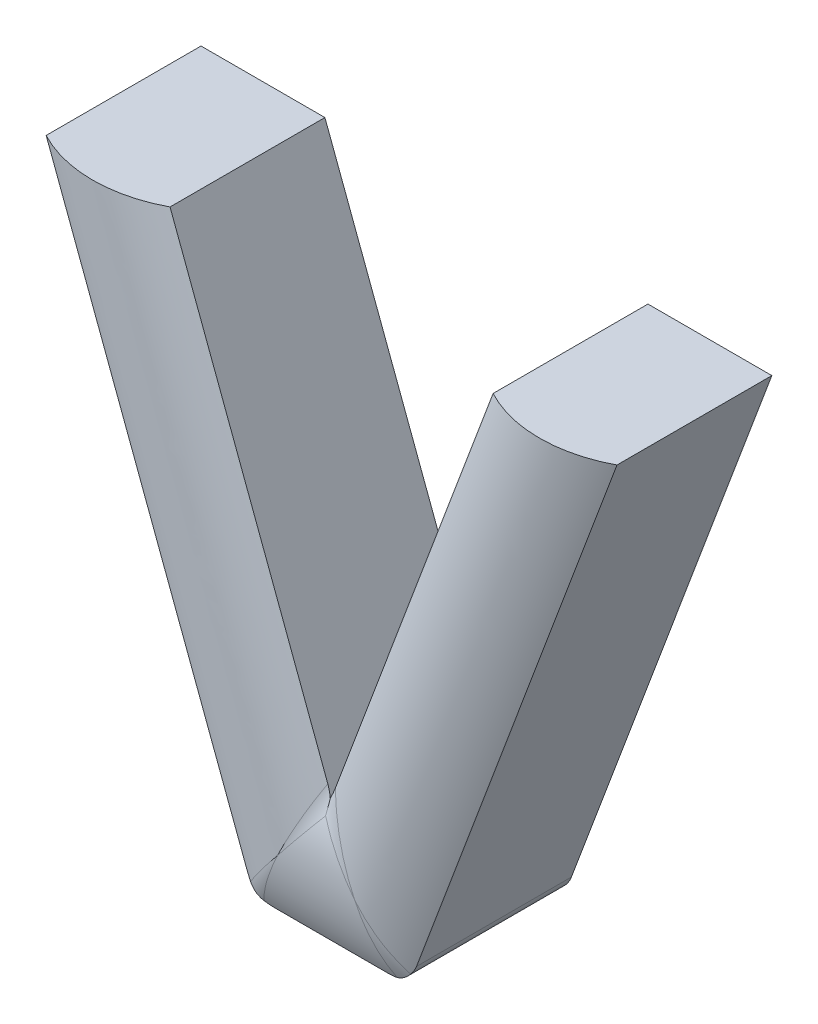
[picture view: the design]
ISO-10303-21;
HEADER;
FILE_DESCRIPTION(('STEP AP214'),'2;1');
FILE_NAME('part.step','',(''),(''),'','','');
FILE_SCHEMA(('AUTOMOTIVE_DESIGN { 1 0 10303 214 1 1 1 1 }'));
ENDSEC;
DATA;
#1=APPLICATION_CONTEXT('core data for automotive mechanical design processes');
#2=APPLICATION_PROTOCOL_DEFINITION('international standard','automotive_design',2000,#1);
#3=PRODUCT_CONTEXT('',#1,'mechanical');
#4=PRODUCT('Part','Part','',(#3));
#5=PRODUCT_RELATED_PRODUCT_CATEGORY('part','',(#4));
#6=PRODUCT_DEFINITION_FORMATION('','',#4);
#7=PRODUCT_DEFINITION_CONTEXT('part definition',#1,'design');
#8=PRODUCT_DEFINITION('design','',#6,#7);
#9=PRODUCT_DEFINITION_SHAPE('','',#8);
#10=(LENGTH_UNIT() NAMED_UNIT(*) SI_UNIT(.MILLI.,.METRE.));
#11=(NAMED_UNIT(*) PLANE_ANGLE_UNIT() SI_UNIT($,.RADIAN.));
#12=(NAMED_UNIT(*) SI_UNIT($,.STERADIAN.) SOLID_ANGLE_UNIT());
#13=UNCERTAINTY_MEASURE_WITH_UNIT(LENGTH_MEASURE(1.E-05),#10,'distance_accuracy_value','');
#14=(GEOMETRIC_REPRESENTATION_CONTEXT(3) GLOBAL_UNCERTAINTY_ASSIGNED_CONTEXT((#13)) GLOBAL_UNIT_ASSIGNED_CONTEXT((#10,
#11,#12)) REPRESENTATION_CONTEXT('',''));
#15=CARTESIAN_POINT('',(0.,0.,0.));
#16=DIRECTION('',(0.,0.,1.));
#17=DIRECTION('',(1.,0.,0.));
#18=AXIS2_PLACEMENT_3D('',#15,#16,#17);
#19=CARTESIAN_POINT('',(9.99999999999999,7.99999999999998,10.));
#20=CARTESIAN_POINT('',(9.80293541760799,7.68469666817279,10.1681617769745));
#21=CARTESIAN_POINT('',(9.6018816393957,7.36301062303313,10.3142985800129));
#22=CARTESIAN_POINT('',(9.19222223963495,6.70755558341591,10.5648772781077));
#23=CARTESIAN_POINT('',(8.9826653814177,6.37226461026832,10.6696355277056));
#24=CARTESIAN_POINT('',(8.35050491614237,5.36080786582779,10.9190580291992));
#25=CARTESIAN_POINT('',(7.92579834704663,4.6812773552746,11.0002616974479));
#26=CARTESIAN_POINT('',(7.28404710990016,3.65447537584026,10.9998682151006));
#27=CARTESIAN_POINT('',(7.06855851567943,3.30969362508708,10.9789798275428));
#28=CARTESIAN_POINT('',(6.63943695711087,2.62309913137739,10.8948654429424));
#29=CARTESIAN_POINT('',(6.42772278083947,2.28435644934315,10.8321777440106));
#30=CARTESIAN_POINT('',(5.80101287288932,1.28162059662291,10.5829999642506));
#31=CARTESIAN_POINT('',(5.39430138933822,0.630882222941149,10.3364705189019));
#32=CARTESIAN_POINT('',(5.,0.,10.));
#33=B_SPLINE_CURVE_WITH_KNOTS('',3,(#19,#20,#21,#22,#23,#24,#25,#26,#27,#28,#29,#30,#31,#32),
.UNSPECIFIED.,.F.,.F.,(4,2,2,2,2,2,4),(0.,0.125,0.25,0.5,0.625,0.75,1.),.UNSPECIFIED.);
#34=DIRECTION('',(-1.,0.,0.));
#35=VECTOR('',#34,1.);
#36=SURFACE_OF_LINEAR_EXTRUSION('',#33,#35);
#37=CARTESIAN_POINT('',(2.49997175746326,4.0000488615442,11.0000000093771));
#38=CARTESIAN_POINT('',(2.49997175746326,4.0000488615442,11.0000000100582));
#39=CARTESIAN_POINT('',(2.49997176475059,4.00004885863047,11.0000000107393));
#40=CARTESIAN_POINT('',(2.4961436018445,4.00491754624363,11.0000000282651));
#41=CARTESIAN_POINT('',(2.49670318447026,4.00527206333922,11.0000000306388));
#42=CARTESIAN_POINT('',(2.49726277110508,4.00562657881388,11.0000000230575));
#43=CARTESIAN_POINT('',(2.49232302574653,4.00978984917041,10.9999959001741));
#44=CARTESIAN_POINT('',(2.49344307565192,4.0104991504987,10.9999953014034));
#45=CARTESIAN_POINT('',(2.49456312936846,4.01120844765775,10.9999960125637));
#46=CARTESIAN_POINT('',(2.47284935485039,4.0346745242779,10.9999536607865));
#47=CARTESIAN_POINT('',(2.4768336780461,4.03719608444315,10.9999469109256));
#48=CARTESIAN_POINT('',(2.48081801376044,4.03971761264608,10.9999549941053));
#49=CARTESIAN_POINT('',(2.45728604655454,4.0547285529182,10.9998498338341));
#50=CARTESIAN_POINT('',(2.46358440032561,4.05871141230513,10.9998279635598));
#51=CARTESIAN_POINT('',(2.46988285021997,4.0626940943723,10.9998541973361));
#52=CARTESIAN_POINT('',(2.42608551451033,4.09478841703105,10.9995025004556));
#53=CARTESIAN_POINT('',(2.43700119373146,4.10169741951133,10.9994298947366));
#54=CARTESIAN_POINT('',(2.44791625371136,4.10860723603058,10.9995166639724));
#55=CARTESIAN_POINT('',(2.41044829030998,4.11479425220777,10.9992589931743));
#56=CARTESIAN_POINT('',(2.42366711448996,4.12316833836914,10.9991507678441));
#57=CARTESIAN_POINT('',(2.43688482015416,4.13154389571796,10.9992799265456));
#58=CARTESIAN_POINT('',(2.36351629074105,4.1747859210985,10.9983191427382));
#59=CARTESIAN_POINT('',(2.38364268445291,4.18756037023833,10.9980731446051));
#60=CARTESIAN_POINT('',(2.40376546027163,4.20033952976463,10.9983656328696));
#61=CARTESIAN_POINT('',(2.33220143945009,4.21474559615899,10.9974134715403));
#62=CARTESIAN_POINT('',(2.35693046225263,4.23046023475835,10.9970343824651));
#63=CARTESIAN_POINT('',(2.3816526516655,4.24618379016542,10.9974839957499));
#64=CARTESIAN_POINT('',(2.26949416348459,4.2945814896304,10.9950443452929));
#65=CARTESIAN_POINT('',(2.30342616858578,4.3161804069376,10.9943161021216));
#66=CARTESIAN_POINT('',(2.33733464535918,4.33781141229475,10.9951756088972));
#67=CARTESIAN_POINT('',(2.23810173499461,4.33445770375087,10.9935808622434));
#68=CARTESIAN_POINT('',(2.27663288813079,4.35900262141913,10.9926364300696));
#69=CARTESIAN_POINT('',(2.31512944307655,4.38359477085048,10.9937488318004));
#70=CARTESIAN_POINT('',(2.17527711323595,4.41413969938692,10.9900961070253));
#71=CARTESIAN_POINT('',(2.22301353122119,4.44457386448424,10.9886361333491));
#72=CARTESIAN_POINT('',(2.27067920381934,4.47510551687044,10.9903498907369));
#73=CARTESIAN_POINT('',(2.14384492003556,4.45394548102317,10.988074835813));
#74=CARTESIAN_POINT('',(2.19618624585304,4.48732480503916,10.9863153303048));
#75=CARTESIAN_POINT('',(2.24843416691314,4.52083290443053,10.9883777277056));
#76=CARTESIAN_POINT('',(2.04950963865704,4.57328439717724,10.9811727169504));
#77=CARTESIAN_POINT('',(2.11568049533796,4.61549859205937,10.9783889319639));
#78=CARTESIAN_POINT('',(2.18167817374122,4.65794957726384,10.9816420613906));
#79=CARTESIAN_POINT('',(1.98657874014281,4.65272526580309,10.9754539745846));
#80=CARTESIAN_POINT('',(2.06199504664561,4.70081533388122,10.9718198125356));
#81=CARTESIAN_POINT('',(2.13715404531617,4.74925748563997,10.9760597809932));
#82=CARTESIAN_POINT('',(1.86083112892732,4.81142557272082,10.9617732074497));
#83=CARTESIAN_POINT('',(1.95486421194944,4.87116810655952,10.9561113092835));
#84=CARTESIAN_POINT('',(2.04835948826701,4.9316528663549,10.9627189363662));
#85=CARTESIAN_POINT('',(1.7980144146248,4.89068501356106,10.953811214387));
#86=CARTESIAN_POINT('',(1.90140910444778,4.95621965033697,10.9469690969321));
#87=CARTESIAN_POINT('',(2.00408905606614,5.02274034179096,10.9549604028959));
#88=CARTESIAN_POINT('',(1.70402028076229,5.00954560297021,10.9401652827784));
#89=CARTESIAN_POINT('',(1.82160405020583,5.08363891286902,10.9313177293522));
#90=CARTESIAN_POINT('',(1.9380680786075,5.15928643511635,10.9416919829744));
#91=CARTESIAN_POINT('',(1.67271164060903,5.0491810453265,10.9353299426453));
#92=CARTESIAN_POINT('',(1.7950428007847,5.12612181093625,10.9257721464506));
#93=CARTESIAN_POINT('',(1.91611420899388,5.20481058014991,10.936994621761));
#94=CARTESIAN_POINT('',(1.61014120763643,5.12840568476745,10.9250931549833));
#95=CARTESIAN_POINT('',(1.74190806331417,5.21103778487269,10.9140319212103));
#96=CARTESIAN_POINT('',(1.8720996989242,5.29585592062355,10.9270291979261));
#97=CARTESIAN_POINT('',(1.57887941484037,5.16799488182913,10.919691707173));
#98=CARTESIAN_POINT('',(1.71533345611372,5.25347262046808,10.907836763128));
#99=CARTESIAN_POINT('',(1.85003905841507,5.34137711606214,10.921761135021));
#100=CARTESIAN_POINT('',(1.48515985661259,5.28668470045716,10.902638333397));
#101=CARTESIAN_POINT('',(1.6356888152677,5.3806697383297,10.8882809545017));
#102=CARTESIAN_POINT('',(1.78392483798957,5.4778313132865,10.9051333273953));
#103=CARTESIAN_POINT('',(1.42276692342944,5.36570880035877,10.8901372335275));
#104=CARTESIAN_POINT('',(1.5827266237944,5.46527889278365,10.8739551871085));
#105=CARTESIAN_POINT('',(1.73993826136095,5.56865636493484,10.8929498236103));
#106=CARTESIAN_POINT('',(1.29821054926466,5.5235551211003,10.8628638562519));
#107=CARTESIAN_POINT('',(1.47704476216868,5.63411929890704,10.8427369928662));
#108=CARTESIAN_POINT('',(1.65202222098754,5.75003272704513,10.8663620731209));
#109=CARTESIAN_POINT('',(1.23604710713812,5.60237734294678,10.8480915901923));
#110=CARTESIAN_POINT('',(1.42431623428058,5.71836471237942,10.8258390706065));
#111=CARTESIAN_POINT('',(1.60809275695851,5.84058403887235,10.8519578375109));
#112=CARTESIAN_POINT('',(1.11197891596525,5.7597827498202,10.8162780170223));
#113=CARTESIAN_POINT('',(1.31913578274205,5.88641573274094,10.7894924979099));
#114=CARTESIAN_POINT('',(1.52030402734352,6.02136272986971,10.8209242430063));
#115=CARTESIAN_POINT('',(1.0500741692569,5.83836593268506,10.7992366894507));
#116=CARTESIAN_POINT('',(1.26667538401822,5.97023488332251,10.7700375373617));
#117=CARTESIAN_POINT('',(1.47644476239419,6.11159010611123,10.8042948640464));
#118=CARTESIAN_POINT('',(0.953052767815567,5.96174695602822,10.770654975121));
#119=CARTESIAN_POINT('',(1.18452145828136,6.10158759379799,10.7374864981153));
#120=CARTESIAN_POINT('',(1.407592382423,6.2531043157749,10.7764144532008));
#121=CARTESIAN_POINT('',(0.917825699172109,6.00659066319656,10.7598870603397));
#122=CARTESIAN_POINT('',(1.15468986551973,6.14930305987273,10.7252310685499));
#123=CARTESIAN_POINT('',(1.3825695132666,6.30450766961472,10.765912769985));
#124=CARTESIAN_POINT('',(0.847441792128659,6.09591418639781,10.7376717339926));
#125=CARTESIAN_POINT('',(1.0950923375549,6.24441609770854,10.6999055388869));
#126=CARTESIAN_POINT('',(1.33249829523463,6.40716992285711,10.7441714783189));
#127=CARTESIAN_POINT('',(0.812284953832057,6.14039400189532,10.7262243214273));
#128=CARTESIAN_POINT('',(1.06532466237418,6.29181625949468,10.6868339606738));
#129=CARTESIAN_POINT('',(1.30744994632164,6.45842882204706,10.732931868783));
#130=CARTESIAN_POINT('',(0.706938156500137,6.27372708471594,10.6907492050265));
#131=CARTESIAN_POINT('',(0.97618847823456,6.43378781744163,10.6463662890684));
#132=CARTESIAN_POINT('',(1.23246056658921,6.61191083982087,10.69815528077));
#133=CARTESIAN_POINT('',(0.636870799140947,6.36247539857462,10.6655882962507));
#134=CARTESIAN_POINT('',(0.91706013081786,6.52801364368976,10.6177455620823));
#135=CARTESIAN_POINT('',(1.18267440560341,6.7138409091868,10.6735602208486));
#136=CARTESIAN_POINT('',(0.497278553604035,6.53936145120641,10.6123151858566));
#137=CARTESIAN_POINT('',(0.799515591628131,6.71550547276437,10.557247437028));
#138=CARTESIAN_POINT('',(1.08356213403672,6.91698403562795,10.6215145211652));
#139=CARTESIAN_POINT('',(0.427753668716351,6.62749918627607,10.5842029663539));
#140=CARTESIAN_POINT('',(0.741087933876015,6.80879013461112,10.5253565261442));
#141=CARTESIAN_POINT('',(1.03423602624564,7.01819708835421,10.5940638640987));
#142=CARTESIAN_POINT('',(0.289320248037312,6.80298309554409,10.5250599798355));
#143=CARTESIAN_POINT('',(0.625007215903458,6.99423972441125,10.4583425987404));
#144=CARTESIAN_POINT('',(0.93605083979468,7.21983522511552,10.5362814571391));
#145=CARTESIAN_POINT('',(0.220411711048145,6.89032927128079,10.4940292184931));
#146=CARTESIAN_POINT('',(0.567343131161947,7.08642253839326,10.4232046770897));
#147=CARTESIAN_POINT('',(0.887191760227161,7.32026031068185,10.5059497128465));
#148=CARTESIAN_POINT('',(0.0147061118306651,7.15125972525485,10.3964683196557));
#149=CARTESIAN_POINT('',(0.395347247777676,7.361589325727,10.31280943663));
#150=CARTESIAN_POINT('',(0.741278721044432,7.62023422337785,10.4105808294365));
#151=CARTESIAN_POINT('',(-0.121102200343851,7.32377547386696,10.3254576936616));
#152=CARTESIAN_POINT('',(0.282363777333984,7.54263065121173,10.2327413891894));
#153=CARTESIAN_POINT('',(0.644866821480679,7.81852718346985,10.3411584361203));
#154=CARTESIAN_POINT('',(-0.322519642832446,7.57957362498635,10.2101047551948));
#155=CARTESIAN_POINT('',(0.115699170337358,7.80953956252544,10.1033993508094));
#156=CARTESIAN_POINT('',(0.501385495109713,8.11287375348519,10.2280609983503));
#157=CARTESIAN_POINT('',(-0.389284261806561,7.66435388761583,10.1701755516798));
#158=CARTESIAN_POINT('',(0.0604717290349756,7.89795926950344,10.0586183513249));
#159=CARTESIAN_POINT('',(0.453742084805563,8.21048547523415,10.1888625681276));
#160=CARTESIAN_POINT('',(-0.522027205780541,7.83292123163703,10.0873342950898));
#161=CARTESIAN_POINT('',(-0.0491472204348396,8.07334547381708,9.96592239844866));
#162=CARTESIAN_POINT('',(0.358791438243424,8.40458703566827,10.1074355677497));
#163=CARTESIAN_POINT('',(-0.588005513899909,7.9167082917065,10.0444221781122));
#164=CARTESIAN_POINT('',(-0.103544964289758,8.16032158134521,9.91799000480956));
#165=CARTESIAN_POINT('',(0.311484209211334,8.50107685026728,10.0652069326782));
#166=CARTESIAN_POINT('',(-0.653581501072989,7.99999995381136,10.0000000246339));
#167=CARTESIAN_POINT('',(-0.157438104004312,8.24640021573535,9.86858654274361));
#168=CARTESIAN_POINT('',(0.264322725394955,8.59696238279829,10.021442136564));
#169=CARTESIAN_POINT('',(-0.658921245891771,8.00837109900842,9.99553541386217));
#170=CARTESIAN_POINT('',(-0.161896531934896,8.25436844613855,9.86433682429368));
#171=CARTESIAN_POINT('',(0.260482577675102,8.60477115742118,10.0178781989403));
#172=CARTESIAN_POINT('',(-0.664240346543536,8.01675238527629,9.99106539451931));
#173=CARTESIAN_POINT('',(-0.1663355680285,8.2623466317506,9.86008179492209));
#174=CARTESIAN_POINT('',(0.25665918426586,8.61259153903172,10.014309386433));
#175=CARTESIAN_POINT('',(-0.674837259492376,8.03353523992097,9.98211453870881));
#176=CARTESIAN_POINT('',(-0.175175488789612,8.27832407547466,9.85156049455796));
#177=CARTESIAN_POINT('',(0.249045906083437,8.62825551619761,10.0071620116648));
#178=CARTESIAN_POINT('',(-0.680115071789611,8.0419368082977,9.97763370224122));
#179=CARTESIAN_POINT('',(-0.17957637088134,8.28632334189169,9.84729421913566));
#180=CARTESIAN_POINT('',(0.245256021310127,8.63609911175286,10.0035834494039));
#181=CARTESIAN_POINT('',(-0.68537223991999,8.05034851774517,9.97314745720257));
#182=CARTESIAN_POINT('',(-0.183957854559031,8.29433258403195,9.84302262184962));
#183=CARTESIAN_POINT('',(0.241482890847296,8.64395431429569,10.0000000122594));
#184=CARTESIAN_POINT('',(-0.702228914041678,8.07731919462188,9.95876309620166));
#185=CARTESIAN_POINT('',(-0.200814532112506,8.32130326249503,9.82863826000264));
#186=CARTESIAN_POINT('',(0.224626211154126,8.67092499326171,9.98561564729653));
#187=CARTESIAN_POINT('',(-0.719085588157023,8.10428987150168,9.9443787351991));
#188=CARTESIAN_POINT('',(-0.217671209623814,8.34827394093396,9.81425389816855));
#189=CARTESIAN_POINT('',(0.20776953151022,8.69789567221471,9.97123128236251));
#190=CARTESIAN_POINT('',(-2.89035595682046,11.5783222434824,8.09156147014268));
#191=CARTESIAN_POINT('',(-2.38894193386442,11.8223063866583,7.96143659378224));
#192=CARTESIAN_POINT('',(-1.96350154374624,12.1719283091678,8.11841351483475));
#193=CARTESIAN_POINT('',(-5.04476954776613,15.0253839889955,6.25312853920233));
#194=CARTESIAN_POINT('',(-4.54335544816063,15.2693680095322,6.12300372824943));
#195=CARTESIAN_POINT('',(-4.11791513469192,15.6189900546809,6.2799805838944));
#196=CARTESIAN_POINT('',(-7.19918303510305,18.4724457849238,4.41469558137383));
#197=CARTESIAN_POINT('',(-6.6977686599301,18.7164298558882,4.28457074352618));
#198=CARTESIAN_POINT('',(-6.27232792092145,19.066051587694,4.4415481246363));
#199=(BOUNDED_SURFACE() B_SPLINE_SURFACE(3,2,((#37,#38,#39),(#40,#41,#42),(#43,#44,#45),(#46,
#47,#48),(#49,#50,#51),(#52,#53,#54),(#55,#56,#57),(#58,#59,#60),(#61,#62,#63),(#64,#65,#66),
(#67,#68,#69),(#70,#71,#72),(#73,#74,#75),(#76,#77,#78),(#79,#80,#81),(#82,#83,#84),(#85,#86,
#87),(#88,#89,#90),(#91,#92,#93),(#94,#95,#96),(#97,#98,#99),(#100,#101,#102),(#103,#104,#105),
(#106,#107,#108),(#109,#110,#111),(#112,#113,#114),(#115,#116,#117),(#118,#119,#120),(#121,#122,
#123),(#124,#125,#126),(#127,#128,#129),(#130,#131,#132),(#133,#134,#135),(#136,#137,#138),
(#139,#140,#141),(#142,#143,#144),(#145,#146,#147),(#148,#149,#150),(#151,#152,#153),(#154,#155,
#156),(#157,#158,#159),(#160,#161,#162),(#163,#164,#165),(#166,#167,#168),(#169,#170,#171),
(#172,#173,#174),(#175,#176,#177),(#178,#179,#180),(#181,#182,#183),(#184,#185,#186),(#187,#188,
#189),(#190,#191,#192),(#193,#194,#195),(#196,#197,#198)),.UNSPECIFIED.,.F.,.F.,
.F.) B_SPLINE_SURFACE_WITH_KNOTS((4,2,2,2,2,2,2,2,2,2,2,2,2,2,2,2,2,2,2,2,2,3,2,3,2,4),(3,3),
(0.,0.0213450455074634,0.1089583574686,0.196572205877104,0.371801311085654,0.547039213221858,
0.722276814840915,1.0728127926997,1.42334381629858,1.59878660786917,1.77422948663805,
2.12510971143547,2.47598818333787,2.8268698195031,3.02737444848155,3.22787937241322,
3.62888287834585,4.02988881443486,4.4308939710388,5.23272493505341,5.63373791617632,
6.03475949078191,6.06741949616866,6.10007950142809,6.20479947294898,19.5888240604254),(0.,1.),
.UNSPECIFIED.) GEOMETRIC_REPRESENTATION_ITEM() RATIONAL_B_SPLINE_SURFACE(((1.,1.,1.),(1.,
1.00000000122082,1.),(1.,0.999999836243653,1.),(1.,0.999998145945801,1.),(1.,0.999993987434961,
1.),(1.,0.99998007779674,1.),(1.,0.999970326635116,1.),(1.,0.999932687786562,1.),(1.,
0.999896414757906,1.),(1.,0.999801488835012,1.),(1.,0.999742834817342,1.),(1.,0.999603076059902,
1.),(1.,0.999521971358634,1.),(1.,0.999244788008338,1.),(1.,0.999014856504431,1.),(1.,
0.998463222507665,1.),(1.,0.998141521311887,1.),(1.,0.997588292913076,1.),(1.,0.997391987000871,
1.),(1.,0.996978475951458,1.),(1.,0.996761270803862,1.),(1.,0.99607593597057,1.),(1.,
0.995574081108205,1.),(1.,0.994484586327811,1.),(1.,0.993896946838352,1.),(1.,0.992638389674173,
1.),(1.,0.991967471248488,1.),(1.,0.990852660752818,1.),(1.,0.99043470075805,1.),(1.,
0.989568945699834,1.),(1.,0.989121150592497,1.),(1.,0.987737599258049,1.),(1.,0.986761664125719,
1.),(1.,0.984701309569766,1.),(1.,0.983616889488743,1.),(1.,0.981339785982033,1.),(1.,
0.980147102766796,1.),(1.,0.976419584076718,1.),(1.,0.973734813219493,1.),(1.,0.969439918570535,
1.),(1.,0.967963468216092,1.),(1.,0.964932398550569,1.),(1.,0.96337777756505,1.),(1.,
0.961789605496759,1.),(1.,0.961720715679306,1.),(1.,0.961651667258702,1.),(1.,0.961513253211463,
1.),(1.,0.961443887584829,1.),(1.,0.961374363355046,1.),(1.,0.961374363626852,1.),(1.,
0.961374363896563,1.),(1.,0.961374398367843,1.),(1.,0.961374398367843,1.),(1.,0.961374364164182,1.))) REPRESENTATION_ITEM('') SURFACE());
#200=CARTESIAN_POINT('',(2.49997175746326,4.0000488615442,11.0000000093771));
#201=CARTESIAN_POINT('',(2.4961436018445,4.00491754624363,11.0000000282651));
#202=CARTESIAN_POINT('',(2.49232302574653,4.00978984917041,10.9999959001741));
#203=CARTESIAN_POINT('',(2.47284935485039,4.0346745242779,10.9999536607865));
#204=CARTESIAN_POINT('',(2.45728604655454,4.0547285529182,10.9998498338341));
#205=CARTESIAN_POINT('',(2.42608551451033,4.09478841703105,10.9995025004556));
#206=CARTESIAN_POINT('',(2.41044829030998,4.11479425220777,10.9992589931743));
#207=CARTESIAN_POINT('',(2.36351629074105,4.1747859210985,10.9983191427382));
#208=CARTESIAN_POINT('',(2.33220143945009,4.21474559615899,10.9974134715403));
#209=CARTESIAN_POINT('',(2.26949416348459,4.2945814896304,10.9950443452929));
#210=CARTESIAN_POINT('',(2.23810173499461,4.33445770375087,10.9935808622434));
#211=CARTESIAN_POINT('',(2.17527711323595,4.41413969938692,10.9900961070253));
#212=CARTESIAN_POINT('',(2.14384492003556,4.45394548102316,10.988074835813));
#213=CARTESIAN_POINT('',(2.04950963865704,4.57328439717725,10.9811727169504));
#214=CARTESIAN_POINT('',(1.98657874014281,4.65272526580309,10.9754539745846));
#215=CARTESIAN_POINT('',(1.86083112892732,4.81142557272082,10.9617732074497));
#216=CARTESIAN_POINT('',(1.7980144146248,4.89068501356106,10.953811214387));
#217=CARTESIAN_POINT('',(1.70402028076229,5.00954560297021,10.9401652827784));
#218=CARTESIAN_POINT('',(1.67271164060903,5.0491810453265,10.9353299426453));
#219=CARTESIAN_POINT('',(1.61014120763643,5.12840568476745,10.9250931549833));
#220=CARTESIAN_POINT('',(1.57887941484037,5.16799488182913,10.919691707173));
#221=CARTESIAN_POINT('',(1.48515985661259,5.28668470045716,10.902638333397));
#222=CARTESIAN_POINT('',(1.42276692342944,5.36570880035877,10.8901372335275));
#223=CARTESIAN_POINT('',(1.29821054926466,5.5235551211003,10.8628638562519));
#224=CARTESIAN_POINT('',(1.23604710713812,5.60237734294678,10.8480915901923));
#225=CARTESIAN_POINT('',(1.11197891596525,5.7597827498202,10.8162780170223));
#226=CARTESIAN_POINT('',(1.0500741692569,5.83836593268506,10.7992366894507));
#227=CARTESIAN_POINT('',(0.953052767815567,5.96174695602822,10.770654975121));
#228=CARTESIAN_POINT('',(0.917825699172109,6.00659066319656,10.7598870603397));
#229=CARTESIAN_POINT('',(0.847441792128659,6.09591418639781,10.7376717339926));
#230=CARTESIAN_POINT('',(0.812284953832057,6.14039400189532,10.7262243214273));
#231=CARTESIAN_POINT('',(0.706938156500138,6.27372708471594,10.6907492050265));
#232=CARTESIAN_POINT('',(0.636870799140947,6.36247539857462,10.6655882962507));
#233=CARTESIAN_POINT('',(0.497278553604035,6.53936145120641,10.6123151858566));
#234=CARTESIAN_POINT('',(0.427753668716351,6.62749918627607,10.5842029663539));
#235=CARTESIAN_POINT('',(0.289320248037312,6.80298309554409,10.5250599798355));
#236=CARTESIAN_POINT('',(0.220411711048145,6.89032927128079,10.4940292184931));
#237=CARTESIAN_POINT('',(0.0147061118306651,7.15125972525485,10.3964683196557));
#238=CARTESIAN_POINT('',(-0.121102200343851,7.32377547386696,10.3254576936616));
#239=CARTESIAN_POINT('',(-0.322519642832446,7.57957362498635,10.2101047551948));
#240=CARTESIAN_POINT('',(-0.389284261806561,7.66435388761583,10.1701755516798));
#241=CARTESIAN_POINT('',(-0.522027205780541,7.83292123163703,10.0873342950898));
#242=CARTESIAN_POINT('',(-0.588005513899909,7.9167082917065,10.0444221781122));
#243=CARTESIAN_POINT('',(-0.653581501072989,7.99999995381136,10.0000000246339));
#244=CARTESIAN_POINT('',(-0.658921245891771,8.00837109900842,9.99553541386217));
#245=CARTESIAN_POINT('',(-0.664240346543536,8.01675238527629,9.99106539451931));
#246=CARTESIAN_POINT('',(-0.674837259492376,8.03353523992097,9.98211453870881));
#247=CARTESIAN_POINT('',(-0.680115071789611,8.0419368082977,9.97763370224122));
#248=CARTESIAN_POINT('',(-0.68537223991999,8.05034851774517,9.97314745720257));
#249=CARTESIAN_POINT('',(-0.702228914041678,8.07731919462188,9.95876309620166));
#250=CARTESIAN_POINT('',(-0.719085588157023,8.10428987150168,9.9443787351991));
#251=CARTESIAN_POINT('',(-2.89035595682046,11.5783222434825,8.09156147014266));
#252=CARTESIAN_POINT('',(-5.04476954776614,15.0253839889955,6.25312853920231));
#253=CARTESIAN_POINT('',(-7.19918303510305,18.4724457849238,4.41469558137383));
#254=B_SPLINE_CURVE_WITH_KNOTS('',3,(#200,#201,#202,#203,#204,#205,#206,#207,#208,#209,#210,
#211,#212,#213,#214,#215,#216,#217,#218,#219,#220,#221,#222,#223,#224,#225,#226,#227,#228,#229,
#230,#231,#232,#233,#234,#235,#236,#237,#238,#239,#240,#241,#242,#243,#244,#245,#246,#247,#248,
#249,#250,#251,#252,#253),.UNSPECIFIED.,.F.,.F.,(4,2,2,2,2,2,2,2,2,2,2,2,2,2,2,2,2,2,2,2,2,3,2,
3,2,4),(0.,0.0213450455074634,0.1089583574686,0.196572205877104,0.371801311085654,
0.547039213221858,0.722276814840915,1.0728127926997,1.42334381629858,1.59878660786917,
1.77422948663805,2.12510971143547,2.47598818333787,2.8268698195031,3.02737444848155,
3.22787937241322,3.62888287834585,4.02988881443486,4.4308939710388,5.23272493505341,
5.63373791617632,6.03475949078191,6.06741949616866,6.10007950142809,6.20479947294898,
19.5888240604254),.UNSPECIFIED.);
#255=CARTESIAN_POINT('',(2.50005570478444,3.99993964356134,11.0000000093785));
#256=VERTEX_POINT('',#255);
#257=CARTESIAN_POINT('',(-0.000370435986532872,7.17046811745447,10.3865835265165));
#258=VERTEX_POINT('',#257);
#259=EDGE_CURVE('E1416',#256,#258,#254,.T.);
#260=ORIENTED_EDGE('',*,*,#259,.T.);
#261=CARTESIAN_POINT('',(-2.50001834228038,4.00004885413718,11.));
#262=CARTESIAN_POINT('',(-2.50001834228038,4.00004885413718,11.0000000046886));
#263=CARTESIAN_POINT('',(-2.50001832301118,4.0000488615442,11.0000000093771));
#264=CARTESIAN_POINT('',(-2.49734051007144,4.00564338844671,11.0000000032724));
#265=CARTESIAN_POINT('',(-2.49677865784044,4.00528797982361,11.0000000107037));
#266=CARTESIAN_POINT('',(-2.49621679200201,4.00493257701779,11.0000000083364));
#267=CARTESIAN_POINT('',(-2.49466228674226,4.01123764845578,10.999995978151));
#268=CARTESIAN_POINT('',(-2.4935385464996,4.0105267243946,10.9999952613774));
#269=CARTESIAN_POINT('',(-2.49241480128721,4.00981580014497,10.9999958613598));
#270=CARTESIAN_POINT('',(-2.40455945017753,4.19940783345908,10.9997250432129));
#271=CARTESIAN_POINT('',(-2.384532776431,4.186736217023,10.9996755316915));
#272=CARTESIAN_POINT('',(-2.36450851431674,4.17406094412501,10.999716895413));
#273=CARTESIAN_POINT('',(-2.31672759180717,4.38168953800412,10.9951699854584));
#274=CARTESIAN_POINT('',(-2.27828995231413,4.3573552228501,10.9942983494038));
#275=CARTESIAN_POINT('',(-2.23992705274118,4.33290046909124,10.9950295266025));
#276=CARTESIAN_POINT('',(-2.14081753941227,4.74555311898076,10.9774092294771));
#277=CARTESIAN_POINT('',(-2.0657820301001,4.69749831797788,10.9733711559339));
#278=CARTESIAN_POINT('',(-1.9905705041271,4.64967111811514,10.9768001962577));
#279=CARTESIAN_POINT('',(-2.05273929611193,4.92713483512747,10.9642016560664));
#280=CARTESIAN_POINT('',(-1.95944061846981,4.86714347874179,10.9578039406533));
#281=CARTESIAN_POINT('',(-1.86579538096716,4.80760203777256,10.9632563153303));
#282=CARTESIAN_POINT('',(-1.87660697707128,5.28951892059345,10.929074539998));
#283=CARTESIAN_POINT('',(-1.74718439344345,5.20522439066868,10.9164868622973));
#284=CARTESIAN_POINT('',(-1.61643858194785,5.1227391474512,10.9272605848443));
#285=CARTESIAN_POINT('',(-1.78855301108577,5.47032034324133,10.9071464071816));
#286=CARTESIAN_POINT('',(-1.64119518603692,5.37377734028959,10.8906974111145));
#287=CARTESIAN_POINT('',(-1.49185721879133,5.27994446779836,10.9047999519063));
#288=CARTESIAN_POINT('',(-1.6568871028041,5.7406253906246,10.8677147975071));
#289=CARTESIAN_POINT('',(-1.48317289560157,5.62526656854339,10.8444579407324));
#290=CARTESIAN_POINT('',(-1.30568098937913,5.51515484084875,10.86438754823));
#291=CARTESIAN_POINT('',(-1.61306633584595,5.83058023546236,10.8534805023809));
#292=CARTESIAN_POINT('',(-1.43060167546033,5.70896436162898,10.8277645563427));
#293=CARTESIAN_POINT('',(-1.24373637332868,5.5934610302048,10.8497959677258));
#294=CARTESIAN_POINT('',(-1.525604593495,6.01016964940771,10.8228311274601));
#295=CARTESIAN_POINT('',(-1.32580584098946,5.87592635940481,10.7918598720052));
#296=CARTESIAN_POINT('',(-1.12013718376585,5.74984108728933,10.8183739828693));
#297=CARTESIAN_POINT('',(-1.48196361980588,6.09980421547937,10.8064160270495));
#298=CARTESIAN_POINT('',(-1.27357275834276,5.9592042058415,10.772642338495));
#299=CARTESIAN_POINT('',(-1.05848261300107,5.82791495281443,10.8015435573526));
#300=CARTESIAN_POINT('',(-1.41331250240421,6.24095155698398,10.7788033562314));
#301=CARTESIAN_POINT('',(-1.19153927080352,6.09027081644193,10.7403548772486));
#302=CARTESIAN_POINT('',(-0.961517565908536,5.95106384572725,10.7731840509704));
#303=CARTESIAN_POINT('',(-1.38821779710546,6.2925771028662,10.7683300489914));
#304=CARTESIAN_POINT('',(-1.16156497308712,6.13822025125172,10.7281088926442));
#305=CARTESIAN_POINT('',(-0.926077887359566,5.99615003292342,10.7624179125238));
#306=CARTESIAN_POINT('',(-1.33809378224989,6.39568685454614,10.7466537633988));
#307=CARTESIAN_POINT('',(-1.10174928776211,6.23379443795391,10.7027950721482));
#308=CARTESIAN_POINT('',(-0.855307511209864,6.08594769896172,10.7402023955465));
#309=CARTESIAN_POINT('',(-1.313064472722,6.44717106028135,10.7354507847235));
#310=CARTESIAN_POINT('',(-1.07190606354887,6.28142202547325,10.6897256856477));
#311=CARTESIAN_POINT('',(-0.819976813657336,6.13065917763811,10.7287530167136));
#312=CARTESIAN_POINT('',(-1.23806666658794,6.60138402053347,10.7007428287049));
#313=CARTESIAN_POINT('',(-0.982525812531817,6.42411738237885,10.6492404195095));
#314=CARTESIAN_POINT('',(-0.714142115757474,6.26471212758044,10.6932528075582));
#315=CARTESIAN_POINT('',(-1.18818755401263,6.70387463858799,10.6761385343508));
#316=CARTESIAN_POINT('',(-0.923212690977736,6.51887902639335,10.6205760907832));
#317=CARTESIAN_POINT('',(-0.643794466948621,6.35397342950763,10.6680496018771));
#318=CARTESIAN_POINT('',(-1.08875639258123,6.90817662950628,10.6240000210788));
#319=CARTESIAN_POINT('',(-0.805226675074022,6.70745771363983,10.5599467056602));
#320=CARTESIAN_POINT('',(-0.50363584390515,6.53187458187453,10.61466078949));
#321=CARTESIAN_POINT('',(-1.0392043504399,7.00998798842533,10.5964657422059));
#322=CARTESIAN_POINT('',(-0.746542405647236,6.80129310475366,10.5279681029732));
#323=CARTESIAN_POINT('',(-0.433824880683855,6.62051441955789,10.586475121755));
#324=CARTESIAN_POINT('',(-0.940445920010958,7.21281926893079,10.5384568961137));
#325=CARTESIAN_POINT('',(-0.629864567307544,6.98783299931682,10.4607438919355));
#326=CARTESIAN_POINT('',(-0.294778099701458,6.79697976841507,10.5271593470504));
#327=CARTESIAN_POINT('',(-0.891239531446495,7.31383919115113,10.5079823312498));
#328=CARTESIAN_POINT('',(-0.571859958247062,7.08055509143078,10.4254834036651));
#329=CARTESIAN_POINT('',(-0.225542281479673,6.88480528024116,10.4960292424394));
#330=CARTESIAN_POINT('',(-0.744178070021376,7.61555226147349,10.4121282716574));
#331=CARTESIAN_POINT('',(-0.398742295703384,7.35729594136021,10.3146774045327));
#332=CARTESIAN_POINT('',(-0.0187678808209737,7.14712462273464,10.3981399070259));
#333=CARTESIAN_POINT('',(-0.646862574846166,7.81493600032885,10.3423089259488));
#334=CARTESIAN_POINT('',(-0.284883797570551,7.53931643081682,10.234281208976));
#335=CARTESIAN_POINT('',(0.117863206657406,7.32049367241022,10.3268719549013));
#336=CARTESIAN_POINT('',(-0.502271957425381,8.11075894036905,10.2286683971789));
#337=CARTESIAN_POINT('',(-0.117040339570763,7.8075671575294,10.1043950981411));
#338=CARTESIAN_POINT('',(0.32054225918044,7.57753057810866,10.2110582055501));
#339=CARTESIAN_POINT('',(-0.454300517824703,8.20883468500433,10.1892983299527));
#340=CARTESIAN_POINT('',(-0.061441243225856,7.89641421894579,10.0594235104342));
#341=CARTESIAN_POINT('',(0.38773100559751,7.6627156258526,10.170963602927));
#342=CARTESIAN_POINT('',(-0.358864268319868,8.40381750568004,10.1075753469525));
#343=CARTESIAN_POINT('',(0.048802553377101,8.0726165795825,9.96632952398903));
#344=CARTESIAN_POINT('',(0.52128663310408,7.83209582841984,10.0877567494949));
#345=CARTESIAN_POINT('',(-0.311399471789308,8.50072455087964,10.0652223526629));
#346=CARTESIAN_POINT('',(0.103453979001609,8.15998273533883,9.91818881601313));
#347=CARTESIAN_POINT('',(0.587653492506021,7.91629095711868,10.0446444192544));
#348=CARTESIAN_POINT('',(-0.26421033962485,8.5970061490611,10.021372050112));
#349=CARTESIAN_POINT('',(0.15750239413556,8.24643161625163,9.86856979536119));
#350=CARTESIAN_POINT('',(0.653577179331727,7.99999995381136,10.0000000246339));
#351=CARTESIAN_POINT('',(-0.21978222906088,8.6876821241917,9.98007759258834));
#352=CARTESIAN_POINT('',(0.209244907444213,8.33905623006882,9.81917000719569));
#353=CARTESIAN_POINT('',(0.715646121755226,8.09729126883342,9.94811132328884));
#354=CARTESIAN_POINT('',(-0.177743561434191,8.77990432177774,9.93817653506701));
#355=CARTESIAN_POINT('',(0.258264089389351,8.43301512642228,9.76905859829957));
#356=CARTESIAN_POINT('',(0.774872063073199,8.1959587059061,9.89548869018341));
#357=CARTESIAN_POINT('',(-0.0981517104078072,8.96698106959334,9.85334905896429));
#358=CARTESIAN_POINT('',(0.351267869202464,8.62328860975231,9.66757940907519));
#359=CARTESIAN_POINT('',(0.887966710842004,8.39559901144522,9.78901386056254));
#360=CARTESIAN_POINT('',(-0.0605963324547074,9.0618343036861,9.81042315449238));
#361=CARTESIAN_POINT('',(0.395250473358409,8.71961558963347,9.61620501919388));
#362=CARTESIAN_POINT('',(0.941838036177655,8.4965707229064,9.73516228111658));
#363=CARTESIAN_POINT('',(0.0453903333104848,9.34855391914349,9.68088501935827));
#364=CARTESIAN_POINT('',(0.519773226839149,9.0106162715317,9.461004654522));
#365=CARTESIAN_POINT('',(1.09533945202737,8.80110836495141,9.57274220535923));
#366=CARTESIAN_POINT('',(0.107704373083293,9.54375566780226,9.59297762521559));
#367=CARTESIAN_POINT('',(0.593279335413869,9.20803849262,9.35571280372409));
#368=CARTESIAN_POINT('',(1.18764458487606,9.00755677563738,9.46263638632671));
#369=CARTESIAN_POINT('',(0.247855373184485,10.0472335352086,9.3667834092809));
#370=CARTESIAN_POINT('',(0.759683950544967,9.71647749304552,9.08454533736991));
#371=CARTESIAN_POINT('',(1.40023644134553,9.53819996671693,9.17962668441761));
#372=CARTESIAN_POINT('',(0.316013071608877,10.3598546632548,9.2268317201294));
#373=CARTESIAN_POINT('',(0.841319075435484,10.0308442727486,8.91688305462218));
#374=CARTESIAN_POINT('',(1.50886816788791,9.86599885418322,9.00480061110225));
#375=CARTESIAN_POINT('',(0.425306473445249,10.9944544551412,8.94340031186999));
#376=CARTESIAN_POINT('',(0.973957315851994,10.6669509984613,8.57762613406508));
#377=CARTESIAN_POINT('',(1.69343525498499,10.5288262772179,8.65129265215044));
#378=CARTESIAN_POINT('',(0.466410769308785,11.3164435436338,8.79991669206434));
#379=CARTESIAN_POINT('',(1.02474074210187,10.988881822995,8.40592969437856));
#380=CARTESIAN_POINT('',(1.76933257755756,10.8638627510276,8.47260653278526));
#381=CARTESIAN_POINT('',(0.526729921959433,11.9706422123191,8.50884738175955));
#382=CARTESIAN_POINT('',(1.10144244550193,11.6413004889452,8.05797307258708));
#383=CARTESIAN_POINT('',(1.89491264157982,11.5425342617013,8.11064839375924));
#384=CARTESIAN_POINT('',(0.545625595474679,12.3029320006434,8.36123237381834));
#385=CARTESIAN_POINT('',(1.12681246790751,11.9719484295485,7.88162750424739));
#386=CARTESIAN_POINT('',(1.94420775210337,11.8862238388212,7.92734728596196));
#387=CARTESIAN_POINT('',(0.564191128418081,12.9708271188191,8.06485348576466));
#388=CARTESIAN_POINT('',(1.15556868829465,12.6350522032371,7.52797215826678));
#389=CARTESIAN_POINT('',(2.019400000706,12.5753539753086,7.55981121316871));
#390=CARTESIAN_POINT('',(0.563869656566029,13.3064308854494,7.91609015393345));
#391=CARTESIAN_POINT('',(1.15879646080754,12.967608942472,7.35060856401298));
#392=CARTESIAN_POINT('',(2.04530768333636,12.9207936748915,7.37557670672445));
#393=CARTESIAN_POINT('',(0.545991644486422,14.0123570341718,7.60342317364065));
#394=CARTESIAN_POINT('',(1.14581384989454,13.6660120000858,6.9781269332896));
#395=CARTESIAN_POINT('',(2.07870539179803,13.6459482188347,6.9888276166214));
#396=CARTESIAN_POINT('',(0.52676370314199,14.3828847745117,7.4394527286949));
#397=CARTESIAN_POINT('',(1.12749404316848,14.0317481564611,6.78306764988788));
#398=CARTESIAN_POINT('',(2.08416155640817,14.0257324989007,6.78627600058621));
#399=CARTESIAN_POINT('',(0.471333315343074,15.1251574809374,7.11119087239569));
#400=CARTESIAN_POINT('',(1.07130582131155,14.7629622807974,6.39308678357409));
#401=CARTESIAN_POINT('',(2.0744298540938,14.7851422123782,6.38125748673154));
#402=CARTESIAN_POINT('',(0.435126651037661,15.4969027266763,6.94689939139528));
#403=CARTESIAN_POINT('',(1.03324398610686,15.1285157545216,6.19812493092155));
#404=CARTESIAN_POINT('',(2.05923685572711,15.1647675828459,6.1787906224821));
#405=CARTESIAN_POINT('',(0.347764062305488,16.2412878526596,6.61810079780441));
#406=CARTESIAN_POINT('',(0.939834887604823,15.8591377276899,5.80845987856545));
#407=CARTESIAN_POINT('',(2.01072664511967,15.9237223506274,5.77401474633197));
#408=CARTESIAN_POINT('',(0.296583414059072,16.6139281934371,6.45359378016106));
#409=CARTESIAN_POINT('',(0.884283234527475,16.224260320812,5.6137278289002));
#410=CARTESIAN_POINT('',(1.97737937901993,16.3030502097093,5.57170655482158));
#411=CARTESIAN_POINT('',(0.180923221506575,17.358905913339,6.1248750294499));
#412=CARTESIAN_POINT('',(0.757728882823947,16.9528862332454,5.22512734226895));
#413=CARTESIAN_POINT('',(1.8945379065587,17.0603349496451,5.16782136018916));
#414=CARTESIAN_POINT('',(0.116442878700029,17.7312432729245,5.96066331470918));
#415=CARTESIAN_POINT('',(0.68655829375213,17.3164413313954,5.03123128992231));
#416=CARTESIAN_POINT('',(1.84504273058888,17.4382917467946,4.96624440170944));
#417=CARTESIAN_POINT('',(-0.0209508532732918,18.4562320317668,5.64107443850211));
#418=CARTESIAN_POINT('',(0.534202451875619,18.0228760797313,4.65446609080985));
#419=CARTESIAN_POINT('',(1.73436298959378,18.1732982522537,4.57424093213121));
#420=CARTESIAN_POINT('',(-0.0932684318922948,18.8089213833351,5.48567278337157));
#421=CARTESIAN_POINT('',(0.453532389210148,18.3660824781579,4.47142267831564));
#422=CARTESIAN_POINT('',(1.67390110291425,18.5304334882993,4.38376880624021));
#423=CARTESIAN_POINT('',(-0.247863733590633,19.5133464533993,5.17543418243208));
#424=CARTESIAN_POINT('',(0.280498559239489,19.0503937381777,4.10645667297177));
#425=CARTESIAN_POINT('',(1.54090967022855,19.2429600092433,4.00375466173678));
#426=CARTESIAN_POINT('',(-0.3301419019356,19.8650821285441,5.02059726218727));
#427=CARTESIAN_POINT('',(0.188000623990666,19.391535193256,3.92451456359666));
#428=CARTESIAN_POINT('',(1.46837958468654,19.5983512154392,3.81421268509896));
#429=CARTESIAN_POINT('',(-0.503576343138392,20.5658861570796,4.7122506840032));
#430=CARTESIAN_POINT('',(-0.0074903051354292,20.0700249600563,3.5626533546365));
#431=CARTESIAN_POINT('',(1.3124569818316,20.305722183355,3.43694816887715));
#432=CARTESIAN_POINT('',(-0.594694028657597,20.9149595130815,4.55873818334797));
#433=CARTESIAN_POINT('',(-0.110572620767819,20.4074330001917,3.38270239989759));
#434=CARTESIAN_POINT('',(1.22911118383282,20.6577099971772,3.24922133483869));
#435=CARTESIAN_POINT('',(-0.785527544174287,21.6116843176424,4.25250430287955));
#436=CARTESIAN_POINT('',(-0.32695097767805,21.0796508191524,3.02418622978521));
#437=CARTESIAN_POINT('',(1.05200959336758,21.3595842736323,2.87488838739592));
#438=CARTESIAN_POINT('',(-0.885241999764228,21.9593359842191,4.09978280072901));
#439=CARTESIAN_POINT('',(-0.440376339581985,21.4144966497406,2.84560178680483));
#440=CARTESIAN_POINT('',(0.958255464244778,21.7094710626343,2.68828209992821));
#441=CARTESIAN_POINT('',(-0.988986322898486,22.3062156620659,3.94749026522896));
#442=CARTESIAN_POINT('',(-0.557959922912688,21.7461207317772,2.66873560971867));
#443=CARTESIAN_POINT('',(0.859626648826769,22.0582690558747,2.50225650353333));
#444=(BOUNDED_SURFACE() B_SPLINE_SURFACE(3,2,((#261,#262,#263),(#264,#265,#266),(#267,#268,
#269),(#270,#271,#272),(#273,#274,#275),(#276,#277,#278),(#279,#280,#281),(#282,#283,#284),
(#285,#286,#287),(#288,#289,#290),(#291,#292,#293),(#294,#295,#296),(#297,#298,#299),(#300,#301,
#302),(#303,#304,#305),(#306,#307,#308),(#309,#310,#311),(#312,#313,#314),(#315,#316,#317),
(#318,#319,#320),(#321,#322,#323),(#324,#325,#326),(#327,#328,#329),(#330,#331,#332),(#333,#334,
#335),(#336,#337,#338),(#339,#340,#341),(#342,#343,#344),(#345,#346,#347),(#348,#349,#350),
(#351,#352,#353),(#354,#355,#356),(#357,#358,#359),(#360,#361,#362),(#363,#364,#365),(#366,#367,
#368),(#369,#370,#371),(#372,#373,#374),(#375,#376,#377),(#378,#379,#380),(#381,#382,#383),
(#384,#385,#386),(#387,#388,#389),(#390,#391,#392),(#393,#394,#395),(#396,#397,#398),(#399,#400,
#401),(#402,#403,#404),(#405,#406,#407),(#408,#409,#410),(#411,#412,#413),(#414,#415,#416),
(#417,#418,#419),(#420,#421,#422),(#423,#424,#425),(#426,#427,#428),(#429,#430,#431),(#432,#433,
#434),(#435,#436,#437),(#438,#439,#440),(#441,#442,#443)),.UNSPECIFIED.,.F.,.F.,
.F.) B_SPLINE_SURFACE_WITH_KNOTS((4,2,2,2,2,2,2,2,2,2,2,2,2,2,3,2,2,2,2,2,2,2,2,2,2,2,2,2,2,4),
(3,3),(0.,0.0213492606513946,0.718145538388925,1.4150928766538,2.11272844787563,
2.46156709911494,2.81040904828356,3.01192691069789,3.21344486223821,3.61647484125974,
4.01951306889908,4.42255097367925,5.2284799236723,5.63152973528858,6.03459015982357,
6.4140914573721,6.79340622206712,7.5471615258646,8.70635186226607,9.86688559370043,
11.0439021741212,12.2203878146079,13.5111723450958,14.8022777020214,16.0955269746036,
17.3888539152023,18.6163925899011,19.8439861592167,21.066443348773,22.288705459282),(0.,1.),
.UNSPECIFIED.) GEOMETRIC_REPRESENTATION_ITEM() RATIONAL_B_SPLINE_SURFACE(((1.,1.,1.),(1.,
1.00000000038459,1.),(1.,0.999999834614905,1.),(1.,0.999988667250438,1.),(1.,0.999800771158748,
1.),(1.,0.999066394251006,1.),(1.,0.998519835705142,1.),(1.,0.997070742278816,1.),(1.,
0.996167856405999,1.),(1.,0.994556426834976,1.),(1.,0.993976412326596,1.),(1.,0.992732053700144,
1.),(1.,0.99206770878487,1.),(1.,0.990958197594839,1.),(1.,0.990538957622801,1.),(1.,
0.989668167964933,1.),(1.,0.989216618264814,1.),(1.,0.987823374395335,1.),(1.,0.986843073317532,
1.),(1.,0.984776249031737,1.),(1.,0.983689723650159,1.),(1.,0.981410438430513,1.),(1.,
0.980217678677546,1.),(1.,0.976490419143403,1.),(1.,0.973806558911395,1.),(1.,0.969500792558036,
1.),(1.,0.968018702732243,1.),(1.,0.964969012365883,1.),(1.,0.963401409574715,1.),(1.,
0.961794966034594,1.),(1.,0.960984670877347,1.),(1.,0.960148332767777,1.),(1.,0.958429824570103,
1.),(1.,0.957547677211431,1.),(1.,0.954852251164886,1.),(1.,0.952979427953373,1.),(1.,
0.948070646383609,1.),(1.,0.9449509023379,1.),(1.,0.938506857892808,1.),(1.,0.935182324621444,
1.),(1.,0.928336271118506,1.),(1.,0.924812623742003,1.),(1.,0.91764927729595,1.),(1.,
0.914009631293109,1.),(1.,0.906276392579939,1.),(1.,0.902173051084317,1.),(1.,0.893868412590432,
1.),(1.,0.889667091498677,1.),(1.,0.881170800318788,1.),(1.,0.876875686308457,1.),(1.,
0.868203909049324,1.),(1.,0.863827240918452,1.),(1.,0.855219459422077,1.),(1.,0.850992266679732,
1.),(1.,0.842466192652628,1.),(1.,0.838167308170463,1.),(1.,0.829514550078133,1.),(1.,
0.825160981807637,1.),(1.,0.816378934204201,1.),(1.,0.811950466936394,1.),(1.,0.807482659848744,1.))) REPRESENTATION_ITEM('') SURFACE());
#445=CARTESIAN_POINT('',(0.859626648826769,22.0582690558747,2.50225650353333));
#446=CARTESIAN_POINT('',(0.958255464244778,21.7094710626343,2.68828209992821));
#447=CARTESIAN_POINT('',(1.05200959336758,21.3595842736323,2.87488838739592));
#448=CARTESIAN_POINT('',(1.22911118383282,20.6577099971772,3.24922133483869));
#449=CARTESIAN_POINT('',(1.3124569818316,20.305722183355,3.43694816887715));
#450=CARTESIAN_POINT('',(1.46837958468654,19.5983512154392,3.81421268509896));
#451=CARTESIAN_POINT('',(1.54090967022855,19.2429600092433,4.00375466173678));
#452=CARTESIAN_POINT('',(1.67390110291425,18.5304334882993,4.38376880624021));
#453=CARTESIAN_POINT('',(1.73436298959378,18.1732982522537,4.57424093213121));
#454=CARTESIAN_POINT('',(1.84504273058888,17.4382917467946,4.96624440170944));
#455=CARTESIAN_POINT('',(1.8945379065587,17.0603349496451,5.16782136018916));
#456=CARTESIAN_POINT('',(1.97737937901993,16.3030502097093,5.57170655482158));
#457=CARTESIAN_POINT('',(2.01072664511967,15.9237223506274,5.77401474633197));
#458=CARTESIAN_POINT('',(2.05923685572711,15.1647675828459,6.1787906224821));
#459=CARTESIAN_POINT('',(2.0744298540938,14.7851422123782,6.38125748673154));
#460=CARTESIAN_POINT('',(2.08416155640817,14.0257324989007,6.78627600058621));
#461=CARTESIAN_POINT('',(2.07870539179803,13.6459482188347,6.9888276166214));
#462=CARTESIAN_POINT('',(2.04530768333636,12.9207936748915,7.37557670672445));
#463=CARTESIAN_POINT('',(2.019400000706,12.5753539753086,7.55981121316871));
#464=CARTESIAN_POINT('',(1.94420775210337,11.8862238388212,7.92734728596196));
#465=CARTESIAN_POINT('',(1.89491264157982,11.5425342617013,8.11064839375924));
#466=CARTESIAN_POINT('',(1.76933257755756,10.8638627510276,8.47260653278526));
#467=CARTESIAN_POINT('',(1.69343525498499,10.5288262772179,8.65129265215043));
#468=CARTESIAN_POINT('',(1.50886816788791,9.86599885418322,9.00480061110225));
#469=CARTESIAN_POINT('',(1.40023644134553,9.53819996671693,9.17962668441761));
#470=CARTESIAN_POINT('',(1.18764458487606,9.00755677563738,9.46263638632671));
#471=CARTESIAN_POINT('',(1.09533945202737,8.80110836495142,9.57274220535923));
#472=CARTESIAN_POINT('',(0.941838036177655,8.4965707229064,9.73516228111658));
#473=CARTESIAN_POINT('',(0.887966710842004,8.39559901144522,9.78901386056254));
#474=CARTESIAN_POINT('',(0.774872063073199,8.1959587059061,9.89548869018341));
#475=CARTESIAN_POINT('',(0.715646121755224,8.09729126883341,9.94811132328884));
#476=CARTESIAN_POINT('',(0.653577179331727,7.99999995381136,10.0000000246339));
#477=CARTESIAN_POINT('',(0.587653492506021,7.91629095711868,10.0446444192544));
#478=CARTESIAN_POINT('',(0.52128663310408,7.83209582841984,10.0877567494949));
#479=CARTESIAN_POINT('',(0.38773100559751,7.6627156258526,10.170963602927));
#480=CARTESIAN_POINT('',(0.32054225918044,7.57753057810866,10.2110582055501));
#481=CARTESIAN_POINT('',(0.117863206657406,7.32049367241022,10.3268719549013));
#482=CARTESIAN_POINT('',(-0.0187678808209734,7.14712462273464,10.3981399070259));
#483=CARTESIAN_POINT('',(-0.225542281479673,6.88480528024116,10.4960292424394));
#484=CARTESIAN_POINT('',(-0.294778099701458,6.79697976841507,10.5271593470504));
#485=CARTESIAN_POINT('',(-0.433824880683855,6.62051441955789,10.586475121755));
#486=CARTESIAN_POINT('',(-0.503635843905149,6.53187458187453,10.61466078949));
#487=CARTESIAN_POINT('',(-0.64379446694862,6.35397342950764,10.6680496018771));
#488=CARTESIAN_POINT('',(-0.714142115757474,6.26471212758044,10.6932528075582));
#489=CARTESIAN_POINT('',(-0.819976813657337,6.13065917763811,10.7287530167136));
#490=CARTESIAN_POINT('',(-0.855307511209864,6.08594769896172,10.7402023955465));
#491=CARTESIAN_POINT('',(-0.926077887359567,5.99615003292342,10.7624179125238));
#492=CARTESIAN_POINT('',(-0.961517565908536,5.95106384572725,10.7731840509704));
#493=CARTESIAN_POINT('',(-1.05848261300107,5.82791495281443,10.8015435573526));
#494=CARTESIAN_POINT('',(-1.12013718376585,5.74984108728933,10.8183739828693));
#495=CARTESIAN_POINT('',(-1.24373637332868,5.5934610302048,10.8497959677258));
#496=CARTESIAN_POINT('',(-1.30568098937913,5.51515484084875,10.86438754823));
#497=CARTESIAN_POINT('',(-1.49185721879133,5.27994446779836,10.9047999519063));
#498=CARTESIAN_POINT('',(-1.61643858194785,5.1227391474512,10.9272605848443));
#499=CARTESIAN_POINT('',(-1.86579538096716,4.80760203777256,10.9632563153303));
#500=CARTESIAN_POINT('',(-1.9905705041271,4.64967111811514,10.9768001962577));
#501=CARTESIAN_POINT('',(-2.23992705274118,4.33290046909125,10.9950295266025));
#502=CARTESIAN_POINT('',(-2.36450851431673,4.17406094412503,10.999716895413));
#503=CARTESIAN_POINT('',(-2.49241480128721,4.00981580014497,10.9999958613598));
#504=CARTESIAN_POINT('',(-2.49621679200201,4.00493257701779,11.0000000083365));
#505=CARTESIAN_POINT('',(-2.50001832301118,4.0000488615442,11.0000000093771));
#506=B_SPLINE_CURVE_WITH_KNOTS('',3,(#445,#446,#447,#448,#449,#450,#451,#452,#453,#454,#455,
#456,#457,#458,#459,#460,#461,#462,#463,#464,#465,#466,#467,#468,#469,#470,#471,#472,#473,#474,
#475,#476,#477,#478,#479,#480,#481,#482,#483,#484,#485,#486,#487,#488,#489,#490,#491,#492,#493,
#494,#495,#496,#497,#498,#499,#500,#501,#502,#503,#504,#505),.UNSPECIFIED.,.F.,.F.,(4,2,2,2,2,2,
2,2,2,2,2,2,2,2,2,3,2,2,2,2,2,2,2,2,2,2,2,2,2,4),(0.,1.22226211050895,2.44471930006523,
3.67231286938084,4.89985154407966,6.19317848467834,7.48642775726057,8.77753311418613,
10.0683176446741,11.2448032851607,12.4218198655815,13.5823535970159,14.7415439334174,
15.4952992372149,15.8746140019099,16.2541152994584,16.6571757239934,17.0602255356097,
17.8661544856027,18.2691923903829,18.6722306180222,19.0752605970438,19.2767785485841,
19.4782964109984,19.827138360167,20.1759770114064,20.8736125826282,21.5705599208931,
22.2673561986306,22.288705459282),.UNSPECIFIED.);
#507=CARTESIAN_POINT('',(-2.49998385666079,4.00002709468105,11.0000000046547));
#508=VERTEX_POINT('',#507);
#509=EDGE_CURVE('E1382',#258,#508,#506,.T.);
#510=ORIENTED_EDGE('',*,*,#509,.T.);
#511=CARTESIAN_POINT('',(-2.50001834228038,4.0000488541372,11.));
#512=CARTESIAN_POINT('',(-2.50001833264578,4.00004887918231,11.0000000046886));
#513=CARTESIAN_POINT('',(-2.50001832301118,4.00004890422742,11.0000000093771));
#514=CARTESIAN_POINT('',(-2.50442683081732,3.9946562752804,11.0000000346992));
#515=CARTESIAN_POINT('',(-2.50367027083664,3.99419809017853,11.0000000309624));
#516=CARTESIAN_POINT('',(-2.5029137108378,3.99373990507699,11.000000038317));
#517=CARTESIAN_POINT('',(-2.50884245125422,3.98926660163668,10.9999927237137));
#518=CARTESIAN_POINT('',(-2.50732863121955,3.9883498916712,10.9999940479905));
#519=CARTESIAN_POINT('',(-2.50581480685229,3.98743318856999,10.9999930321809));
#520=CARTESIAN_POINT('',(-2.52939303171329,3.96422209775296,10.9999246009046));
#521=CARTESIAN_POINT('',(-2.52435664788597,3.96117294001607,10.9999383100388));
#522=CARTESIAN_POINT('',(-2.51932016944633,3.95812392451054,10.9999277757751));
#523=CARTESIAN_POINT('',(-2.5455919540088,3.9445935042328,10.9997733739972));
#524=CARTESIAN_POINT('',(-2.5377840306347,3.93986784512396,10.9998145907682));
#525=CARTESIAN_POINT('',(-2.52997566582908,3.93514284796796,10.9997829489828));
#526=CARTESIAN_POINT('',(-2.57794004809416,3.90531773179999,10.9992756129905));
#527=CARTESIAN_POINT('',(-2.56459447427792,3.89724500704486,10.9994073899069));
#528=CARTESIAN_POINT('',(-2.55124718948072,3.88917466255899,10.9993064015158));
#529=CARTESIAN_POINT('',(-2.59408921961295,3.88567055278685,10.998929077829));
#530=CARTESIAN_POINT('',(-2.57797774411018,3.87592692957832,10.999123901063));
#531=CARTESIAN_POINT('',(-2.56186321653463,3.86618755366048,10.9989746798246));
#532=CARTESIAN_POINT('',(-2.64253116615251,3.82673093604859,10.9975967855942));
#533=CARTESIAN_POINT('',(-2.6181247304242,3.81197627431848,10.9980340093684));
#534=CARTESIAN_POINT('',(-2.59370775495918,3.79723634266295,10.9976996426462));
#535=CARTESIAN_POINT('',(-2.6748179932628,3.78744088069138,10.9963183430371));
#536=CARTESIAN_POINT('',(-2.644885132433,3.76934805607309,10.9969881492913));
#537=CARTESIAN_POINT('',(-2.61493247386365,3.75128289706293,10.9964764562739));
#538=CARTESIAN_POINT('',(-2.77161142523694,3.66957370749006,10.9913139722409));
#539=CARTESIAN_POINT('',(-2.72512219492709,3.64145850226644,10.9928936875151));
#540=CARTESIAN_POINT('',(-2.67855973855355,3.61344583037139,10.9916893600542));
#541=CARTESIAN_POINT('',(-2.83604806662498,3.59100312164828,10.9864190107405));
#542=CARTESIAN_POINT('',(-2.77855153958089,3.55619726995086,10.9888876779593));
#543=CARTESIAN_POINT('',(-2.72091347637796,3.52158962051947,10.9870079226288));
#544=CARTESIAN_POINT('',(-2.96478425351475,3.43396527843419,10.973514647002));
#545=CARTESIAN_POINT('',(-2.88534245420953,3.38572967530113,10.9783228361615));
#546=CARTESIAN_POINT('',(-2.80554632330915,3.33798011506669,10.9746660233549));
#547=CARTESIAN_POINT('',(-3.02908375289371,3.35549805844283,10.965504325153));
#548=CARTESIAN_POINT('',(-2.93871719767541,3.3005022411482,10.9717606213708));
#549=CARTESIAN_POINT('',(-2.84782540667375,3.2462268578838,10.9670046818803));
#550=CARTESIAN_POINT('',(-3.12541422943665,3.23796464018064,10.9511519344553));
#551=CARTESIAN_POINT('',(-3.01872544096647,3.17273164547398,10.9599939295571));
#552=CARTESIAN_POINT('',(-2.91119122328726,3.10864555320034,10.9532566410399));
#553=CARTESIAN_POINT('',(-3.15750464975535,3.19881466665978,10.9459783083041));
#554=CARTESIAN_POINT('',(-3.04539608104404,3.13013690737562,10.9557492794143));
#555=CARTESIAN_POINT('',(-2.93230439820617,3.06279313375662,10.9482979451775));
#556=CARTESIAN_POINT('',(-3.22164495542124,3.12058074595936,10.9348512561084));
#557=CARTESIAN_POINT('',(-3.09872929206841,3.04501991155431,10.9466177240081));
#558=CARTESIAN_POINT('',(-2.974514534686,2.97122138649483,10.9376389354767));
#559=CARTESIAN_POINT('',(-3.25369484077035,3.0814967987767,10.9288978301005));
#560=CARTESIAN_POINT('',(-3.12539347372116,3.00249510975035,10.9417302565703));
#561=CARTESIAN_POINT('',(-2.9956114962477,2.92550205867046,10.9319386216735));
#562=CARTESIAN_POINT('',(-3.34980730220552,2.96424689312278,10.9098582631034));
#563=CARTESIAN_POINT('',(-3.20541660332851,2.87482912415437,10.9260875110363));
#564=CARTESIAN_POINT('',(-3.0588893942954,2.78831869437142,10.9137029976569));
#565=CARTESIAN_POINT('',(-3.41375779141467,2.88617409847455,10.8956039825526));
#566=CARTESIAN_POINT('',(-3.2587130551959,2.78974463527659,10.9143650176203));
#567=CARTESIAN_POINT('',(-3.10100807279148,2.69693592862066,10.9000436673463));
#568=CARTESIAN_POINT('',(-3.54137559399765,2.73038471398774,10.8639793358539));
#569=CARTESIAN_POINT('',(-3.36520843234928,2.61976410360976,10.8883235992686));
#570=CARTESIAN_POINT('',(-3.18511008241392,2.51449013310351,10.8697114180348));
#571=CARTESIAN_POINT('',(-3.6050429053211,2.65266812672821,10.8466089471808));
#572=CARTESIAN_POINT('',(-3.41842024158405,2.53484753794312,10.8739981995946));
#573=CARTESIAN_POINT('',(-3.22709341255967,2.42342710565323,10.8530384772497));
#574=CARTESIAN_POINT('',(-3.73199846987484,2.49765440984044,10.808762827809));
#575=CARTESIAN_POINT('',(-3.52469191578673,2.36529155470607,10.8427424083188));
#576=CARTESIAN_POINT('',(-3.31086549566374,2.24179839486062,10.816699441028));
#577=CARTESIAN_POINT('',(-3.79528676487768,2.42035723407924,10.7882874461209));
#578=CARTESIAN_POINT('',(-3.57776419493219,2.28063237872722,10.8258046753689));
#579=CARTESIAN_POINT('',(-3.35265426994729,2.15123265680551,10.7970336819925));
#580=CARTESIAN_POINT('',(-3.88987657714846,2.30476898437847,10.7552545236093));
#581=CARTESIAN_POINT('',(-3.65719359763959,2.15397450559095,10.7984503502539));
#582=CARTESIAN_POINT('',(-3.41515651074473,2.01589314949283,10.7653169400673));
#583=CARTESIAN_POINT('',(-3.92134964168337,2.26629886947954,10.7438568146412));
#584=CARTESIAN_POINT('',(-3.68365987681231,2.11177905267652,10.7889999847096));
#585=CARTESIAN_POINT('',(-3.43596059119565,1.97086449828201,10.7543749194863));
#586=CARTESIAN_POINT('',(-3.984140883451,2.18947016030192,10.7202968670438));
#587=CARTESIAN_POINT('',(-3.73651112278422,2.02753585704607,10.7694568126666));
#588=CARTESIAN_POINT('',(-3.4774774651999,1.88110092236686,10.731796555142));
#589=CARTESIAN_POINT('',(-4.01545906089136,2.15111156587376,10.7081346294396));
#590=CARTESIAN_POINT('',(-3.76289732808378,1.98548615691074,10.759362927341));
#591=CARTESIAN_POINT('',(-3.4981902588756,1.83636599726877,10.7201602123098));
#592=CARTESIAN_POINT('',(-4.10029313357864,2.0471328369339,10.6740732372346));
#593=CARTESIAN_POINT('',(-3.83447295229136,1.87127190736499,10.7310456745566));
#594=CARTESIAN_POINT('',(-3.55431581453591,1.71490579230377,10.6875123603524));
#595=CARTESIAN_POINT('',(-4.15366642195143,1.98163465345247,10.651430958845));
#596=CARTESIAN_POINT('',(-3.8795777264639,1.79913491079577,10.7121827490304));
#597=CARTESIAN_POINT('',(-3.58964794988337,1.63818174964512,10.6657474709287));
#598=CARTESIAN_POINT('',(-4.26000694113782,1.85108948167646,10.6038889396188));
#599=CARTESIAN_POINT('',(-3.9696257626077,1.65506572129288,10.6724925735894));
#600=CARTESIAN_POINT('',(-3.66009913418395,1.48510070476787,10.6199765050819));
#601=CARTESIAN_POINT('',(-4.3129741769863,1.78604248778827,10.5789892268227));
#602=CARTESIAN_POINT('',(-4.01457633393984,1.58312173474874,10.6516583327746));
#603=CARTESIAN_POINT('',(-3.69521818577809,1.40874369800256,10.5959704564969));
#604=CARTESIAN_POINT('',(-4.47125122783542,1.59167319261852,10.5009019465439));
#605=CARTESIAN_POINT('',(-4.14933641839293,1.36746285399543,10.586104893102));
#606=CARTESIAN_POINT('',(-3.8002576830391,1.18035953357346,10.5205744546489));
#607=CARTESIAN_POINT('',(-4.57595103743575,1.46310458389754,10.4443203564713));
#608=CARTESIAN_POINT('',(-4.23883566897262,1.22427113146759,10.5384166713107));
#609=CARTESIAN_POINT('',(-3.86987015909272,1.02899816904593,10.4658010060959));
#610=CARTESIAN_POINT('',(-4.78326077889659,1.20853499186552,10.3222309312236));
#611=CARTESIAN_POINT('',(-4.41694101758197,0.939685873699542,10.435034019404));
#612=CARTESIAN_POINT('',(-4.00799053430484,0.729255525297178,10.3474539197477));
#613=CARTESIAN_POINT('',(-4.88587300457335,1.08253119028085,10.2567335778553));
#614=CARTESIAN_POINT('',(-4.50559804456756,0.798212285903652,10.3792796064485));
#615=CARTESIAN_POINT('',(-4.07649962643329,0.580870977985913,10.2838906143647));
#616=CARTESIAN_POINT('',(-5.08863801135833,0.833182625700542,10.1169044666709));
#617=CARTESIAN_POINT('',(-4.68177979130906,0.517271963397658,10.2596711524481));
#618=CARTESIAN_POINT('',(-4.21214847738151,0.287611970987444,10.1482468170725));
#619=CARTESIAN_POINT('',(-5.18879038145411,0.709838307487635,10.0425712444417));
#620=CARTESIAN_POINT('',(-4.76934270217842,0.377745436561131,10.1957423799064));
#621=CARTESIAN_POINT('',(-4.27928800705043,0.142738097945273,10.0761649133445));
#622=CARTESIAN_POINT('',(-5.28744814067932,0.587967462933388,9.9639020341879));
#623=CARTESIAN_POINT('',(-4.85586563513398,0.239889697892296,10.1279411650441));
#624=CARTESIAN_POINT('',(-4.34555745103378,4.14872069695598E-08,10.0000000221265));
#625=CARTESIAN_POINT('',(-5.35053609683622,0.510002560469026,9.91358640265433));
#626=CARTESIAN_POINT('',(-4.91058482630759,0.1639389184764,10.0874340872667));
#627=CARTESIAN_POINT('',(-4.38793037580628,-0.0701967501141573,9.96256173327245));
#628=CARTESIAN_POINT('',(-5.41058808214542,0.431213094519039,9.8625536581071));
#629=CARTESIAN_POINT('',(-4.96262941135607,0.0870406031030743,10.0464216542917));
#630=CARTESIAN_POINT('',(-4.42794492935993,-0.141472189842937,9.9245481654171));
#631=CARTESIAN_POINT('',(-5.52493820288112,0.272510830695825,9.75944471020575));
#632=CARTESIAN_POINT('',(-5.06178206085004,-0.0682417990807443,9.96360437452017));
#633=CARTESIAN_POINT('',(-4.50353286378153,-0.285638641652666,9.84765939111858));
#634=CARTESIAN_POINT('',(-5.57924926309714,0.192601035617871,9.70737117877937));
#635=CARTESIAN_POINT('',(-5.10889668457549,-0.14663539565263,9.9217944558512));
#636=CARTESIAN_POINT('',(-4.53911625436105,-0.358525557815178,9.80878636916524));
#637=CARTESIAN_POINT('',(-5.68271426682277,0.031833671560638,9.6023450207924));
#638=CARTESIAN_POINT('',(-5.19871683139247,-0.304699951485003,9.8374933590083));
#639=CARTESIAN_POINT('',(-4.6063041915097,-0.505689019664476,9.73029918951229));
#640=CARTESIAN_POINT('',(-5.73186896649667,-0.0490237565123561,9.54939252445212));
#641=CARTESIAN_POINT('',(-5.2414171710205,-0.384381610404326,9.79499647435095));
#642=CARTESIAN_POINT('',(-4.63790932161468,-0.579965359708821,9.69068514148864));
#643=CARTESIAN_POINT('',(-5.82554381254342,-0.211650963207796,9.44266855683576));
#644=CARTESIAN_POINT('',(-5.322868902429,-0.544964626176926,9.70935219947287));
#645=CARTESIAN_POINT('',(-4.69753635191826,-0.72982463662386,9.61076019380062));
#646=CARTESIAN_POINT('',(-5.87005301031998,-0.293422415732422,9.38889547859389));
#647=CARTESIAN_POINT('',(-5.36160426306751,-0.625877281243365,9.66619878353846));
#648=CARTESIAN_POINT('',(-4.72554982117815,-0.805410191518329,9.5704478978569));
#649=CARTESIAN_POINT('',(-5.91238423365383,-0.375440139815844,9.33486866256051));
#650=CARTESIAN_POINT('',(-5.39844162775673,-0.707073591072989,9.62289408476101));
#651=CARTESIAN_POINT('',(-4.75189044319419,-0.881431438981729,9.52990323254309));
#652=(BOUNDED_SURFACE() B_SPLINE_SURFACE(3,2,((#511,#512,#513),(#514,#515,#516),(#517,#518,
#519),(#520,#521,#522),(#523,#524,#525),(#526,#527,#528),(#529,#530,#531),(#532,#533,#534),
(#535,#536,#537),(#538,#539,#540),(#541,#542,#543),(#544,#545,#546),(#547,#548,#549),(#550,#551,
#552),(#553,#554,#555),(#556,#557,#558),(#559,#560,#561),(#562,#563,#564),(#565,#566,#567),
(#568,#569,#570),(#571,#572,#573),(#574,#575,#576),(#577,#578,#579),(#580,#581,#582),(#583,#584,
#585),(#586,#587,#588),(#589,#590,#591),(#592,#593,#594),(#595,#596,#597),(#598,#599,#600),
(#601,#602,#603),(#604,#605,#606),(#607,#608,#609),(#610,#611,#612),(#613,#614,#615),(#616,#617,
#618),(#619,#620,#621),(#622,#623,#624),(#625,#626,#627),(#628,#629,#630),(#631,#632,#633),
(#634,#635,#636),(#637,#638,#639),(#640,#641,#642),(#643,#644,#645),(#646,#647,#648),(#649,#650,
#651)),.UNSPECIFIED.,.F.,.F.,.F.) B_SPLINE_SURFACE_WITH_KNOTS((4,2,2,2,2,2,2,2,2,2,2,2,2,2,2,2,
2,2,3,2,2,2,4),(3,3),(0.,0.0168816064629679,0.0784757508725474,0.140070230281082,
0.263260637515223,0.509652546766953,0.756117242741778,0.879350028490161,1.00258280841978,
1.24933533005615,1.49608963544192,1.74281622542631,1.86618135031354,1.98954630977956,
2.20113545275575,2.41272196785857,2.83583713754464,3.25845910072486,3.68115120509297,
3.95148041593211,4.22118744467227,4.49085486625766,4.76114413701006),(0.,1.),
.UNSPECIFIED.) GEOMETRIC_REPRESENTATION_ITEM() RATIONAL_B_SPLINE_SURFACE(((1.,1.,1.),(1.,
1.00000000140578,1.),(1.,0.999999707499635,1.),(1.,0.999996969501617,1.),(1.,0.999990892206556,
1.),(1.,0.999970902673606,1.),(1.,0.999956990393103,1.),(1.,0.999903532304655,1.),(1.,
0.999852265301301,1.),(1.,0.999651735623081,1.),(1.,0.999455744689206,1.),(1.,0.998939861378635,
1.),(1.,0.998619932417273,1.),(1.,0.998046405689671,1.),(1.,0.997839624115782,1.),(1.,
0.997395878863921,1.),(1.,0.997158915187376,1.),(1.,0.996401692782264,1.),(1.,0.995835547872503,
1.),(1.,0.994581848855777,1.),(1.,0.993894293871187,1.),(1.,0.992401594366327,1.),(1.,
0.991596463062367,1.),(1.,0.990304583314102,1.),(1.,0.98985992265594,1.),(1.,0.988946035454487,
1.),(1.,0.988476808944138,1.),(1.,0.987161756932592,1.),(1.,0.986286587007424,1.),(1.,
0.984453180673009,1.),(1.,0.983494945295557,1.),(1.,0.980498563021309,1.),(1.,0.978338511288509,
1.),(1.,0.973730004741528,1.),(1.,0.971281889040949,1.),(1.,0.96614152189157,1.),(1.,
0.963449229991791,1.),(1.,0.960658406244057,1.),(1.,0.959655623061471,1.),(1.,0.958619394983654,
1.),(1.,0.956492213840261,1.),(1.,0.955401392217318,1.),(1.,0.953172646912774,1.),(1.,
0.952034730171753,1.),(1.,0.949716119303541,1.),(1.,0.948535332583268,1.),(1.,0.947337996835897,1.))) REPRESENTATION_ITEM('') SURFACE());
#653=CARTESIAN_POINT('',(-2.50001832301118,4.00004890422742,11.0000000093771));
#654=CARTESIAN_POINT('',(-2.5029137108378,3.99373990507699,11.000000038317));
#655=CARTESIAN_POINT('',(-2.50581480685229,3.98743318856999,10.9999930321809));
#656=CARTESIAN_POINT('',(-2.51932016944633,3.95812392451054,10.9999277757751));
#657=CARTESIAN_POINT('',(-2.52997566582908,3.93514284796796,10.9997829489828));
#658=CARTESIAN_POINT('',(-2.55124718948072,3.88917466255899,10.9993064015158));
#659=CARTESIAN_POINT('',(-2.56186321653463,3.86618755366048,10.9989746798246));
#660=CARTESIAN_POINT('',(-2.59370775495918,3.79723634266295,10.9976996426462));
#661=CARTESIAN_POINT('',(-2.61493247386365,3.75128289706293,10.9964764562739));
#662=CARTESIAN_POINT('',(-2.67855973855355,3.61344583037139,10.9916893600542));
#663=CARTESIAN_POINT('',(-2.72091347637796,3.52158962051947,10.9870079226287));
#664=CARTESIAN_POINT('',(-2.80554632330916,3.33798011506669,10.9746660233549));
#665=CARTESIAN_POINT('',(-2.84782540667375,3.2462268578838,10.9670046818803));
#666=CARTESIAN_POINT('',(-2.91119122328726,3.10864555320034,10.9532566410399));
#667=CARTESIAN_POINT('',(-2.93230439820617,3.06279313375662,10.9482979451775));
#668=CARTESIAN_POINT('',(-2.974514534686,2.97122138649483,10.9376389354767));
#669=CARTESIAN_POINT('',(-2.9956114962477,2.92550205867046,10.9319386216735));
#670=CARTESIAN_POINT('',(-3.0588893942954,2.78831869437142,10.9137029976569));
#671=CARTESIAN_POINT('',(-3.10100807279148,2.69693592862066,10.9000436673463));
#672=CARTESIAN_POINT('',(-3.18511008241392,2.51449013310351,10.8697114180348));
#673=CARTESIAN_POINT('',(-3.22709341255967,2.42342710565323,10.8530384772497));
#674=CARTESIAN_POINT('',(-3.31086549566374,2.24179839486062,10.816699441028));
#675=CARTESIAN_POINT('',(-3.35265426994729,2.15123265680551,10.7970336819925));
#676=CARTESIAN_POINT('',(-3.41515651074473,2.01589314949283,10.7653169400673));
#677=CARTESIAN_POINT('',(-3.43596059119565,1.97086449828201,10.7543749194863));
#678=CARTESIAN_POINT('',(-3.4774774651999,1.88110092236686,10.731796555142));
#679=CARTESIAN_POINT('',(-3.4981902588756,1.83636599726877,10.7201602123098));
#680=CARTESIAN_POINT('',(-3.55431581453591,1.71490579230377,10.6875123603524));
#681=CARTESIAN_POINT('',(-3.58964794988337,1.63818174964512,10.6657474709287));
#682=CARTESIAN_POINT('',(-3.66009913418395,1.48510070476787,10.6199765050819));
#683=CARTESIAN_POINT('',(-3.69521818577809,1.40874369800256,10.5959704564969));
#684=CARTESIAN_POINT('',(-3.8002576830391,1.18035953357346,10.5205744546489));
#685=CARTESIAN_POINT('',(-3.86987015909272,1.02899816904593,10.4658010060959));
#686=CARTESIAN_POINT('',(-4.00799053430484,0.729255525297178,10.3474539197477));
#687=CARTESIAN_POINT('',(-4.07649962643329,0.580870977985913,10.2838906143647));
#688=CARTESIAN_POINT('',(-4.21214847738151,0.287611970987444,10.1482468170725));
#689=CARTESIAN_POINT('',(-4.27928800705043,0.142738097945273,10.0761649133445));
#690=CARTESIAN_POINT('',(-4.34555745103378,4.14872069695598E-08,10.0000000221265));
#691=CARTESIAN_POINT('',(-4.38793037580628,-0.0701967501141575,9.96256173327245));
#692=CARTESIAN_POINT('',(-4.42794492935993,-0.141472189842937,9.9245481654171));
#693=CARTESIAN_POINT('',(-4.50353286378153,-0.285638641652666,9.84765939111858));
#694=CARTESIAN_POINT('',(-4.53911625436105,-0.358525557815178,9.80878636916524));
#695=CARTESIAN_POINT('',(-4.6063041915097,-0.505689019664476,9.73029918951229));
#696=CARTESIAN_POINT('',(-4.63790932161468,-0.579965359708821,9.69068514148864));
#697=CARTESIAN_POINT('',(-4.69753635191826,-0.72982463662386,9.61076019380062));
#698=CARTESIAN_POINT('',(-4.72554982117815,-0.805410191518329,9.5704478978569));
#699=CARTESIAN_POINT('',(-4.75189044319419,-0.881431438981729,9.52990323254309));
#700=B_SPLINE_CURVE_WITH_KNOTS('',3,(#653,#654,#655,#656,#657,#658,#659,#660,#661,#662,#663,
#664,#665,#666,#667,#668,#669,#670,#671,#672,#673,#674,#675,#676,#677,#678,#679,#680,#681,#682,
#683,#684,#685,#686,#687,#688,#689,#690,#691,#692,#693,#694,#695,#696,#697,#698,#699),
.UNSPECIFIED.,.F.,.F.,(4,2,2,2,2,2,2,2,2,2,2,2,2,2,2,2,2,2,3,2,2,2,4),(0.,0.0168816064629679,
0.0784757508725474,0.140070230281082,0.263260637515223,0.509652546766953,0.756117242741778,
0.879350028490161,1.00258280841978,1.24933533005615,1.49608963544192,1.74281622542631,
1.86618135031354,1.98954630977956,2.20113545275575,2.41272196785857,2.83583713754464,
3.25845910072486,3.68115120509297,3.95148041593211,4.22118744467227,4.49085486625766,
4.76114413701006),.UNSPECIFIED.);
#701=CARTESIAN_POINT('',(-4.290811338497,0.117999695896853,10.0617679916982));
#702=VERTEX_POINT('',#701);
#703=EDGE_CURVE('E1093',#508,#702,#700,.T.);
#704=ORIENTED_EDGE('',*,*,#703,.T.);
#705=CARTESIAN_POINT('',(-4.77009977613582,0.367997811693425,10.1850771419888));
#706=CARTESIAN_POINT('',(-4.72736787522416,0.33773303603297,10.1707590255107));
#707=CARTESIAN_POINT('',(-4.68335378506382,0.30907063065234,10.1569805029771));
#708=CARTESIAN_POINT('',(-4.59289570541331,0.255137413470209,10.1307228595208));
#709=CARTESIAN_POINT('',(-4.54645050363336,0.229868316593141,10.1182443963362));
#710=CARTESIAN_POINT('',(-4.40648141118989,0.160828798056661,10.0837864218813));
#711=CARTESIAN_POINT('',(-4.30983552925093,0.122061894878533,10.0639341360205));
#712=CARTESIAN_POINT('',(-4.1631520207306,0.0762309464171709,10.0401868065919));
#713=CARTESIAN_POINT('',(-4.11533662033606,0.0632168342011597,10.0333907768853));
#714=CARTESIAN_POINT('',(-4.01864507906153,0.0407346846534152,10.0215963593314));
#715=CARTESIAN_POINT('',(-3.96976896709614,0.0312665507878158,10.0165979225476));
#716=CARTESIAN_POINT('',(-3.86996533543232,0.0157876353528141,10.0084045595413));
#717=CARTESIAN_POINT('',(-3.819018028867,0.00987690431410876,10.0052618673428));
#718=CARTESIAN_POINT('',(-3.7167155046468,0.00197829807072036,10.001054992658));
#719=CARTESIAN_POINT('',(-3.6653601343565,-8.03245554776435E-06,9.99999162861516));
#720=CARTESIAN_POINT('',(-3.61399906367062,0.,10.));
#721=B_SPLINE_CURVE_WITH_KNOTS('',3,(#705,#706,#707,#708,#709,#710,#711,#712,#713,#714,#715,
#716,#717,#718,#719,#720),.UNSPECIFIED.,.F.,.F.,(4,2,2,2,2,2,2,4),(0.,0.162758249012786,
0.325598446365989,0.641883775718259,0.791811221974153,0.941734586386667,1.09569831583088,
1.2497226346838),.UNSPECIFIED.);
#722=CARTESIAN_POINT('',(-3.61399906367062,0.,10.));
#723=VERTEX_POINT('',#722);
#724=EDGE_CURVE('E1374',#702,#723,#721,.T.);
#725=ORIENTED_EDGE('',*,*,#724,.T.);
#726=DIRECTION('',(1.,0.,0.));
#727=VECTOR('',#726,1.);
#728=CARTESIAN_POINT('',(-5.,0.,10.));
#729=LINE('',#728,#727);
#730=CARTESIAN_POINT('',(3.61399906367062,0.,10.));
#731=VERTEX_POINT('',#730);
#732=EDGE_CURVE('E1325',#723,#731,#729,.T.);
#733=ORIENTED_EDGE('',*,*,#732,.T.);
#734=CARTESIAN_POINT('',(3.61399906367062,0.,10.));
#735=CARTESIAN_POINT('',(3.66679580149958,-9.03586644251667E-06,9.99999061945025));
#736=CARTESIAN_POINT('',(3.71958627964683,0.00209039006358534,10.0011147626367));
#737=CARTESIAN_POINT('',(3.82472451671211,0.0104359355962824,10.0055593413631));
#738=CARTESIAN_POINT('',(3.87707244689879,0.0166803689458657,10.0088788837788));
#739=CARTESIAN_POINT('',(3.97954272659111,0.0330231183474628,10.0175257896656));
#740=CARTESIAN_POINT('',(4.02968707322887,0.0430133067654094,10.0227967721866));
#741=CARTESIAN_POINT('',(4.1288285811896,0.0667248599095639,10.0352247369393));
#742=CARTESIAN_POINT('',(4.17782574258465,0.0804462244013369,10.0423817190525));
#743=CARTESIAN_POINT('',(4.32275705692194,0.127050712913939,10.0664908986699));
#744=CARTESIAN_POINT('',(4.41659604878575,0.165368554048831,10.0860782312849));
#745=CARTESIAN_POINT('',(4.55257548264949,0.233151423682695,10.1198680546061));
#746=CARTESIAN_POINT('',(4.59769329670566,0.257880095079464,10.1320667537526));
#747=CARTESIAN_POINT('',(4.6856219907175,0.310550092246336,10.1576914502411));
#748=CARTESIAN_POINT('',(4.72843383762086,0.338490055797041,10.1711169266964));
#749=CARTESIAN_POINT('',(4.77002977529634,0.367948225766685,10.1850536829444));
#750=B_SPLINE_CURVE_WITH_KNOTS('',3,(#734,#735,#736,#737,#738,#739,#740,#741,#742,#743,#744,
#745,#746,#747,#748,#749),.UNSPECIFIED.,.F.,.F.,(4,2,2,2,2,2,2,4),(0.,0.158326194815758,
0.316588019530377,0.470594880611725,0.624601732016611,0.932720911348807,1.09122117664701,
1.24965445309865),.UNSPECIFIED.);
#751=CARTESIAN_POINT('',(4.29081722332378,0.118001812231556,10.0617690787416));
#752=VERTEX_POINT('',#751);
#753=EDGE_CURVE('E1344',#731,#752,#750,.T.);
#754=ORIENTED_EDGE('',*,*,#753,.T.);
#755=CARTESIAN_POINT('',(2.49997175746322,4.00004890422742,11.0000000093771));
#756=CARTESIAN_POINT('',(2.49997177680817,4.00004887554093,11.0000000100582));
#757=CARTESIAN_POINT('',(2.49997179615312,4.00004884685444,11.0000000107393));
#758=CARTESIAN_POINT('',(2.50290452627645,3.99377153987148,11.0000000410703));
#759=CARTESIAN_POINT('',(2.50365040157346,3.99423035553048,11.0000000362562));
#760=CARTESIAN_POINT('',(2.50439627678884,3.99468917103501,11.000000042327));
#761=CARTESIAN_POINT('',(2.50583956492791,3.98749484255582,10.9999931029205));
#762=CARTESIAN_POINT('',(2.50733199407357,3.9884125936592,10.9999941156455));
#763=CARTESIAN_POINT('',(2.508824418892,3.98933035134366,10.9999928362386));
#764=CARTESIAN_POINT('',(2.5279941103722,3.94014874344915,10.9998881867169));
#765=CARTESIAN_POINT('',(2.53512318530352,3.94452880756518,10.9999045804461));
#766=CARTESIAN_POINT('',(2.54225202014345,3.94890923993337,10.9998838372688));
#767=CARTESIAN_POINT('',(2.54728722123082,3.89910089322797,10.9994987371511));
#768=CARTESIAN_POINT('',(2.55933317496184,3.90648531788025,10.9995722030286));
#769=CARTESIAN_POINT('',(2.57137730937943,3.91387252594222,10.9994791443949));
#770=CARTESIAN_POINT('',(2.58573870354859,3.81696373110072,10.998123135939));
#771=CARTESIAN_POINT('',(2.60763327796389,3.83033347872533,10.998397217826));
#772=CARTESIAN_POINT('',(2.62952019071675,3.84371394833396,10.9980466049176));
#773=CARTESIAN_POINT('',(2.60489707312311,3.77587441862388,10.9971369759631));
#774=CARTESIAN_POINT('',(2.63172458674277,3.79222322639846,10.9975545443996));
#775=CARTESIAN_POINT('',(2.65853778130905,3.80859208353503,10.9970187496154));
#776=CARTESIAN_POINT('',(2.66228820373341,3.65257785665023,10.9932824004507));
#777=CARTESIAN_POINT('',(2.70395081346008,3.67783806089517,10.9942592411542));
#778=CARTESIAN_POINT('',(2.74556067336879,3.7031722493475,10.992996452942));
#779=CARTESIAN_POINT('',(2.70043572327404,3.57034467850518,10.9895178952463));
#780=CARTESIAN_POINT('',(2.75203591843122,3.60151201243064,10.9910389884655));
#781=CARTESIAN_POINT('',(2.80353418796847,3.63282234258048,10.9890632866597));
#782=CARTESIAN_POINT('',(2.77650817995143,3.40585123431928,10.979594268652));
#783=CARTESIAN_POINT('',(2.84804031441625,3.44877973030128,10.9825438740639));
#784=CARTESIAN_POINT('',(2.91931674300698,3.49205912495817,10.9786785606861));
#785=CARTESIAN_POINT('',(2.81443306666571,3.3235909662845,10.9734346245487));
#786=CARTESIAN_POINT('',(2.8959691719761,3.37235805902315,10.977266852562));
#787=CARTESIAN_POINT('',(2.97712574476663,3.42164580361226,10.9722264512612));
#788=CARTESIAN_POINT('',(2.89013542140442,3.15902704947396,10.9586918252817));
#789=CARTESIAN_POINT('',(2.99171798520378,3.21947455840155,10.9646424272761));
#790=CARTESIAN_POINT('',(3.09258115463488,3.28090200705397,10.9567953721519));
#791=CARTESIAN_POINT('',(2.927912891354,3.07672340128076,10.9501087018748));
#792=CARTESIAN_POINT('',(3.03954766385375,3.14299707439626,10.9572924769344));
#793=CARTESIAN_POINT('',(3.15022756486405,3.21057153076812,10.9478164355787));
#794=CARTESIAN_POINT('',(3.00337205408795,2.9123579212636,10.9305368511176));
#795=CARTESIAN_POINT('',(3.13513387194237,2.99013032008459,10.9405114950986));
#796=CARTESIAN_POINT('',(3.26534203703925,3.07001268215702,10.9273267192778));
#797=CARTESIAN_POINT('',(3.04105360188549,2.83029644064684,10.9195455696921));
#798=CARTESIAN_POINT('',(3.18289955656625,2.91372635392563,10.9310748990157));
#799=CARTESIAN_POINT('',(3.32280984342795,2.99978449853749,10.9158132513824));
#800=CARTESIAN_POINT('',(3.11627423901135,2.66629920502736,10.8951329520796));
#801=CARTESIAN_POINT('',(3.27827449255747,2.76100316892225,10.9101175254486));
#802=CARTESIAN_POINT('',(3.43741220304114,2.85958905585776,10.8902830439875));
#803=CARTESIAN_POINT('',(3.15381332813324,2.58436345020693,10.8817116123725));
#804=CARTESIAN_POINT('',(3.32589301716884,2.68466893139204,10.8985925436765));
#805=CARTESIAN_POINT('',(3.49454675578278,2.78962179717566,10.8762663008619));
#806=CARTESIAN_POINT('',(3.22879852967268,2.42085644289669,10.8524531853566));
#807=CARTESIAN_POINT('',(3.42099528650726,2.53224208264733,10.8734559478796));
#808=CARTESIAN_POINT('',(3.60844570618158,2.65006719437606,10.8457593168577));
#809=CARTESIAN_POINT('',(3.26624464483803,2.33928517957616,10.8366161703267));
#810=CARTESIAN_POINT('',(3.46848784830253,2.45613537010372,10.859839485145));
#811=CARTESIAN_POINT('',(3.66521011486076,2.58047983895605,10.8292691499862));
#812=CARTESIAN_POINT('',(3.32234144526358,2.21727587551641,10.811063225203));
#813=CARTESIAN_POINT('',(3.53959791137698,2.34224199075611,10.8378600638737));
#814=CARTESIAN_POINT('',(3.75005450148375,2.47643208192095,10.8027025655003));
#815=CARTESIAN_POINT('',(3.34102853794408,2.17666355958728,10.802245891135));
#816=CARTESIAN_POINT('',(3.56329412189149,2.304299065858,10.8302694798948));
#817=CARTESIAN_POINT('',(3.77828592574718,2.44180463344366,10.793541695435));
#818=CARTESIAN_POINT('',(3.37837935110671,2.09559801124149,10.7840233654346));
#819=CARTESIAN_POINT('',(3.61061737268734,2.22852470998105,10.8145730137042));
#820=CARTESIAN_POINT('',(3.83457597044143,2.37269409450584,10.774634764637));
#821=CARTESIAN_POINT('',(3.39704307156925,2.0551447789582,10.7746181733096));
#822=CARTESIAN_POINT('',(3.6342452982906,2.19069186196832,10.806466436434));
#823=CARTESIAN_POINT('',(3.86263459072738,2.33821100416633,10.7648887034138));
#824=CARTESIAN_POINT('',(3.42534685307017,1.99380406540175,10.7598814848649));
#825=CARTESIAN_POINT('',(3.67014225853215,2.13329710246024,10.79376187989));
#826=CARTESIAN_POINT('',(3.9052735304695,2.28592167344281,10.7496029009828));
#827=CARTESIAN_POINT('',(3.43499672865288,1.97289186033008,10.7547735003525));
#828=CARTESIAN_POINT('',(3.68239623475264,2.11371920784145,10.7893563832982));
#829=CARTESIAN_POINT('',(3.91982631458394,2.26809501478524,10.7443020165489));
#830=CARTESIAN_POINT('',(3.45428137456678,1.93122472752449,10.74443069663));
#831=CARTESIAN_POINT('',(3.70688754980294,2.07464656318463,10.780412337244));
#832=CARTESIAN_POINT('',(3.94889779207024,2.23246998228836,10.7335380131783));
#833=CARTESIAN_POINT('',(3.46391614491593,1.91046979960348,10.7391958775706));
#834=CARTESIAN_POINT('',(3.71912496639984,2.05515171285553,10.7758737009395));
#835=CARTESIAN_POINT('',(3.96341648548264,2.21467160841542,10.7280748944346));
#836=CARTESIAN_POINT('',(3.49279521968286,1.84818255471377,10.723238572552));
#837=CARTESIAN_POINT('',(3.75582513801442,1.99664162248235,10.7620420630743));
#838=CARTESIAN_POINT('',(4.00692818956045,2.16131485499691,10.7114408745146));
#839=CARTESIAN_POINT('',(3.51201421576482,1.80662793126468,10.7122632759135));
#840=CARTESIAN_POINT('',(3.78026084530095,1.95762463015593,10.7525385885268));
#841=CARTESIAN_POINT('',(4.03587671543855,2.12579497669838,10.7000253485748));
#842=CARTESIAN_POINT('',(3.56958428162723,1.68208527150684,10.678362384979));
#843=CARTESIAN_POINT('',(3.8535450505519,1.84058202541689,10.7231645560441));
#844=CARTESIAN_POINT('',(4.12257487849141,2.01940550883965,10.6647917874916));
#845=CARTESIAN_POINT('',(3.60784933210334,1.59921649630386,10.6544613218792));
#846=CARTESIAN_POINT('',(3.90231178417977,1.7626586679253,10.7024507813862));
#847=CARTESIAN_POINT('',(4.18017846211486,1.94870441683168,10.6399862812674));
#848=CARTESIAN_POINT('',(3.68414130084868,1.43387539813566,10.6040223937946));
#849=CARTESIAN_POINT('',(3.99976569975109,1.60699987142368,10.6587082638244));
#850=CARTESIAN_POINT('',(4.2951031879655,1.80777753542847,10.5876751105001));
#851=CARTESIAN_POINT('',(3.72216822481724,1.35140306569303,10.5774845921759));
#852=CARTESIAN_POINT('',(4.0484629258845,1.52924851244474,10.6356702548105));
#853=CARTESIAN_POINT('',(4.35242433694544,1.73755173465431,10.560169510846));
#854=CARTESIAN_POINT('',(3.77898824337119,1.22811151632,10.5357006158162));
#855=CARTESIAN_POINT('',(4.12138837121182,1.41287973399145,10.5993651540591));
#856=CARTESIAN_POINT('',(4.43816457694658,1.63259543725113,10.5168533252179));
#857=CARTESIAN_POINT('',(3.79789161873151,1.187083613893,10.521442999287));
#858=CARTESIAN_POINT('',(4.14569933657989,1.37409723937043,10.5869598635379));
#859=CARTESIAN_POINT('',(4.46670455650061,1.59767355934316,10.5020715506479));
#860=CARTESIAN_POINT('',(3.83561314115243,1.10517566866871,10.4922670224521));
#861=CARTESIAN_POINT('',(4.1943322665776,1.29657675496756,10.5615441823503));
#862=CARTESIAN_POINT('',(4.52377476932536,1.52792688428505,10.4717781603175));
#863=CARTESIAN_POINT('',(3.85443128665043,1.06429562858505,10.4773486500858));
#864=CARTESIAN_POINT('',(4.21865564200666,1.25783659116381,10.5485323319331));
#865=CARTESIAN_POINT('',(4.55230500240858,1.49310208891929,10.456266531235));
#866=CARTESIAN_POINT('',(3.89196756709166,0.982729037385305,10.446863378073));
#867=CARTESIAN_POINT('',(4.26713338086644,1.18050438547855,10.5219337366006));
#868=CARTESIAN_POINT('',(4.60903464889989,1.42369100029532,10.4246517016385));
#869=CARTESIAN_POINT('',(3.91068575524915,0.942042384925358,10.4312968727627));
#870=CARTESIAN_POINT('',(4.29128851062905,1.14191104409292,10.5083461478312));
#871=CARTESIAN_POINT('',(4.63723425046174,1.38910457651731,10.4085488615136));
#872=CARTESIAN_POINT('',(3.94803859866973,0.860862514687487,10.3995132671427));
#873=CARTESIAN_POINT('',(4.33954937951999,1.0648237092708,10.4805735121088));
#874=CARTESIAN_POINT('',(4.69350529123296,1.32009272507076,10.3756700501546));
#875=CARTESIAN_POINT('',(3.96667325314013,0.820369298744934,10.3832961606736));
#876=CARTESIAN_POINT('',(4.36365616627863,1.02632806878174,10.4663870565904));
#877=CARTESIAN_POINT('',(4.72157672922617,1.28566729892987,10.3588940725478));
#878=CARTESIAN_POINT('',(4.02244581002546,0.699203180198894,10.3336747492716));
#879=CARTESIAN_POINT('',(4.43589820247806,0.910946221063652,10.4229061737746));
#880=CARTESIAN_POINT('',(4.8055053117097,1.18267158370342,10.3075954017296));
#881=CARTESIAN_POINT('',(4.05945156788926,0.618845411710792,10.2993009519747));
#882=CARTESIAN_POINT('',(4.48386384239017,0.834310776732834,10.3927399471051));
#883=CARTESIAN_POINT('',(4.86107560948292,1.1143832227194,10.2721025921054));
#884=CARTESIAN_POINT('',(4.13309068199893,0.459109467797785,10.2280206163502));
#885=CARTESIAN_POINT('',(4.57941280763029,0.681627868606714,10.3300338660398));
#886=CARTESIAN_POINT('',(4.97138212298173,0.978623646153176,10.1985845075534));
#887=CARTESIAN_POINT('',(4.16972397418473,0.37973146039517,10.1911136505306));
#888=CARTESIAN_POINT('',(4.6270017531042,0.60557135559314,10.2974824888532));
#889=CARTESIAN_POINT('',(5.02611819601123,0.911152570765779,10.1605588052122));
#890=CARTESIAN_POINT('',(4.24258515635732,0.222102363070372,10.1148509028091));
#891=CARTESIAN_POINT('',(4.72172008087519,0.454165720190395,10.2300350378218));
#892=CARTESIAN_POINT('',(5.13463904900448,0.77711879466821,10.0820778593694));
#893=CARTESIAN_POINT('',(4.27881306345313,0.14385122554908,10.075495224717));
#894=CARTESIAN_POINT('',(4.76885369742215,0.378809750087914,10.1951281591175));
#895=CARTESIAN_POINT('',(5.18842386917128,0.710556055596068,10.041622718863));
#896=CARTESIAN_POINT('',(4.31482650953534,0.0662268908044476,10.0349529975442));
#897=CARTESIAN_POINT('',(4.81564868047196,0.30397943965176,10.1591165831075));
#898=CARTESIAN_POINT('',(5.2416815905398,0.644484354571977,10.0000000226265));
#899=CARTESIAN_POINT('',(4.31997914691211,0.0551212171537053,10.0291529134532));
#900=CARTESIAN_POINT('',(4.82089955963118,0.293923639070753,10.1543049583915));
#901=CARTESIAN_POINT('',(5.24683424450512,0.635956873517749,9.99554644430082));
#902=CARTESIAN_POINT('',(4.325161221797,0.0440494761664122,10.0233401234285));
#903=CARTESIAN_POINT('',(4.82617982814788,0.283896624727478,10.1494834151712));
#904=CARTESIAN_POINT('',(5.25201633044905,0.62745325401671,9.99108194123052));
#905=CARTESIAN_POINT('',(4.33558424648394,0.0219738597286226,10.0116891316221));
#906=CARTESIAN_POINT('',(4.83680022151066,0.263898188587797,10.1398195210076));
#907=CARTESIAN_POINT('',(5.26243936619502,0.610493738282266,9.98213108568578));
#908=CARTESIAN_POINT('',(4.34082519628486,0.0109699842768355,10.005850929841));
#909=CARTESIAN_POINT('',(4.84214036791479,0.253926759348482,10.1349771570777));
#910=CARTESIAN_POINT('',(5.26768031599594,0.602037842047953,9.97764473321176));
#911=CARTESIAN_POINT('',(4.34609558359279,4.14872069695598E-08,10.0000000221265));
#912=CARTESIAN_POINT('',(4.84750995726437,0.243984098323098,10.1301248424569));
#913=CARTESIAN_POINT('',(5.27295069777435,0.593605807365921,9.97314745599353));
#914=CARTESIAN_POINT('',(4.53842371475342,-0.307724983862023,9.83588000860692));
#915=CARTESIAN_POINT('',(5.03983808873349,-0.0637409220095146,9.96600483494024));
#916=CARTESIAN_POINT('',(5.46527882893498,0.285880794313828,9.80902745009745));
#917=CARTESIAN_POINT('',(4.73075184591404,-0.615450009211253,9.67175999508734));
#918=CARTESIAN_POINT('',(5.23216622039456,-0.371465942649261,9.80188482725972));
#919=CARTESIAN_POINT('',(5.6576069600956,-0.0218442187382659,9.64490744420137));
#920=CARTESIAN_POINT('',(4.92307997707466,-0.923175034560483,9.50763998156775));
#921=CARTESIAN_POINT('',(5.42449435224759,-0.679190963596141,9.6377648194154));
#922=CARTESIAN_POINT('',(5.84993509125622,-0.32956923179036,9.48078743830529));
#923=(BOUNDED_SURFACE() B_SPLINE_SURFACE(3,2,((#755,#756,#757),(#758,#759,#760),(#761,#762,
#763),(#764,#765,#766),(#767,#768,#769),(#770,#771,#772),(#773,#774,#775),(#776,#777,#778),
(#779,#780,#781),(#782,#783,#784),(#785,#786,#787),(#788,#789,#790),(#791,#792,#793),(#794,#795,
#796),(#797,#798,#799),(#800,#801,#802),(#803,#804,#805),(#806,#807,#808),(#809,#810,#811),
(#812,#813,#814),(#815,#816,#817),(#818,#819,#820),(#821,#822,#823),(#824,#825,#826),(#827,#828,
#829),(#830,#831,#832),(#833,#834,#835),(#836,#837,#838),(#839,#840,#841),(#842,#843,#844),
(#845,#846,#847),(#848,#849,#850),(#851,#852,#853),(#854,#855,#856),(#857,#858,#859),(#860,#861,
#862),(#863,#864,#865),(#866,#867,#868),(#869,#870,#871),(#872,#873,#874),(#875,#876,#877),
(#878,#879,#880),(#881,#882,#883),(#884,#885,#886),(#887,#888,#889),(#890,#891,#892),(#893,#894,
#895),(#896,#897,#898),(#899,#900,#901),(#902,#903,#904),(#905,#906,#907),(#908,#909,#910),
(#911,#912,#913),(#914,#915,#916),(#917,#918,#919),(#920,#921,#922)),.UNSPECIFIED.,.F.,.F.,
.F.) B_SPLINE_SURFACE_WITH_KNOTS((4,2,2,2,2,2,2,2,2,2,2,2,2,2,2,2,2,2,2,2,2,2,2,3,2,3,4),(3,3),
(0.,0.0168758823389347,0.127307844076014,0.237741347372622,0.458615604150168,0.679538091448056,
0.900457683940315,1.12161272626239,1.34276808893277,1.56391683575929,1.67449383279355,
1.78507092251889,1.84230600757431,1.89954102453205,2.01401148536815,2.24294705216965,
2.47187711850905,2.5863433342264,2.70081164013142,2.81521129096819,2.92961202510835,
3.15841799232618,3.38726266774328,3.61609764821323,3.64883713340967,3.68157661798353,
4.87639105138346),(0.,1.),
.UNSPECIFIED.) GEOMETRIC_REPRESENTATION_ITEM() RATIONAL_B_SPLINE_SURFACE(((1.,1.,1.),(1.,
1.00000000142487,1.),(1.,0.999999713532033,1.),(1.,0.999995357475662,1.),(1.,0.999979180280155,
1.),(1.,0.999921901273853,1.),(1.,0.999880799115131,1.),(1.,0.999719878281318,1.),(1.,
0.999562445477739,1.),(1.,0.999146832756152,1.),(1.,0.998888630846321,1.),(1.,0.998270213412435,
1.),(1.,0.997909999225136,1.),(1.,0.997091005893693,1.),(1.,0.996632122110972,1.),(1.,
0.995615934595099,1.),(1.,0.995058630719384,1.),(1.,0.993850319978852,1.),(1.,0.993199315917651,
1.),(1.,0.992155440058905,1.),(1.,0.991796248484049,1.),(1.,0.991058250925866,1.),(1.,
0.990679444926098,1.),(1.,0.990084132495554,1.),(1.,0.989877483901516,1.),(1.,0.989460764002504,
1.),(1.,0.989250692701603,1.),(1.,0.988610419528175,1.),(1.,0.988170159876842,1.),(1.,
0.986812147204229,1.),(1.,0.98585714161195,1.),(1.,0.983844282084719,1.),(1.,0.982786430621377,
1.),(1.,0.981123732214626,1.),(1.,0.980556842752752,1.),(1.,0.97939490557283,1.),(1.,
0.978799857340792,1.),(1.,0.977593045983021,1.),(1.,0.976981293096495,1.),(1.,0.975735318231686,
1.),(1.,0.975101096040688,1.),(1.,0.973168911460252,1.),(1.,0.971841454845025,1.),(1.,
0.969117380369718,1.),(1.,0.967720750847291,1.),(1.,0.96487097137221,1.),(1.,0.963417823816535,
1.),(1.,0.961942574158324,1.),(1.,0.961848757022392,1.),(1.,0.961754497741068,1.),(1.,
0.961565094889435,1.),(1.,0.961469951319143,1.),(1.,0.961374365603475,1.),(1.,0.961374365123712,
1.),(1.,0.961374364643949,1.),(1.,0.961374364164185,1.))) REPRESENTATION_ITEM('') SURFACE());
#924=CARTESIAN_POINT('',(4.92307997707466,-0.923175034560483,9.50763998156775));
#925=CARTESIAN_POINT('',(4.73075184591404,-0.615450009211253,9.67175999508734));
#926=CARTESIAN_POINT('',(4.53842371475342,-0.307724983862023,9.83588000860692));
#927=CARTESIAN_POINT('',(4.34609558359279,4.14872069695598E-08,10.0000000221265));
#928=CARTESIAN_POINT('',(4.34082519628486,0.0109699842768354,10.005850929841));
#929=CARTESIAN_POINT('',(4.33558424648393,0.0219738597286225,10.0116891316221));
#930=CARTESIAN_POINT('',(4.325161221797,0.0440494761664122,10.0233401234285));
#931=CARTESIAN_POINT('',(4.31997914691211,0.0551212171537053,10.0291529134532));
#932=CARTESIAN_POINT('',(4.31482650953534,0.0662268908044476,10.0349529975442));
#933=CARTESIAN_POINT('',(4.27881306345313,0.14385122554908,10.075495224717));
#934=CARTESIAN_POINT('',(4.24258515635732,0.222102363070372,10.1148509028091));
#935=CARTESIAN_POINT('',(4.16972397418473,0.37973146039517,10.1911136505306));
#936=CARTESIAN_POINT('',(4.13309068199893,0.459109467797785,10.2280206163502));
#937=CARTESIAN_POINT('',(4.05945156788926,0.618845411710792,10.2993009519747));
#938=CARTESIAN_POINT('',(4.02244581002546,0.699203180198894,10.3336747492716));
#939=CARTESIAN_POINT('',(3.96667325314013,0.820369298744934,10.3832961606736));
#940=CARTESIAN_POINT('',(3.94803859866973,0.860862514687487,10.3995132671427));
#941=CARTESIAN_POINT('',(3.91068575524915,0.942042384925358,10.4312968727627));
#942=CARTESIAN_POINT('',(3.89196756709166,0.982729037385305,10.446863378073));
#943=CARTESIAN_POINT('',(3.85443128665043,1.06429562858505,10.4773486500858));
#944=CARTESIAN_POINT('',(3.83561314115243,1.10517566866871,10.4922670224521));
#945=CARTESIAN_POINT('',(3.79789161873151,1.187083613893,10.521442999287));
#946=CARTESIAN_POINT('',(3.77898824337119,1.22811151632,10.5357006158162));
#947=CARTESIAN_POINT('',(3.72216822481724,1.35140306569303,10.5774845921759));
#948=CARTESIAN_POINT('',(3.68414130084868,1.43387539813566,10.6040223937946));
#949=CARTESIAN_POINT('',(3.60784933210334,1.59921649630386,10.6544613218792));
#950=CARTESIAN_POINT('',(3.56958428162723,1.68208527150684,10.678362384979));
#951=CARTESIAN_POINT('',(3.51201421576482,1.80662793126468,10.7122632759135));
#952=CARTESIAN_POINT('',(3.49279521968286,1.84818255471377,10.723238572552));
#953=CARTESIAN_POINT('',(3.46391614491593,1.91046979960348,10.7391958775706));
#954=CARTESIAN_POINT('',(3.45428137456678,1.93122472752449,10.74443069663));
#955=CARTESIAN_POINT('',(3.43499672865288,1.97289186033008,10.7547735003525));
#956=CARTESIAN_POINT('',(3.42534685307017,1.99380406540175,10.7598814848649));
#957=CARTESIAN_POINT('',(3.39704307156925,2.0551447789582,10.7746181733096));
#958=CARTESIAN_POINT('',(3.37837935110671,2.09559801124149,10.7840233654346));
#959=CARTESIAN_POINT('',(3.34102853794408,2.17666355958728,10.802245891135));
#960=CARTESIAN_POINT('',(3.32234144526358,2.21727587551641,10.811063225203));
#961=CARTESIAN_POINT('',(3.26624464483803,2.33928517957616,10.8366161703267));
#962=CARTESIAN_POINT('',(3.22879852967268,2.42085644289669,10.8524531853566));
#963=CARTESIAN_POINT('',(3.15381332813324,2.58436345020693,10.8817116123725));
#964=CARTESIAN_POINT('',(3.11627423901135,2.66629920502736,10.8951329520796));
#965=CARTESIAN_POINT('',(3.04105360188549,2.83029644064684,10.9195455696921));
#966=CARTESIAN_POINT('',(3.00337205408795,2.9123579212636,10.9305368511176));
#967=CARTESIAN_POINT('',(2.927912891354,3.07672340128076,10.9501087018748));
#968=CARTESIAN_POINT('',(2.89013542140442,3.15902704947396,10.9586918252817));
#969=CARTESIAN_POINT('',(2.81443306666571,3.3235909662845,10.9734346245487));
#970=CARTESIAN_POINT('',(2.77650817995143,3.40585123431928,10.979594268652));
#971=CARTESIAN_POINT('',(2.70043572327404,3.57034467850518,10.9895178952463));
#972=CARTESIAN_POINT('',(2.66228820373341,3.65257785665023,10.9932824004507));
#973=CARTESIAN_POINT('',(2.60489707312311,3.77587441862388,10.9971369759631));
#974=CARTESIAN_POINT('',(2.58573870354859,3.81696373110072,10.998123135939));
#975=CARTESIAN_POINT('',(2.54728722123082,3.89910089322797,10.9994987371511));
#976=CARTESIAN_POINT('',(2.5279941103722,3.94014874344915,10.9998881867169));
#977=CARTESIAN_POINT('',(2.50583956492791,3.98749484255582,10.9999931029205));
#978=CARTESIAN_POINT('',(2.50290452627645,3.99377153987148,11.0000000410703));
#979=CARTESIAN_POINT('',(2.49997175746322,4.00004890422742,11.0000000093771));
#980=B_SPLINE_CURVE_WITH_KNOTS('',3,(#924,#925,#926,#927,#928,#929,#930,#931,#932,#933,#934,
#935,#936,#937,#938,#939,#940,#941,#942,#943,#944,#945,#946,#947,#948,#949,#950,#951,#952,#953,
#954,#955,#956,#957,#958,#959,#960,#961,#962,#963,#964,#965,#966,#967,#968,#969,#970,#971,#972,
#973,#974,#975,#976,#977,#978,#979),.UNSPECIFIED.,.F.,.F.,(4,3,2,3,2,2,2,2,2,2,2,2,2,2,2,2,2,2,
2,2,2,2,2,2,2,2,4),(0.,1.19481443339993,1.22755391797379,1.26029340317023,1.48912838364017,
1.71797305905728,1.94677902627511,2.06117976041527,2.17557941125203,2.29004771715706,
2.40451393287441,2.63344399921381,2.8623795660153,2.9768500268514,3.03408504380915,
3.09132012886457,3.20189721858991,3.31247421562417,3.53362296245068,3.75477832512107,
3.97593336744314,4.1968529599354,4.41777544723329,4.63864970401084,4.74908320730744,
4.85951516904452,4.87639105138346),.UNSPECIFIED.);
#981=EDGE_CURVE('E1305',#752,#256,#980,.T.);
#982=ORIENTED_EDGE('',*,*,#981,.T.);
#983=EDGE_LOOP('',(#260,#510,#704,#725,#733,#754,#982));
#984=FACE_BOUND('',#983,.T.);
#985=ADVANCED_FACE('F1073',(#984),#36,.F.);
#986=CARTESIAN_POINT('',(-5.,0.,10.));
#987=DIRECTION('',(0.,1.,0.));
#988=DIRECTION('',(0.,0.,1.));
#989=AXIS2_PLACEMENT_3D('',#986,#987,#988);
#990=PLANE('',#989);
#991=ORIENTED_EDGE('',*,*,#732,.F.);
#992=DIRECTION('',(0.,0.,-1.));
#993=VECTOR('',#992,1.);
#994=CARTESIAN_POINT('',(-3.61399906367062,0.,10.));
#995=LINE('',#994,#993);
#996=CARTESIAN_POINT('',(-3.61399906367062,0.,0.));
#997=VERTEX_POINT('',#996);
#998=EDGE_CURVE('E1331',#723,#997,#995,.T.);
#999=ORIENTED_EDGE('',*,*,#998,.T.);
#1000=DIRECTION('',(1.,0.,0.));
#1001=VECTOR('',#1000,1.);
#1002=CARTESIAN_POINT('',(-5.,0.,0.));
#1003=LINE('',#1002,#1001);
#1004=CARTESIAN_POINT('',(3.61399906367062,0.,0.));
#1005=VERTEX_POINT('',#1004);
#1006=EDGE_CURVE('E1454',#997,#1005,#1003,.T.);
#1007=ORIENTED_EDGE('',*,*,#1006,.T.);
#1008=DIRECTION('',(0.,0.,-1.));
#1009=VECTOR('',#1008,1.);
#1010=CARTESIAN_POINT('',(3.61399906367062,0.,10.));
#1011=LINE('',#1010,#1009);
#1012=EDGE_CURVE('E1329',#1005,#731,#1011,.F.);
#1013=ORIENTED_EDGE('',*,*,#1012,.T.);
#1014=EDGE_LOOP('',(#991,#999,#1007,#1013));
#1015=FACE_BOUND('',#1014,.T.);
#1016=ADVANCED_FACE('F1242',(#1015),#990,.F.);
#1017=CARTESIAN_POINT('',(-14.4298453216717,35.8129208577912,2.5));
#1018=DIRECTION('',(0.,-1.,0.));
#1019=DIRECTION('',(0.,0.,1.));
#1020=AXIS2_PLACEMENT_3D('',#1017,#1018,#1019);
#1021=CIRCLE('',#1020,8.5);
#1022=DIRECTION('',(0.351123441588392,-0.936329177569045,0.));
#1023=VECTOR('',#1022,1.);
#1024=SURFACE_OF_LINEAR_EXTRUSION('',#1021,#1023);
#1025=CARTESIAN_POINT('',(-5.48665741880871,1.29775311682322,10.));
#1026=CARTESIAN_POINT('',(-5.46828464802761,1.24873216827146,9.99998952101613));
#1027=CARTESIAN_POINT('',(-5.44797222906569,1.20044575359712,10.0011705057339));
#1028=CARTESIAN_POINT('',(-5.4036882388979,1.1057209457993,10.0058365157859));
#1029=CARTESIAN_POINT('',(-5.37971824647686,1.05928176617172,10.0093205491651));
#1030=CARTESIAN_POINT('',(-5.32899840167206,0.969779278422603,10.0183930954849));
#1031=CARTESIAN_POINT('',(-5.30233815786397,0.926659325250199,10.0239238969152));
#1032=CARTESIAN_POINT('',(-5.24599104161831,0.842779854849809,10.0369557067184));
#1033=CARTESIAN_POINT('',(-5.2163042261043,0.80202029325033,10.0444566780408));
#1034=CARTESIAN_POINT('',(-5.12599092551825,0.6873626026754,10.0688852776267));
#1035=CARTESIAN_POINT('',(-5.06165312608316,0.616812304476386,10.088205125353));
#1036=CARTESIAN_POINT('',(-4.95805428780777,0.518148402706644,10.1213402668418));
#1037=CARTESIAN_POINT('',(-4.92182160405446,0.486087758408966,10.1332606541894));
#1038=CARTESIAN_POINT('',(-4.84740355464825,0.424872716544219,10.158257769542));
#1039=CARTESIAN_POINT('',(-4.80921971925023,0.395716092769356,10.1713335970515));
#1040=CARTESIAN_POINT('',(-4.77014014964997,0.368026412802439,10.1848962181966));
#1041=B_SPLINE_CURVE_WITH_KNOTS('',3,(#1025,#1026,#1027,#1028,#1029,#1030,#1031,#1032,#1033,
#1034,#1035,#1036,#1037,#1038,#1039,#1040),.UNSPECIFIED.,.F.,.F.,(4,2,2,2,2,2,2,4),(0.,
0.156987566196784,0.313907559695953,0.466703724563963,0.619497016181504,0.910399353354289,
1.0597731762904,1.20903159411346),.UNSPECIFIED.);
#1042=CARTESIAN_POINT('',(-5.48665741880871,1.29775311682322,10.));
#1043=VERTEX_POINT('',#1042);
#1044=CARTESIAN_POINT('',(-5.16571302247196,0.738182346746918,10.0582073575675));
#1045=VERTEX_POINT('',#1044);
#1046=EDGE_CURVE('E1341',#1043,#1045,#1041,.T.);
#1047=ORIENTED_EDGE('',*,*,#1046,.T.);
#1048=CARTESIAN_POINT('',(-5.91238423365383,-0.375440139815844,9.33486866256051));
#1049=CARTESIAN_POINT('',(-5.87005301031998,-0.293422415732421,9.38889547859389));
#1050=CARTESIAN_POINT('',(-5.82554381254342,-0.211650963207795,9.44266855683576));
#1051=CARTESIAN_POINT('',(-5.73186896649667,-0.0490237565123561,9.54939252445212));
#1052=CARTESIAN_POINT('',(-5.68271426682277,0.031833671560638,9.6023450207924));
#1053=CARTESIAN_POINT('',(-5.57924926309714,0.192601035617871,9.70737117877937));
#1054=CARTESIAN_POINT('',(-5.52493820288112,0.272510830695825,9.75944471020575));
#1055=CARTESIAN_POINT('',(-5.41058808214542,0.431213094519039,9.8625536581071));
#1056=CARTESIAN_POINT('',(-5.35053609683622,0.510002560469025,9.91358640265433));
#1057=CARTESIAN_POINT('',(-5.28744814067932,0.587967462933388,9.9639020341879));
#1058=CARTESIAN_POINT('',(-5.18879038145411,0.709838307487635,10.0425712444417));
#1059=CARTESIAN_POINT('',(-5.08863801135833,0.833182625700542,10.1169044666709));
#1060=CARTESIAN_POINT('',(-4.88587300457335,1.08253119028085,10.2567335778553));
#1061=CARTESIAN_POINT('',(-4.78326077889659,1.20853499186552,10.3222309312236));
#1062=CARTESIAN_POINT('',(-4.57595103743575,1.46310458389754,10.4443203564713));
#1063=CARTESIAN_POINT('',(-4.47125122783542,1.59167319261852,10.5009019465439));
#1064=CARTESIAN_POINT('',(-4.3129741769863,1.78604248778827,10.5789892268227));
#1065=CARTESIAN_POINT('',(-4.26000694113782,1.85108948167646,10.6038889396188));
#1066=CARTESIAN_POINT('',(-4.15366642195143,1.98163465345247,10.651430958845));
#1067=CARTESIAN_POINT('',(-4.10029313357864,2.0471328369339,10.6740732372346));
#1068=CARTESIAN_POINT('',(-4.01545906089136,2.15111156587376,10.7081346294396));
#1069=CARTESIAN_POINT('',(-3.984140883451,2.18947016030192,10.7202968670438));
#1070=CARTESIAN_POINT('',(-3.92134964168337,2.26629886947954,10.7438568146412));
#1071=CARTESIAN_POINT('',(-3.88987657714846,2.30476898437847,10.7552545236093));
#1072=CARTESIAN_POINT('',(-3.79528676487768,2.42035723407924,10.7882874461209));
#1073=CARTESIAN_POINT('',(-3.73199846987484,2.49765440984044,10.808762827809));
#1074=CARTESIAN_POINT('',(-3.6050429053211,2.65266812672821,10.8466089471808));
#1075=CARTESIAN_POINT('',(-3.54137559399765,2.73038471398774,10.8639793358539));
#1076=CARTESIAN_POINT('',(-3.41375779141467,2.88617409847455,10.8956039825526));
#1077=CARTESIAN_POINT('',(-3.34980730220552,2.96424689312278,10.9098582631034));
#1078=CARTESIAN_POINT('',(-3.25369484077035,3.0814967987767,10.9288978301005));
#1079=CARTESIAN_POINT('',(-3.22164495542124,3.12058074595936,10.9348512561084));
#1080=CARTESIAN_POINT('',(-3.15750464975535,3.19881466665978,10.9459783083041));
#1081=CARTESIAN_POINT('',(-3.12541422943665,3.23796464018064,10.9511519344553));
#1082=CARTESIAN_POINT('',(-3.02908375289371,3.35549805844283,10.965504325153));
#1083=CARTESIAN_POINT('',(-2.96478425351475,3.43396527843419,10.973514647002));
#1084=CARTESIAN_POINT('',(-2.83604806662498,3.59100312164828,10.9864190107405));
#1085=CARTESIAN_POINT('',(-2.77161142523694,3.66957370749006,10.9913139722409));
#1086=CARTESIAN_POINT('',(-2.6748179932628,3.78744088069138,10.9963183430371));
#1087=CARTESIAN_POINT('',(-2.64253116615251,3.82673093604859,10.9975967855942));
#1088=CARTESIAN_POINT('',(-2.59408921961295,3.88567055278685,10.998929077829));
#1089=CARTESIAN_POINT('',(-2.57794004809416,3.90531773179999,10.9992756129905));
#1090=CARTESIAN_POINT('',(-2.54559195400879,3.9445935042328,10.9997733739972));
#1091=CARTESIAN_POINT('',(-2.52939303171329,3.96422209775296,10.9999246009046));
#1092=CARTESIAN_POINT('',(-2.50884245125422,3.98926660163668,10.9999927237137));
#1093=CARTESIAN_POINT('',(-2.50442683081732,3.9946562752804,11.0000000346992));
#1094=CARTESIAN_POINT('',(-2.50001834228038,4.0000488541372,11.));
#1095=B_SPLINE_CURVE_WITH_KNOTS('',3,(#1048,#1049,#1050,#1051,#1052,#1053,#1054,#1055,#1056,
#1057,#1058,#1059,#1060,#1061,#1062,#1063,#1064,#1065,#1066,#1067,#1068,#1069,#1070,#1071,#1072,
#1073,#1074,#1075,#1076,#1077,#1078,#1079,#1080,#1081,#1082,#1083,#1084,#1085,#1086,#1087,#1088,
#1089,#1090,#1091,#1092,#1093,#1094),.UNSPECIFIED.,.F.,.F.,(4,2,2,2,3,2,2,2,2,2,2,2,2,2,2,2,2,2,
2,2,2,2,4),(0.,0.270289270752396,0.539956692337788,0.809663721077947,1.07999293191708,
1.50268503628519,1.92530699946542,2.34842216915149,2.5600086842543,2.7715978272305,
2.89496278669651,3.01832791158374,3.26505450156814,3.5118088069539,3.75856132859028,
3.88179410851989,4.00502689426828,4.2514915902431,4.49788349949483,4.62107390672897,
4.68266838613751,4.74426253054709,4.76114413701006),.UNSPECIFIED.);
#1096=EDGE_CURVE('E1422',#1045,#508,#1095,.T.);
#1097=ORIENTED_EDGE('',*,*,#1096,.T.);
#1098=CARTESIAN_POINT('',(-2.50001834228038,4.00004885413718,11.));
#1099=CARTESIAN_POINT('',(-2.49734051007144,4.00564338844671,11.0000000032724));
#1100=CARTESIAN_POINT('',(-2.49466228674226,4.01123764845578,10.999995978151));
#1101=CARTESIAN_POINT('',(-2.40455945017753,4.19940783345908,10.9997250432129));
#1102=CARTESIAN_POINT('',(-2.31672759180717,4.38168953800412,10.9951699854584));
#1103=CARTESIAN_POINT('',(-2.14081753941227,4.74555311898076,10.9774092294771));
#1104=CARTESIAN_POINT('',(-2.05273929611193,4.92713483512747,10.9642016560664));
#1105=CARTESIAN_POINT('',(-1.87660697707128,5.28951892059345,10.929074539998));
#1106=CARTESIAN_POINT('',(-1.78855301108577,5.47032034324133,10.9071464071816));
#1107=CARTESIAN_POINT('',(-1.6568871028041,5.7406253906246,10.8677147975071));
#1108=CARTESIAN_POINT('',(-1.61306633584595,5.83058023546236,10.8534805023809));
#1109=CARTESIAN_POINT('',(-1.525604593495,6.01016964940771,10.8228311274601));
#1110=CARTESIAN_POINT('',(-1.48196361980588,6.09980421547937,10.8064160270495));
#1111=CARTESIAN_POINT('',(-1.41331250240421,6.24095155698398,10.7788033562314));
#1112=CARTESIAN_POINT('',(-1.38821779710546,6.2925771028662,10.7683300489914));
#1113=CARTESIAN_POINT('',(-1.33809378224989,6.39568685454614,10.7466537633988));
#1114=CARTESIAN_POINT('',(-1.313064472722,6.44717106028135,10.7354507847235));
#1115=CARTESIAN_POINT('',(-1.23806666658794,6.60138402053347,10.7007428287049));
#1116=CARTESIAN_POINT('',(-1.18818755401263,6.70387463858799,10.6761385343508));
#1117=CARTESIAN_POINT('',(-1.08875639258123,6.90817662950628,10.6240000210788));
#1118=CARTESIAN_POINT('',(-1.0392043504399,7.00998798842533,10.5964657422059));
#1119=CARTESIAN_POINT('',(-0.940445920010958,7.21281926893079,10.5384568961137));
#1120=CARTESIAN_POINT('',(-0.891239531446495,7.31383919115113,10.5079823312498));
#1121=CARTESIAN_POINT('',(-0.744178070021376,7.61555226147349,10.4121282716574));
#1122=CARTESIAN_POINT('',(-0.646862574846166,7.81493600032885,10.3423089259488));
#1123=CARTESIAN_POINT('',(-0.502271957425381,8.11075894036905,10.2286683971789));
#1124=CARTESIAN_POINT('',(-0.454300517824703,8.20883468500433,10.1892983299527));
#1125=CARTESIAN_POINT('',(-0.358864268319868,8.40381750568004,10.1075753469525));
#1126=CARTESIAN_POINT('',(-0.311399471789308,8.50072455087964,10.0652223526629));
#1127=CARTESIAN_POINT('',(-0.26421033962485,8.5970061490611,10.021372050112));
#1128=CARTESIAN_POINT('',(-0.21978222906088,8.6876821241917,9.98007759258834));
#1129=CARTESIAN_POINT('',(-0.177743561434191,8.77990432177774,9.93817653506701));
#1130=CARTESIAN_POINT('',(-0.0981517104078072,8.96698106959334,9.85334905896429));
#1131=CARTESIAN_POINT('',(-0.0605963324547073,9.0618343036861,9.81042315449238));
#1132=CARTESIAN_POINT('',(0.0453903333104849,9.34855391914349,9.68088501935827));
#1133=CARTESIAN_POINT('',(0.107704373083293,9.54375566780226,9.59297762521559));
#1134=CARTESIAN_POINT('',(0.247855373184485,10.0472335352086,9.3667834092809));
#1135=CARTESIAN_POINT('',(0.316013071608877,10.3598546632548,9.2268317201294));
#1136=CARTESIAN_POINT('',(0.425306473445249,10.9944544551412,8.94340031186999));
#1137=CARTESIAN_POINT('',(0.466410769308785,11.3164435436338,8.79991669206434));
#1138=CARTESIAN_POINT('',(0.526729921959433,11.9706422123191,8.50884738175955));
#1139=CARTESIAN_POINT('',(0.545625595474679,12.3029320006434,8.36123237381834));
#1140=CARTESIAN_POINT('',(0.564191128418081,12.9708271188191,8.06485348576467));
#1141=CARTESIAN_POINT('',(0.563869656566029,13.3064308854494,7.91609015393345));
#1142=CARTESIAN_POINT('',(0.545991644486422,14.0123570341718,7.60342317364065));
#1143=CARTESIAN_POINT('',(0.52676370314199,14.3828847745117,7.4394527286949));
#1144=CARTESIAN_POINT('',(0.471333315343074,15.1251574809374,7.11119087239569));
#1145=CARTESIAN_POINT('',(0.435126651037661,15.4969027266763,6.94689939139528));
#1146=CARTESIAN_POINT('',(0.347764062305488,16.2412878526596,6.61810079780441));
#1147=CARTESIAN_POINT('',(0.296583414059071,16.6139281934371,6.45359378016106));
#1148=CARTESIAN_POINT('',(0.180923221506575,17.358905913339,6.1248750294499));
#1149=CARTESIAN_POINT('',(0.116442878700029,17.7312432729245,5.96066331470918));
#1150=CARTESIAN_POINT('',(-0.0209508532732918,18.4562320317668,5.64107443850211));
#1151=CARTESIAN_POINT('',(-0.0932684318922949,18.8089213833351,5.48567278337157));
#1152=CARTESIAN_POINT('',(-0.247863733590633,19.5133464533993,5.17543418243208));
#1153=CARTESIAN_POINT('',(-0.3301419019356,19.8650821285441,5.02059726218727));
#1154=CARTESIAN_POINT('',(-0.503576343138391,20.5658861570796,4.7122506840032));
#1155=CARTESIAN_POINT('',(-0.594694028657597,20.9149595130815,4.55873818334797));
#1156=CARTESIAN_POINT('',(-0.785527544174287,21.6116843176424,4.25250430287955));
#1157=CARTESIAN_POINT('',(-0.885241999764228,21.9593359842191,4.09978280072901));
#1158=CARTESIAN_POINT('',(-0.988986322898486,22.3062156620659,3.94749026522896));
#1159=B_SPLINE_CURVE_WITH_KNOTS('',3,(#1098,#1099,#1100,#1101,#1102,#1103,#1104,#1105,#1106,
#1107,#1108,#1109,#1110,#1111,#1112,#1113,#1114,#1115,#1116,#1117,#1118,#1119,#1120,#1121,#1122,
#1123,#1124,#1125,#1126,#1127,#1128,#1129,#1130,#1131,#1132,#1133,#1134,#1135,#1136,#1137,#1138,
#1139,#1140,#1141,#1142,#1143,#1144,#1145,#1146,#1147,#1148,#1149,#1150,#1151,#1152,#1153,#1154,
#1155,#1156,#1157,#1158),.UNSPECIFIED.,.F.,.F.,(4,2,2,2,2,2,2,2,2,2,2,2,2,2,3,2,2,2,2,2,2,2,2,2,
2,2,2,2,2,4),(0.,0.0213492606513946,0.718145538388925,1.4150928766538,2.11272844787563,
2.46156709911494,2.81040904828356,3.01192691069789,3.21344486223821,3.61647484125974,
4.01951306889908,4.42255097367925,5.2284799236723,5.63152973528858,6.03459015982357,
6.4140914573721,6.79340622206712,7.5471615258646,8.70635186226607,9.86688559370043,
11.0439021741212,12.2203878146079,13.5111723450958,14.8022777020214,16.0955269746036,
17.3888539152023,18.6163925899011,19.8439861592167,21.066443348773,22.288705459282),.UNSPECIFIED.);
#1160=CARTESIAN_POINT('',(-0.241482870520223,8.64395432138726,10.));
#1161=VERTEX_POINT('',#1160);
#1162=EDGE_CURVE('E1304',#508,#1161,#1159,.T.);
#1163=ORIENTED_EDGE('',*,*,#1162,.T.);
#1164=DIRECTION('',(-0.351123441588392,0.936329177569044,0.));
#1165=VECTOR('',#1164,1.);
#1166=CARTESIAN_POINT('',(-10.4298453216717,35.8129208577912,10.));
#1167=LINE('',#1166,#1165);
#1168=CARTESIAN_POINT('',(-10.4298453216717,35.8129208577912,10.));
#1169=VERTEX_POINT('',#1168);
#1170=EDGE_CURVE('E1190',#1161,#1169,#1167,.T.);
#1171=ORIENTED_EDGE('',*,*,#1170,.T.);
#1172=CARTESIAN_POINT('',(-18.4298453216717,35.8129208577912,10.));
#1173=VERTEX_POINT('',#1172);
#1174=EDGE_CURVE('E1206',#1169,#1173,#1021,.T.);
#1175=ORIENTED_EDGE('',*,*,#1174,.T.);
#1176=DIRECTION('',(0.351123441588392,-0.936329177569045,0.));
#1177=VECTOR('',#1176,1.);
#1178=CARTESIAN_POINT('',(-18.4298453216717,35.8129208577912,10.));
#1179=LINE('',#1178,#1177);
#1180=EDGE_CURVE('E1322',#1173,#1043,#1179,.T.);
#1181=ORIENTED_EDGE('',*,*,#1180,.T.);
#1182=EDGE_LOOP('',(#1047,#1097,#1163,#1171,#1175,#1181));
#1183=FACE_BOUND('',#1182,.T.);
#1184=ADVANCED_FACE('F1245',(#1183),#1024,.T.);
#1185=CARTESIAN_POINT('',(-10.4298453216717,35.8129208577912,10.));
#1186=DIRECTION('',(0.,-1.,0.));
#1187=DIRECTION('',(0.,0.,-1.));
#1188=AXIS2_PLACEMENT_3D('',#1185,#1186,#1187);
#1189=PLANE('',#1188);
#1190=DIRECTION('',(-1.,0.,0.));
#1191=VECTOR('',#1190,1.);
#1192=CARTESIAN_POINT('',(-10.4298453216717,35.8129208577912,0.));
#1193=LINE('',#1192,#1191);
#1194=CARTESIAN_POINT('',(-10.4298453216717,35.8129208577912,0.));
#1195=VERTEX_POINT('',#1194);
#1196=CARTESIAN_POINT('',(-18.4298453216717,35.8129208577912,0.));
#1197=VERTEX_POINT('',#1196);
#1198=EDGE_CURVE('E1209',#1195,#1197,#1193,.T.);
#1199=ORIENTED_EDGE('',*,*,#1198,.T.);
#1200=DIRECTION('',(0.,0.,-1.));
#1201=VECTOR('',#1200,1.);
#1202=CARTESIAN_POINT('',(-18.4298453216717,35.8129208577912,10.));
#1203=LINE('',#1202,#1201);
#1204=EDGE_CURVE('E1332',#1173,#1197,#1203,.T.);
#1205=ORIENTED_EDGE('',*,*,#1204,.F.);
#1206=ORIENTED_EDGE('',*,*,#1174,.F.);
#1207=DIRECTION('',(0.,0.,-1.));
#1208=VECTOR('',#1207,1.);
#1209=CARTESIAN_POINT('',(-10.4298453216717,35.8129208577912,10.));
#1210=LINE('',#1209,#1208);
#1211=EDGE_CURVE('E1313',#1169,#1195,#1210,.T.);
#1212=ORIENTED_EDGE('',*,*,#1211,.T.);
#1213=EDGE_LOOP('',(#1199,#1205,#1206,#1212));
#1214=FACE_BOUND('',#1213,.T.);
#1215=ADVANCED_FACE('F1249',(#1214),#1189,.F.);
#1216=CARTESIAN_POINT('',(-18.4298453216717,35.8129208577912,10.));
#1217=DIRECTION('',(0.936329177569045,0.351123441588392,0.));
#1218=DIRECTION('',(-0.351123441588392,0.936329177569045,0.));
#1219=AXIS2_PLACEMENT_3D('',#1216,#1217,#1218);
#1220=PLANE('',#1219);
#1221=DIRECTION('',(0.351123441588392,-0.936329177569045,0.));
#1222=VECTOR('',#1221,1.);
#1223=CARTESIAN_POINT('',(-18.4298453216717,35.8129208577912,0.));
#1224=LINE('',#1223,#1222);
#1225=CARTESIAN_POINT('',(-5.48665741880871,1.29775311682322,0.));
#1226=VERTEX_POINT('',#1225);
#1227=EDGE_CURVE('E1457',#1197,#1226,#1224,.T.);
#1228=ORIENTED_EDGE('',*,*,#1227,.T.);
#1229=DIRECTION('',(0.,0.,-1.));
#1230=VECTOR('',#1229,1.);
#1231=CARTESIAN_POINT('',(-5.48665741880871,1.29775311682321,10.));
#1232=LINE('',#1231,#1230);
#1233=EDGE_CURVE('E1339',#1226,#1043,#1232,.F.);
#1234=ORIENTED_EDGE('',*,*,#1233,.T.);
#1235=ORIENTED_EDGE('',*,*,#1180,.F.);
#1236=ORIENTED_EDGE('',*,*,#1204,.T.);
#1237=EDGE_LOOP('',(#1228,#1234,#1235,#1236));
#1238=FACE_BOUND('',#1237,.T.);
#1239=ADVANCED_FACE('F1240',(#1238),#1220,.F.);
#1240=CARTESIAN_POINT('',(5.,0.,10.));
#1241=DIRECTION('',(-0.936329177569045,0.351123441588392,0.));
#1242=DIRECTION('',(-0.351123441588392,-0.936329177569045,0.));
#1243=AXIS2_PLACEMENT_3D('',#1240,#1241,#1242);
#1244=PLANE('',#1243);
#1245=DIRECTION('',(0.351123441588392,0.936329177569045,0.));
#1246=VECTOR('',#1245,1.);
#1247=CARTESIAN_POINT('',(5.,0.,10.));
#1248=LINE('',#1247,#1246);
#1249=CARTESIAN_POINT('',(5.48665741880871,1.29775311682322,10.));
#1250=VERTEX_POINT('',#1249);
#1251=CARTESIAN_POINT('',(18.4298453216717,35.8129208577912,10.));
#1252=VERTEX_POINT('',#1251);
#1253=EDGE_CURVE('E1191',#1250,#1252,#1248,.T.);
#1254=ORIENTED_EDGE('',*,*,#1253,.F.);
#1255=DIRECTION('',(0.,0.,-1.));
#1256=VECTOR('',#1255,1.);
#1257=CARTESIAN_POINT('',(5.48665741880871,1.29775311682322,10.));
#1258=LINE('',#1257,#1256);
#1259=CARTESIAN_POINT('',(5.48665741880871,1.29775311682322,0.));
#1260=VERTEX_POINT('',#1259);
#1261=EDGE_CURVE('E1376',#1250,#1260,#1258,.T.);
#1262=ORIENTED_EDGE('',*,*,#1261,.T.);
#1263=DIRECTION('',(0.351123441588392,0.936329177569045,0.));
#1264=VECTOR('',#1263,1.);
#1265=CARTESIAN_POINT('',(5.,0.,0.));
#1266=LINE('',#1265,#1264);
#1267=CARTESIAN_POINT('',(18.4298453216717,35.8129208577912,0.));
#1268=VERTEX_POINT('',#1267);
#1269=EDGE_CURVE('E1452',#1260,#1268,#1266,.T.);
#1270=ORIENTED_EDGE('',*,*,#1269,.T.);
#1271=DIRECTION('',(0.,0.,-1.));
#1272=VECTOR('',#1271,1.);
#1273=CARTESIAN_POINT('',(18.4298453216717,35.8129208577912,10.));
#1274=LINE('',#1273,#1272);
#1275=EDGE_CURVE('E1200',#1252,#1268,#1274,.T.);
#1276=ORIENTED_EDGE('',*,*,#1275,.F.);
#1277=EDGE_LOOP('',(#1254,#1262,#1270,#1276));
#1278=FACE_BOUND('',#1277,.T.);
#1279=ADVANCED_FACE('F1236',(#1278),#1244,.F.);
#1280=CARTESIAN_POINT('',(18.4298453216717,35.8129208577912,10.));
#1281=DIRECTION('',(0.,-1.,0.));
#1282=DIRECTION('',(0.,0.,-1.));
#1283=AXIS2_PLACEMENT_3D('',#1280,#1281,#1282);
#1284=PLANE('',#1283);
#1285=DIRECTION('',(-1.,0.,0.));
#1286=VECTOR('',#1285,1.);
#1287=CARTESIAN_POINT('',(18.4298453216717,35.8129208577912,0.));
#1288=LINE('',#1287,#1286);
#1289=CARTESIAN_POINT('',(10.4298453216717,35.8129208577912,0.));
#1290=VERTEX_POINT('',#1289);
#1291=EDGE_CURVE('E1199',#1268,#1290,#1288,.T.);
#1292=ORIENTED_EDGE('',*,*,#1291,.T.);
#1293=DIRECTION('',(0.,0.,-1.));
#1294=VECTOR('',#1293,1.);
#1295=CARTESIAN_POINT('',(10.4298453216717,35.8129208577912,10.));
#1296=LINE('',#1295,#1294);
#1297=CARTESIAN_POINT('',(10.4298453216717,35.8129208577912,10.));
#1298=VERTEX_POINT('',#1297);
#1299=EDGE_CURVE('E1183',#1298,#1290,#1296,.T.);
#1300=ORIENTED_EDGE('',*,*,#1299,.F.);
#1301=CARTESIAN_POINT('',(18.4298453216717,35.8129208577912,10.));
#1302=CARTESIAN_POINT('',(18.3244223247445,35.8129208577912,10.0562345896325));
#1303=CARTESIAN_POINT('',(18.2178254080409,35.8129208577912,10.1102701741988));
#1304=CARTESIAN_POINT('',(18.0024549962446,35.8129208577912,10.2138154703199));
#1305=CARTESIAN_POINT('',(17.8936814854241,35.8129208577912,10.2633251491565));
#1306=CARTESIAN_POINT('',(17.6741324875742,35.8129208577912,10.3576891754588));
#1307=CARTESIAN_POINT('',(17.5633570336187,35.8129208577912,10.402543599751));
#1308=CARTESIAN_POINT('',(17.3399995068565,35.8129208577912,10.4874756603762));
#1309=CARTESIAN_POINT('',(17.2274174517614,35.8129208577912,10.5275533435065));
#1310=CARTESIAN_POINT('',(16.8875964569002,35.8129208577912,10.6405014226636));
#1311=CARTESIAN_POINT('',(16.6579409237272,35.8129208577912,10.7062334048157));
#1312=CARTESIAN_POINT('',(16.1939903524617,35.8129208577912,10.8183578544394));
#1313=CARTESIAN_POINT('',(15.9596954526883,35.8129208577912,10.86475089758));
#1314=CARTESIAN_POINT('',(15.4878127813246,35.8129208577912,10.9375298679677));
#1315=CARTESIAN_POINT('',(15.2502224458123,35.8129208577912,10.9638992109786));
#1316=CARTESIAN_POINT('',(14.7736330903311,35.8129208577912,10.9964921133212));
#1317=CARTESIAN_POINT('',(14.5346340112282,35.8129208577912,11.0027148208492));
#1318=CARTESIAN_POINT('',(14.1764567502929,35.8129208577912,10.9970604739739));
#1319=CARTESIAN_POINT('',(14.0571161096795,35.8129208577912,10.9926774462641));
#1320=CARTESIAN_POINT('',(13.8187217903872,35.8129208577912,10.978938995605));
#1321=CARTESIAN_POINT('',(13.699668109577,35.8129208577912,10.9695836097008));
#1322=CARTESIAN_POINT('',(13.3432926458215,35.8129208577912,10.9339086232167));
#1323=CARTESIAN_POINT('',(13.1066847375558,35.8129208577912,10.8999791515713));
#1324=CARTESIAN_POINT('',(12.6591986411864,35.8129208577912,10.8164134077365));
#1325=CARTESIAN_POINT('',(12.4479845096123,35.8129208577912,10.768543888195));
#1326=CARTESIAN_POINT('',(12.0297655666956,35.8129208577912,10.6570372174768));
#1327=CARTESIAN_POINT('',(11.8227604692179,35.8129208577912,10.5934011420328));
#1328=CARTESIAN_POINT('',(11.4141034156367,35.8129208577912,10.4503039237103));
#1329=CARTESIAN_POINT('',(11.2124552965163,35.8129208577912,10.3708317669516));
#1330=CARTESIAN_POINT('',(10.9150392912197,35.8129208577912,10.2402007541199));
#1331=CARTESIAN_POINT('',(10.8167286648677,35.8129208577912,10.1947454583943));
#1332=CARTESIAN_POINT('',(10.6219098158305,35.8129208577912,10.1001283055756));
#1333=CARTESIAN_POINT('',(10.5254015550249,35.8129208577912,10.0509665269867));
#1334=CARTESIAN_POINT('',(10.4298453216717,35.8129208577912,10.));
#1335=B_SPLINE_CURVE_WITH_KNOTS('',3,(#1301,#1302,#1303,#1304,#1305,#1306,#1307,#1308,#1309,
#1310,#1311,#1312,#1313,#1314,#1315,#1316,#1317,#1318,#1319,#1320,#1321,#1322,#1323,#1324,#1325,
#1326,#1327,#1328,#1329,#1330,#1331,#1332,#1333,#1334),.UNSPECIFIED.,.F.,.F.,(4,2,2,2,2,2,2,2,2,
2,2,2,2,2,2,2,4),(0.,0.358425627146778,0.716853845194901,1.07527614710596,1.43369493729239,
2.14942052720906,2.86512481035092,3.5814212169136,4.29774790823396,4.65592195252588,
5.01409332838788,5.73022164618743,6.37934173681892,7.02841755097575,7.67794637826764,
8.00281020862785,8.32766716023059),.UNSPECIFIED.);
#1336=EDGE_CURVE('E1197',#1252,#1298,#1335,.T.);
#1337=ORIENTED_EDGE('',*,*,#1336,.F.);
#1338=ORIENTED_EDGE('',*,*,#1275,.T.);
#1339=EDGE_LOOP('',(#1292,#1300,#1337,#1338));
#1340=FACE_BOUND('',#1339,.T.);
#1341=ADVANCED_FACE('F1195',(#1340),#1284,.F.);
#1342=CARTESIAN_POINT('',(0.,8.,10.));
#1343=DIRECTION('',(0.936329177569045,-0.351123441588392,0.));
#1344=DIRECTION('',(0.351123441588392,0.936329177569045,0.));
#1345=AXIS2_PLACEMENT_3D('',#1342,#1343,#1344);
#1346=PLANE('',#1345);
#1347=DIRECTION('',(0.,0.,-1.));
#1348=VECTOR('',#1347,1.);
#1349=CARTESIAN_POINT('',(0.,8.,10.));
#1350=LINE('',#1349,#1348);
#1351=CARTESIAN_POINT('',(0.,8.00000000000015,10.0811945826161));
#1352=VERTEX_POINT('',#1351);
#1353=CARTESIAN_POINT('',(0.,8.,0.));
#1354=VERTEX_POINT('',#1353);
#1355=EDGE_CURVE('E1201',#1352,#1354,#1350,.T.);
#1356=ORIENTED_EDGE('',*,*,#1355,.F.);
#1357=CARTESIAN_POINT('',(3.00649253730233,16.0173134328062,10.));
#1358=CARTESIAN_POINT('',(3.0378998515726,16.1010662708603,9.93647890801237));
#1359=CARTESIAN_POINT('',(3.06904923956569,16.1841313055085,9.8719080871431));
#1360=CARTESIAN_POINT('',(3.13075166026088,16.348671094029,9.74043789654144));
#1361=CARTESIAN_POINT('',(3.1613044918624,16.4301453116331,9.67353776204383));
#1362=CARTESIAN_POINT('',(3.22198099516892,16.5919493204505,9.53661547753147));
#1363=CARTESIAN_POINT('',(3.25209843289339,16.6722624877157,9.46657085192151));
#1364=CARTESIAN_POINT('',(3.31149961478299,16.8306656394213,9.32368292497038));
#1365=CARTESIAN_POINT('',(3.34078345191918,16.9087558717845,9.25083993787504));
#1366=CARTESIAN_POINT('',(3.39956035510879,17.0654942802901,9.09899866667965));
#1367=CARTESIAN_POINT('',(3.42901218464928,17.1440324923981,9.01987042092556));
#1368=CARTESIAN_POINT('',(3.4866314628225,17.29768390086,8.85791146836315));
#1369=CARTESIAN_POINT('',(3.51479908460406,17.3727975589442,8.77508126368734));
#1370=CARTESIAN_POINT('',(3.56945994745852,17.5185598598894,8.60557002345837));
#1371=CARTESIAN_POINT('',(3.59595869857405,17.5892231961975,8.51890346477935));
#1372=CARTESIAN_POINT('',(3.64696450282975,17.7252386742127,8.34097171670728));
#1373=CARTESIAN_POINT('',(3.67147280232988,17.7905941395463,8.24970946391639));
#1374=CARTESIAN_POINT('',(3.70733142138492,17.8862171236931,8.10469950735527));
#1375=CARTESIAN_POINT('',(3.71959437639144,17.9189183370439,8.05277831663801));
#1376=CARTESIAN_POINT('',(3.74321303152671,17.9819014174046,7.94725726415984));
#1377=CARTESIAN_POINT('',(3.75456847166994,18.0121825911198,7.89365692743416));
#1378=CARTESIAN_POINT('',(3.7761498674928,18.0697329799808,7.78491037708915));
#1379=CARTESIAN_POINT('',(3.78638012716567,18.0970136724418,7.72977114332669));
#1380=CARTESIAN_POINT('',(3.80552640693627,18.1480704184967,7.61768783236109));
#1381=CARTESIAN_POINT('',(3.81444292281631,18.1718477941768,7.56074444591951));
#1382=CARTESIAN_POINT('',(3.83348948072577,18.2226386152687,7.42487268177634));
#1383=CARTESIAN_POINT('',(3.8429649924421,18.2479066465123,7.3451790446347));
#1384=CARTESIAN_POINT('',(3.85793782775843,18.2878342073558,7.18274187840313));
#1385=CARTESIAN_POINT('',(3.86344125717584,18.3025100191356,7.10000323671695));
#1386=CARTESIAN_POINT('',(3.86810835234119,18.3149556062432,6.95935027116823));
#1387=CARTESIAN_POINT('',(3.86872512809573,18.3166003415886,6.90184665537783));
#1388=CARTESIAN_POINT('',(3.86681339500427,18.3115023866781,6.78724282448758));
#1389=CARTESIAN_POINT('',(3.8642896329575,18.3047723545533,6.7301421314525));
#1390=CARTESIAN_POINT('',(3.85630834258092,18.2834889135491,6.62709073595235));
#1391=CARTESIAN_POINT('',(3.8513817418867,18.2703513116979,6.58081197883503));
#1392=CARTESIAN_POINT('',(3.83884362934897,18.2369163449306,6.49130559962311));
#1393=CARTESIAN_POINT('',(3.8312341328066,18.2166243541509,6.44807571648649));
#1394=CARTESIAN_POINT('',(3.81347760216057,18.1692736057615,6.36602029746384));
#1395=CARTESIAN_POINT('',(3.8033282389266,18.1422086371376,6.32719885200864));
#1396=CARTESIAN_POINT('',(3.78088765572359,18.0823670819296,6.25495722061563));
#1397=CARTESIAN_POINT('',(3.76859475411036,18.049586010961,6.22154131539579));
#1398=CARTESIAN_POINT('',(3.73867857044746,17.9698095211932,6.151765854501));
#1399=CARTESIAN_POINT('',(3.72053049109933,17.9214146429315,6.11724136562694));
#1400=CARTESIAN_POINT('',(3.68253008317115,17.8200802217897,6.05693367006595));
#1401=CARTESIAN_POINT('',(3.66267422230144,17.7671312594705,6.03116915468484));
#1402=CARTESIAN_POINT('',(3.60977947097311,17.6260785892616,5.97394803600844));
#1403=CARTESIAN_POINT('',(3.57597291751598,17.5359277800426,5.94833728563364));
#1404=CARTESIAN_POINT('',(3.50743680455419,17.3531648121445,5.91139763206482));
#1405=CARTESIAN_POINT('',(3.47270505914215,17.2605468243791,5.90010631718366));
#1406=CARTESIAN_POINT('',(3.40279004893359,17.0741067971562,5.88819249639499));
#1407=CARTESIAN_POINT('',(3.36760533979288,16.9802809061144,5.8876486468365));
#1408=CARTESIAN_POINT('',(3.2973283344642,16.7928755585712,5.89491713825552));
#1409=CARTESIAN_POINT('',(3.26223617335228,16.6992964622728,5.9027382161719));
#1410=CARTESIAN_POINT('',(3.19225741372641,16.5126864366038,5.92501359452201));
#1411=CARTESIAN_POINT('',(3.15737130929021,16.4196568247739,5.93948001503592));
#1412=CARTESIAN_POINT('',(3.08795191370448,16.2345384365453,5.97379344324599));
#1413=CARTESIAN_POINT('',(3.05341846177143,16.1424492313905,5.99363787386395));
#1414=CARTESIAN_POINT('',(2.9621908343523,15.8991755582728,6.05223048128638));
#1415=CARTESIAN_POINT('',(2.90580343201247,15.7488091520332,6.09484490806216));
#1416=CARTESIAN_POINT('',(2.79397956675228,15.4506121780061,6.18931051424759));
#1417=CARTESIAN_POINT('',(2.73854367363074,15.302783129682,6.24116703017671));
#1418=CARTESIAN_POINT('',(2.62847775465,15.0092740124,6.35223175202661));
#1419=CARTESIAN_POINT('',(2.57384943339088,14.8635984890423,6.41145355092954));
#1420=CARTESIAN_POINT('',(2.46540977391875,14.5744260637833,6.53571249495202));
#1421=CARTESIAN_POINT('',(2.41159858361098,14.430929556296,6.60075067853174));
#1422=CARTESIAN_POINT('',(2.30424799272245,14.1446613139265,6.73607964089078));
#1423=CARTESIAN_POINT('',(2.25071488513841,14.0019063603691,6.80641069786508));
#1424=CARTESIAN_POINT('',(2.14428540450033,13.7180944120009,6.95088844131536));
#1425=CARTESIAN_POINT('',(2.09138908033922,13.5770375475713,7.02503541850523));
#1426=CARTESIAN_POINT('',(1.93361028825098,13.1562941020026,7.25180311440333));
#1427=CARTESIAN_POINT('',(1.82952363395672,12.8787296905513,7.40889897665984));
#1428=CARTESIAN_POINT('',(1.65420627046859,12.4112167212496,7.68042265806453));
#1429=CARTESIAN_POINT('',(1.58265692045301,12.2204184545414,7.79321610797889));
#1430=CARTESIAN_POINT('',(1.43981052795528,11.8394947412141,8.02011110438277));
#1431=CARTESIAN_POINT('',(1.36851349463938,11.6493693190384,8.13421269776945));
#1432=CARTESIAN_POINT('',(1.22583584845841,11.2688955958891,8.36193682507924));
#1433=CARTESIAN_POINT('',(1.15445524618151,11.0785473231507,8.47555941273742));
#1434=CARTESIAN_POINT('',(1.01125228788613,10.6966727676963,8.70052308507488));
#1435=CARTESIAN_POINT('',(0.939429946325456,10.5051465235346,8.81186424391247));
#1436=CARTESIAN_POINT('',(0.796767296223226,10.1247127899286,9.02789799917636));
#1437=CARTESIAN_POINT('',(0.725944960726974,9.93585322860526,9.13268611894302));
#1438=CARTESIAN_POINT('',(0.619024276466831,9.65073140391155,9.28597654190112));
#1439=CARTESIAN_POINT('',(0.583269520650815,9.55538538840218,9.33642472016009));
#1440=CARTESIAN_POINT('',(0.511523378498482,9.36406234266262,9.43593865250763));
#1441=CARTESIAN_POINT('',(0.47553199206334,9.26808531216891,9.48500440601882));
#1442=CARTESIAN_POINT('',(0.403238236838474,9.0753019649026,9.58179777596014));
#1443=CARTESIAN_POINT('',(0.366935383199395,8.97849435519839,9.62952245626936));
#1444=CARTESIAN_POINT('',(0.312315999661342,8.83284266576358,9.70007009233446));
#1445=CARTESIAN_POINT('',(0.294081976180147,8.78421860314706,9.723412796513));
#1446=CARTESIAN_POINT('',(0.257562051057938,8.6868321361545,9.76976804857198));
#1447=CARTESIAN_POINT('',(0.239276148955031,8.63806973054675,9.7927805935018));
#1448=CARTESIAN_POINT('',(0.202654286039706,8.54041142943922,9.83850842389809));
#1449=CARTESIAN_POINT('',(0.184318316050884,8.49151550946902,9.8612236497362));
#1450=CARTESIAN_POINT('',(0.156782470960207,8.41808658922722,9.89508470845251));
#1451=CARTESIAN_POINT('',(0.147598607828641,8.39359628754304,9.90633635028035));
#1452=CARTESIAN_POINT('',(0.129224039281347,8.34459743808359,9.92879423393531));
#1453=CARTESIAN_POINT('',(0.120033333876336,8.32008889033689,9.94000047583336));
#1454=CARTESIAN_POINT('',(0.101631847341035,8.27101825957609,9.96227881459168));
#1455=CARTESIAN_POINT('',(0.092421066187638,8.24645617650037,9.97335091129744));
#1456=CARTESIAN_POINT('',(0.0739770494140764,8.19727213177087,9.99534229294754));
#1457=CARTESIAN_POINT('',(0.0647438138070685,8.17265017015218,10.0062615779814));
#1458=CARTESIAN_POINT('',(0.0462556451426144,8.12334838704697,10.0279534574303));
#1459=CARTESIAN_POINT('',(0.0370007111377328,8.09866856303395,10.0387260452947));
#1460=CARTESIAN_POINT('',(0.01846977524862,8.04925273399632,10.0601236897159));
#1461=CARTESIAN_POINT('',(0.00919377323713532,8.02451672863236,10.0707487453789));
#1462=CARTESIAN_POINT('',(-9.25967085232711E-05,7.99975307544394,10.0812997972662));
#1463=B_SPLINE_CURVE_WITH_KNOTS('',3,(#1357,#1358,#1359,#1360,#1361,#1362,#1363,#1364,#1365,
#1366,#1367,#1368,#1369,#1370,#1371,#1372,#1373,#1374,#1375,#1376,#1377,#1378,#1379,#1380,#1381,
#1382,#1383,#1384,#1385,#1386,#1387,#1388,#1389,#1390,#1391,#1392,#1393,#1394,#1395,#1396,#1397,
#1398,#1399,#1400,#1401,#1402,#1403,#1404,#1405,#1406,#1407,#1408,#1409,#1410,#1411,#1412,#1413,
#1414,#1415,#1416,#1417,#1418,#1419,#1420,#1421,#1422,#1423,#1424,#1425,#1426,#1427,#1428,#1429,
#1430,#1431,#1432,#1433,#1434,#1435,#1436,#1437,#1438,#1439,#1440,#1441,#1442,#1443,#1444,#1445,
#1446,#1447,#1448,#1449,#1450,#1451,#1452,#1453,#1454,#1455,#1456,#1457,#1458,#1459,#1460,#1461,
#1462),.UNSPECIFIED.,.F.,.F.,(4,2,2,2,2,2,2,2,2,2,2,2,2,2,2,2,2,2,2,2,2,2,2,2,2,2,2,2,2,2,2,2,2,
2,2,2,2,2,2,2,2,2,2,2,2,2,2,2,2,2,2,2,4),(0.,0.329130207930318,0.658369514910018,
0.990537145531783,1.32266758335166,1.66850425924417,2.01429416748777,2.3588750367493,
2.70323844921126,2.89090089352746,3.0786169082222,3.26558788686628,3.45248812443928,
3.70431765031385,3.95575923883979,4.1278071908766,4.29959541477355,4.44403917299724,
4.58837466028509,4.73284299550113,4.87742518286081,5.0628504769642,5.24866896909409,
5.54587448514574,5.84385855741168,6.14402265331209,6.44450056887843,6.74552869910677,
7.04641283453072,7.54445861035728,8.0427929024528,8.5420609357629,9.04141828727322,
9.54505998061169,10.0487401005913,11.0550275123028,11.7537496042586,12.4524968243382,
13.1511634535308,13.8498073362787,14.5316350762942,14.8725489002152,15.2134628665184,
15.5550727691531,15.7258785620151,15.8966858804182,16.0675269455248,16.15294623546,
16.2383653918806,16.3237846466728,16.4092038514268,16.4946268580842,16.5800503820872),.UNSPECIFIED.);
#1464=CARTESIAN_POINT('',(-9.25967085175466E-05,7.99975307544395,10.0812997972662));
#1465=VERTEX_POINT('',#1464);
#1466=EDGE_CURVE('E1425',#1352,#1465,#1463,.T.);
#1467=ORIENTED_EDGE('',*,*,#1466,.T.);
#1468=CARTESIAN_POINT('',(-0.210843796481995,7.43774987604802,10.2738124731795));
#1469=CARTESIAN_POINT('',(-0.192851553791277,7.48572918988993,10.2525995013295));
#1470=CARTESIAN_POINT('',(-0.174704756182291,7.53412065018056,10.2324622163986));
#1471=CARTESIAN_POINT('',(-0.138122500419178,7.63167333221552,10.1944209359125));
#1472=CARTESIAN_POINT('',(-0.119687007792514,7.68083464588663,10.1765172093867));
#1473=CARTESIAN_POINT('',(-0.0643393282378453,7.82842845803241,10.1266063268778));
#1474=CARTESIAN_POINT('',(-0.027041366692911,7.9278896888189,10.0979914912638));
#1475=CARTESIAN_POINT('',(0.0483693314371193,8.12898488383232,10.0508793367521));
#1476=CARTESIAN_POINT('',(0.0864824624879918,8.23061989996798,10.0323870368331));
#1477=CARTESIAN_POINT('',(0.144180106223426,8.38448028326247,10.0132957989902));
#1478=CARTESIAN_POINT('',(0.163593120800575,8.43624832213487,10.0083708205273));
#1479=CARTESIAN_POINT('',(0.202495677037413,8.53998847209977,10.0017212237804));
#1480=CARTESIAN_POINT('',(0.221985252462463,8.59196067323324,9.9999982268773));
#1481=CARTESIAN_POINT('',(0.241482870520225,8.64395432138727,10.));
#1482=B_SPLINE_CURVE_WITH_KNOTS('',3,(#1468,#1469,#1470,#1471,#1472,#1473,#1474,#1475,#1476,
#1477,#1478,#1479,#1480,#1481),.UNSPECIFIED.,.F.,.F.,(4,2,2,2,2,2,4),(0.,0.166354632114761,
0.332729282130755,0.662301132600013,0.99203624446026,1.15847534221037,1.32499869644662),.UNSPECIFIED.);
#1483=CARTESIAN_POINT('',(0.241482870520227,8.64395432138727,10.));
#1484=VERTEX_POINT('',#1483);
#1485=EDGE_CURVE('E1185',#1465,#1484,#1482,.T.);
#1486=ORIENTED_EDGE('',*,*,#1485,.T.);
#1487=DIRECTION('',(-0.351123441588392,-0.936329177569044,0.));
#1488=VECTOR('',#1487,1.);
#1489=CARTESIAN_POINT('',(0.,8.,10.));
#1490=LINE('',#1489,#1488);
#1491=EDGE_CURVE('E1180',#1298,#1484,#1490,.T.);
#1492=ORIENTED_EDGE('',*,*,#1491,.F.);
#1493=ORIENTED_EDGE('',*,*,#1299,.T.);
#1494=DIRECTION('',(-0.351123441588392,-0.936329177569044,0.));
#1495=VECTOR('',#1494,1.);
#1496=CARTESIAN_POINT('',(0.,8.,0.));
#1497=LINE('',#1496,#1495);
#1498=EDGE_CURVE('E1449',#1290,#1354,#1497,.T.);
#1499=ORIENTED_EDGE('',*,*,#1498,.T.);
#1500=EDGE_LOOP('',(#1356,#1467,#1486,#1492,#1493,#1499));
#1501=FACE_BOUND('',#1500,.T.);
#1502=ADVANCED_FACE('F1182',(#1501),#1346,.F.);
#1503=CARTESIAN_POINT('',(-10.4298453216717,35.8129208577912,10.));
#1504=DIRECTION('',(-0.936329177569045,-0.351123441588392,0.));
#1505=DIRECTION('',(0.351123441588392,-0.936329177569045,0.));
#1506=AXIS2_PLACEMENT_3D('',#1503,#1504,#1505);
#1507=PLANE('',#1506);
#1508=DIRECTION('',(-0.351123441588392,0.936329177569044,0.));
#1509=VECTOR('',#1508,1.);
#1510=CARTESIAN_POINT('',(-10.4298453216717,35.8129208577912,0.));
#1511=LINE('',#1510,#1509);
#1512=EDGE_CURVE('E1447',#1354,#1195,#1511,.T.);
#1513=ORIENTED_EDGE('',*,*,#1512,.T.);
#1514=ORIENTED_EDGE('',*,*,#1211,.F.);
#1515=ORIENTED_EDGE('',*,*,#1170,.F.);
#1516=CARTESIAN_POINT('',(-0.241482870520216,8.64395432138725,10.));
#1517=CARTESIAN_POINT('',(-0.221140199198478,8.5897071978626,9.99999886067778));
#1518=CARTESIAN_POINT('',(-0.200803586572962,8.53547623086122,10.0018721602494));
#1519=CARTESIAN_POINT('',(-0.160269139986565,8.42738437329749,10.009083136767));
#1520=CARTESIAN_POINT('',(-0.140071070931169,8.37352285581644,10.0144099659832));
#1521=CARTESIAN_POINT('',(-0.0998148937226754,8.26617304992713,10.0282460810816));
#1522=CARTESIAN_POINT('',(-0.079756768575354,8.21268471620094,10.0367549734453));
#1523=CARTESIAN_POINT('',(-0.0397605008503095,8.10602800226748,10.0567726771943));
#1524=CARTESIAN_POINT('',(-0.0198229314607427,8.05286115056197,10.0682908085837));
#1525=CARTESIAN_POINT('',(0.,8.,10.0811945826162));
#1526=B_SPLINE_CURVE_WITH_KNOTS('',3,(#1516,#1517,#1518,#1519,#1520,#1521,#1522,#1523,#1524,
#1525),.UNSPECIFIED.,.F.,.F.,(4,2,2,2,4),(0.,0.17375262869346,0.346962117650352,
0.520150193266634,0.693881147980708),.UNSPECIFIED.);
#1527=EDGE_CURVE('E11',#1161,#1352,#1526,.T.);
#1528=ORIENTED_EDGE('',*,*,#1527,.T.);
#1529=ORIENTED_EDGE('',*,*,#1355,.T.);
#1530=EDGE_LOOP('',(#1513,#1514,#1515,#1528,#1529));
#1531=FACE_BOUND('',#1530,.T.);
#1532=ADVANCED_FACE('F1430',(#1531),#1507,.F.);
#1533=CARTESIAN_POINT('',(10.4298453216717,35.8129208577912,0.));
#1534=DIRECTION('',(0.,0.,-1.));
#1535=DIRECTION('',(-1.,0.,0.));
#1536=AXIS2_PLACEMENT_3D('',#1533,#1534,#1535);
#1537=PLANE('',#1536);
#1538=ORIENTED_EDGE('',*,*,#1006,.F.);
#1539=CARTESIAN_POINT('',(-3.61399906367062,2.,0.));
#1540=DIRECTION('',(0.,0.,-1.));
#1541=DIRECTION('',(-1.,0.,0.));
#1542=AXIS2_PLACEMENT_3D('',#1539,#1540,#1541);
#1543=CIRCLE('',#1542,2.);
#1544=EDGE_CURVE('E1337',#997,#1226,#1543,.T.);
#1545=ORIENTED_EDGE('',*,*,#1544,.T.);
#1546=ORIENTED_EDGE('',*,*,#1227,.F.);
#1547=ORIENTED_EDGE('',*,*,#1198,.F.);
#1548=ORIENTED_EDGE('',*,*,#1512,.F.);
#1549=ORIENTED_EDGE('',*,*,#1498,.F.);
#1550=ORIENTED_EDGE('',*,*,#1291,.F.);
#1551=ORIENTED_EDGE('',*,*,#1269,.F.);
#1552=CARTESIAN_POINT('',(3.61399906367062,2.,0.));
#1553=DIRECTION('',(0.,0.,-1.));
#1554=DIRECTION('',(-1.,0.,0.));
#1555=AXIS2_PLACEMENT_3D('',#1552,#1553,#1554);
#1556=CIRCLE('',#1555,2.);
#1557=EDGE_CURVE('E1335',#1260,#1005,#1556,.T.);
#1558=ORIENTED_EDGE('',*,*,#1557,.T.);
#1559=EDGE_LOOP('',(#1538,#1545,#1546,#1547,#1548,#1549,#1550,#1551,#1558));
#1560=FACE_BOUND('',#1559,.T.);
#1561=ADVANCED_FACE('F1472',(#1560),#1537,.T.);
#1562=CARTESIAN_POINT('',(15.3741741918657,48.9977978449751,10.));
#1563=CARTESIAN_POINT('',(15.7690800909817,48.3659484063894,10.3369863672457));
#1564=CARTESIAN_POINT('',(16.1753970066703,47.7158413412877,10.5829041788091));
#1565=CARTESIAN_POINT('',(16.7999449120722,46.7165646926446,10.8314906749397));
#1566=CARTESIAN_POINT('',(17.0106483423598,46.3794392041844,10.8942349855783));
#1567=CARTESIAN_POINT('',(17.4372311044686,45.6969067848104,10.9784159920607));
#1568=CARTESIAN_POINT('',(17.6543106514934,45.3495795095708,10.9996951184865));
#1569=CARTESIAN_POINT('',(18.2996384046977,44.3170551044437,11.00059985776));
#1570=CARTESIAN_POINT('',(18.7247057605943,43.6369473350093,10.9188343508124));
#1571=CARTESIAN_POINT('',(19.3544580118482,42.629343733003,10.6706812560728));
#1572=CARTESIAN_POINT('',(19.5639429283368,42.2941678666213,10.5665382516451));
#1573=CARTESIAN_POINT('',(19.9752989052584,41.6359983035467,10.3151869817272));
#1574=CARTESIAN_POINT('',(20.1768466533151,41.3135219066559,10.1683861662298));
#1575=CARTESIAN_POINT('',(20.3741741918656,40.9977978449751,10.));
#1576=B_SPLINE_CURVE_WITH_KNOTS('',3,(#1562,#1563,#1564,#1565,#1566,#1567,#1568,#1569,#1570,
#1571,#1572,#1573,#1574,#1575),.UNSPECIFIED.,.F.,.F.,(4,2,2,2,2,2,4),(0.,0.25,0.375,0.5,0.75,
0.875,1.),.UNSPECIFIED.);
#1577=DIRECTION('',(-0.351123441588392,-0.936329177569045,0.));
#1578=VECTOR('',#1577,1.);
#1579=SURFACE_OF_LINEAR_EXTRUSION('',#1576,#1578);
#1580=ORIENTED_EDGE('',*,*,#1491,.T.);
#1581=CARTESIAN_POINT('',(-6.27232792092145,19.066051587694,4.4415481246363));
#1582=CARTESIAN_POINT('',(-4.1179151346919,15.6189900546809,6.27998058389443));
#1583=CARTESIAN_POINT('',(-1.96350154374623,12.1719283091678,8.11841351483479));
#1584=CARTESIAN_POINT('',(0.20776953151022,8.69789567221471,9.97123128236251));
#1585=CARTESIAN_POINT('',(0.224626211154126,8.67092499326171,9.98561564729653));
#1586=CARTESIAN_POINT('',(0.241482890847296,8.64395431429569,10.0000000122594));
#1587=CARTESIAN_POINT('',(0.245256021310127,8.63609911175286,10.0035834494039));
#1588=CARTESIAN_POINT('',(0.249045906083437,8.62825551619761,10.0071620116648));
#1589=CARTESIAN_POINT('',(0.25665918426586,8.61259153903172,10.014309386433));
#1590=CARTESIAN_POINT('',(0.260482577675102,8.60477115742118,10.0178781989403));
#1591=CARTESIAN_POINT('',(0.264322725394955,8.59696238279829,10.021442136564));
#1592=CARTESIAN_POINT('',(0.311484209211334,8.50107685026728,10.0652069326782));
#1593=CARTESIAN_POINT('',(0.358791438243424,8.40458703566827,10.1074355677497));
#1594=CARTESIAN_POINT('',(0.453742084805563,8.21048547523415,10.1888625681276));
#1595=CARTESIAN_POINT('',(0.501385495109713,8.11287375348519,10.2280609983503));
#1596=CARTESIAN_POINT('',(0.644866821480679,7.81852718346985,10.3411584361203));
#1597=CARTESIAN_POINT('',(0.741278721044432,7.62023422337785,10.4105808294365));
#1598=CARTESIAN_POINT('',(0.887191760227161,7.32026031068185,10.5059497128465));
#1599=CARTESIAN_POINT('',(0.93605083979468,7.21983522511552,10.5362814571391));
#1600=CARTESIAN_POINT('',(1.03423602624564,7.01819708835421,10.5940638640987));
#1601=CARTESIAN_POINT('',(1.08356213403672,6.91698403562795,10.6215145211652));
#1602=CARTESIAN_POINT('',(1.18267440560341,6.7138409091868,10.6735602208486));
#1603=CARTESIAN_POINT('',(1.23246056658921,6.61191083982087,10.69815528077));
#1604=CARTESIAN_POINT('',(1.30744994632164,6.45842882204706,10.732931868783));
#1605=CARTESIAN_POINT('',(1.33249829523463,6.40716992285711,10.7441714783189));
#1606=CARTESIAN_POINT('',(1.3825695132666,6.30450766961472,10.765912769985));
#1607=CARTESIAN_POINT('',(1.407592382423,6.2531043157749,10.7764144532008));
#1608=CARTESIAN_POINT('',(1.47644476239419,6.11159010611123,10.8042948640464));
#1609=CARTESIAN_POINT('',(1.52030402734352,6.02136272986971,10.8209242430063));
#1610=CARTESIAN_POINT('',(1.60809275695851,5.84058403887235,10.8519578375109));
#1611=CARTESIAN_POINT('',(1.65202222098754,5.75003272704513,10.8663620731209));
#1612=CARTESIAN_POINT('',(1.73993826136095,5.56865636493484,10.8929498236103));
#1613=CARTESIAN_POINT('',(1.78392483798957,5.4778313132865,10.9051333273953));
#1614=CARTESIAN_POINT('',(1.85003905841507,5.34137711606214,10.921761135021));
#1615=CARTESIAN_POINT('',(1.8720996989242,5.29585592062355,10.9270291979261));
#1616=CARTESIAN_POINT('',(1.91611420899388,5.20481058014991,10.936994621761));
#1617=CARTESIAN_POINT('',(1.9380680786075,5.15928643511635,10.9416919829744));
#1618=CARTESIAN_POINT('',(2.00408905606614,5.02274034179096,10.9549604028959));
#1619=CARTESIAN_POINT('',(2.04835948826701,4.9316528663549,10.9627189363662));
#1620=CARTESIAN_POINT('',(2.13715404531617,4.74925748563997,10.9760597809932));
#1621=CARTESIAN_POINT('',(2.18167817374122,4.65794957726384,10.9816420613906));
#1622=CARTESIAN_POINT('',(2.24843416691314,4.52083290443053,10.9883777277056));
#1623=CARTESIAN_POINT('',(2.27067920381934,4.47510551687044,10.9903498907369));
#1624=CARTESIAN_POINT('',(2.31512944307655,4.38359477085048,10.9937488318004));
#1625=CARTESIAN_POINT('',(2.33733464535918,4.33781141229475,10.9951756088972));
#1626=CARTESIAN_POINT('',(2.3816526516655,4.24618379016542,10.9974839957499));
#1627=CARTESIAN_POINT('',(2.40376546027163,4.20033952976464,10.9983656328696));
#1628=CARTESIAN_POINT('',(2.43688482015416,4.13154389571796,10.9992799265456));
#1629=CARTESIAN_POINT('',(2.44791625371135,4.10860723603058,10.9995166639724));
#1630=CARTESIAN_POINT('',(2.46988285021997,4.0626940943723,10.9998541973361));
#1631=CARTESIAN_POINT('',(2.48081801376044,4.03971761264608,10.9999549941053));
#1632=CARTESIAN_POINT('',(2.49456312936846,4.01120844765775,10.9999960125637));
#1633=CARTESIAN_POINT('',(2.49726277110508,4.00562657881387,11.0000000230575));
#1634=CARTESIAN_POINT('',(2.49997176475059,4.00004885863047,11.0000000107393));
#1635=B_SPLINE_CURVE_WITH_KNOTS('',3,(#1581,#1582,#1583,#1584,#1585,#1586,#1587,#1588,#1589,
#1590,#1591,#1592,#1593,#1594,#1595,#1596,#1597,#1598,#1599,#1600,#1601,#1602,#1603,#1604,#1605,
#1606,#1607,#1608,#1609,#1610,#1611,#1612,#1613,#1614,#1615,#1616,#1617,#1618,#1619,#1620,#1621,
#1622,#1623,#1624,#1625,#1626,#1627,#1628,#1629,#1630,#1631,#1632,#1633,#1634),.UNSPECIFIED.,
.F.,.F.,(4,2,3,2,3,2,2,2,2,2,2,2,2,2,2,2,2,2,2,2,2,2,2,2,2,4),(0.,13.3840245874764,
13.4887445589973,13.5214045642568,13.5540645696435,13.9550861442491,14.356099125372,
15.1579300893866,15.5589352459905,15.9599411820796,16.3609446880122,16.5614496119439,
16.7619542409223,17.1128358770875,17.4637143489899,17.8145945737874,17.9900374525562,
18.1654802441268,18.5160112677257,18.8665472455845,19.0417848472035,19.2170227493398,
19.3922518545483,19.4798657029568,19.5674790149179,19.5888240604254),.UNSPECIFIED.);
#1636=EDGE_CURVE('E1489',#1484,#256,#1635,.T.);
#1637=ORIENTED_EDGE('',*,*,#1636,.T.);
#1638=CARTESIAN_POINT('',(2.49997179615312,4.00004884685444,11.0000000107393));
#1639=CARTESIAN_POINT('',(2.50439627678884,3.99468917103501,11.000000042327));
#1640=CARTESIAN_POINT('',(2.508824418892,3.98933035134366,10.9999928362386));
#1641=CARTESIAN_POINT('',(2.54225202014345,3.94890923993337,10.9998838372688));
#1642=CARTESIAN_POINT('',(2.57137730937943,3.91387252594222,10.9994791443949));
#1643=CARTESIAN_POINT('',(2.62952019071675,3.84371394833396,10.9980466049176));
#1644=CARTESIAN_POINT('',(2.65853778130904,3.80859208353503,10.9970187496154));
#1645=CARTESIAN_POINT('',(2.74556067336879,3.7031722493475,10.992996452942));
#1646=CARTESIAN_POINT('',(2.80353418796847,3.63282234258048,10.9890632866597));
#1647=CARTESIAN_POINT('',(2.91931674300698,3.49205912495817,10.9786785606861));
#1648=CARTESIAN_POINT('',(2.97712574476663,3.42164580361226,10.9722264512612));
#1649=CARTESIAN_POINT('',(3.09258115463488,3.28090200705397,10.9567953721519));
#1650=CARTESIAN_POINT('',(3.15022756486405,3.21057153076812,10.9478164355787));
#1651=CARTESIAN_POINT('',(3.26534203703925,3.07001268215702,10.9273267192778));
#1652=CARTESIAN_POINT('',(3.32280984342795,2.99978449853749,10.9158132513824));
#1653=CARTESIAN_POINT('',(3.43741220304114,2.85958905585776,10.8902830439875));
#1654=CARTESIAN_POINT('',(3.49454675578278,2.78962179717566,10.8762663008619));
#1655=CARTESIAN_POINT('',(3.60844570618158,2.65006719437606,10.8457593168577));
#1656=CARTESIAN_POINT('',(3.66521011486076,2.58047983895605,10.8292691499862));
#1657=CARTESIAN_POINT('',(3.75005450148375,2.47643208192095,10.8027025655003));
#1658=CARTESIAN_POINT('',(3.77828592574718,2.44180463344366,10.793541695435));
#1659=CARTESIAN_POINT('',(3.83457597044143,2.37269409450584,10.774634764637));
#1660=CARTESIAN_POINT('',(3.86263459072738,2.33821100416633,10.7648887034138));
#1661=CARTESIAN_POINT('',(3.9052735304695,2.28592167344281,10.7496029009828));
#1662=CARTESIAN_POINT('',(3.91982631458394,2.26809501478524,10.7443020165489));
#1663=CARTESIAN_POINT('',(3.94889779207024,2.23246998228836,10.7335380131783));
#1664=CARTESIAN_POINT('',(3.96341648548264,2.21467160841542,10.7280748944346));
#1665=CARTESIAN_POINT('',(4.00692818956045,2.16131485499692,10.7114408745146));
#1666=CARTESIAN_POINT('',(4.03587671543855,2.12579497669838,10.7000253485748));
#1667=CARTESIAN_POINT('',(4.12257487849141,2.01940550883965,10.6647917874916));
#1668=CARTESIAN_POINT('',(4.18017846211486,1.94870441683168,10.6399862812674));
#1669=CARTESIAN_POINT('',(4.2951031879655,1.80777753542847,10.5876751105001));
#1670=CARTESIAN_POINT('',(4.35242433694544,1.73755173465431,10.560169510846));
#1671=CARTESIAN_POINT('',(4.43816457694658,1.63259543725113,10.5168533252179));
#1672=CARTESIAN_POINT('',(4.46670455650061,1.59767355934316,10.5020715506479));
#1673=CARTESIAN_POINT('',(4.52377476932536,1.52792688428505,10.4717781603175));
#1674=CARTESIAN_POINT('',(4.55230500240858,1.49310208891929,10.456266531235));
#1675=CARTESIAN_POINT('',(4.60903464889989,1.42369100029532,10.4246517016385));
#1676=CARTESIAN_POINT('',(4.63723425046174,1.38910457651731,10.4085488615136));
#1677=CARTESIAN_POINT('',(4.69350529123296,1.32009272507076,10.3756700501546));
#1678=CARTESIAN_POINT('',(4.72157672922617,1.28566729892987,10.3588940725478));
#1679=CARTESIAN_POINT('',(4.8055053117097,1.18267158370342,10.3075954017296));
#1680=CARTESIAN_POINT('',(4.86107560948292,1.1143832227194,10.2721025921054));
#1681=CARTESIAN_POINT('',(4.97138212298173,0.978623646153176,10.1985845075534));
#1682=CARTESIAN_POINT('',(5.02611819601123,0.911152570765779,10.1605588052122));
#1683=CARTESIAN_POINT('',(5.13463904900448,0.77711879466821,10.0820778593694));
#1684=CARTESIAN_POINT('',(5.18842386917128,0.710556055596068,10.041622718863));
#1685=CARTESIAN_POINT('',(5.2416815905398,0.644484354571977,10.0000000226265));
#1686=CARTESIAN_POINT('',(5.24683424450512,0.635956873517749,9.99554644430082));
#1687=CARTESIAN_POINT('',(5.25201633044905,0.62745325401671,9.99108194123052));
#1688=CARTESIAN_POINT('',(5.26243936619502,0.610493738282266,9.98213108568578));
#1689=CARTESIAN_POINT('',(5.26768031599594,0.602037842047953,9.97764473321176));
#1690=CARTESIAN_POINT('',(5.27295069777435,0.593605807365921,9.97314745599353));
#1691=CARTESIAN_POINT('',(5.46527882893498,0.285880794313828,9.80902745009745));
#1692=CARTESIAN_POINT('',(5.6576069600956,-0.0218442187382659,9.64490744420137));
#1693=CARTESIAN_POINT('',(5.84993509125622,-0.32956923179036,9.48078743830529));
#1694=B_SPLINE_CURVE_WITH_KNOTS('',3,(#1638,#1639,#1640,#1641,#1642,#1643,#1644,#1645,#1646,
#1647,#1648,#1649,#1650,#1651,#1652,#1653,#1654,#1655,#1656,#1657,#1658,#1659,#1660,#1661,#1662,
#1663,#1664,#1665,#1666,#1667,#1668,#1669,#1670,#1671,#1672,#1673,#1674,#1675,#1676,#1677,#1678,
#1679,#1680,#1681,#1682,#1683,#1684,#1685,#1686,#1687,#1688,#1689,#1690,#1691,#1692,#1693),
.UNSPECIFIED.,.F.,.F.,(4,2,2,2,2,2,2,2,2,2,2,2,2,2,2,2,2,2,2,2,2,2,2,3,2,3,4),(0.,
0.0168758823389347,0.127307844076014,0.237741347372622,0.458615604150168,0.679538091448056,
0.900457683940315,1.12161272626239,1.34276808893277,1.56391683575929,1.67449383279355,
1.78507092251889,1.84230600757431,1.89954102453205,2.01401148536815,2.24294705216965,
2.47187711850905,2.5863433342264,2.70081164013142,2.81521129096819,2.92961202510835,
3.15841799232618,3.38726266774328,3.61609764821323,3.64883713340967,3.68157661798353,
4.87639105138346),.UNSPECIFIED.);
#1695=CARTESIAN_POINT('',(5.16589148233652,0.738401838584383,10.0581730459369));
#1696=VERTEX_POINT('',#1695);
#1697=EDGE_CURVE('E1480',#256,#1696,#1694,.T.);
#1698=ORIENTED_EDGE('',*,*,#1697,.T.);
#1699=CARTESIAN_POINT('',(4.77002972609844,0.367948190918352,10.1850534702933));
#1700=CARTESIAN_POINT('',(4.81214442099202,0.39778580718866,10.1704225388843));
#1701=CARTESIAN_POINT('',(4.85321818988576,0.429324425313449,10.1563578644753));
#1702=CARTESIAN_POINT('',(4.93307341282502,0.495755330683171,10.1295926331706));
#1703=CARTESIAN_POINT('',(4.97185348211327,0.530649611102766,10.1168928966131));
#1704=CARTESIAN_POINT('',(5.08224135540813,0.638170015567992,10.0818872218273));
#1705=CARTESIAN_POINT('',(5.15030350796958,0.715335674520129,10.061821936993));
#1706=CARTESIAN_POINT('',(5.2403696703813,0.835046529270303,10.0383838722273));
#1707=CARTESIAN_POINT('',(5.26721756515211,0.87346657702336,10.0318812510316));
#1708=CARTESIAN_POINT('',(5.31825918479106,0.952289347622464,10.0206024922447));
#1709=CARTESIAN_POINT('',(5.34245304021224,0.992691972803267,10.0158262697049));
#1710=CARTESIAN_POINT('',(5.38856333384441,1.07628121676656,10.0080083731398));
#1711=CARTESIAN_POINT('',(5.41040697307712,1.11951234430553,10.005013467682));
#1712=CARTESIAN_POINT('',(5.45094147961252,1.20753654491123,10.0010050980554));
#1713=CARTESIAN_POINT('',(5.46963112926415,1.25233021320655,9.99999239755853));
#1714=CARTESIAN_POINT('',(5.4866574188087,1.29775311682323,10.));
#1715=B_SPLINE_CURVE_WITH_KNOTS('',3,(#1699,#1700,#1701,#1702,#1703,#1704,#1705,#1706,#1707,
#1708,#1709,#1710,#1711,#1712,#1713,#1714),.UNSPECIFIED.,.F.,.F.,(4,2,2,2,2,2,2,4),(0.,
0.160843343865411,0.321782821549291,0.634556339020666,0.776406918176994,0.918250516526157,
1.06367035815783,1.20914621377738),.UNSPECIFIED.);
#1716=EDGE_CURVE('E1479',#1696,#1250,#1715,.T.);
#1717=ORIENTED_EDGE('',*,*,#1716,.T.);
#1718=ORIENTED_EDGE('',*,*,#1253,.T.);
#1719=ORIENTED_EDGE('',*,*,#1336,.T.);
#1720=EDGE_LOOP('',(#1580,#1637,#1698,#1717,#1718,#1719));
#1721=FACE_BOUND('',#1720,.T.);
#1722=ADVANCED_FACE('F1203',(#1721),#1579,.F.);
#1723=CARTESIAN_POINT('',(-3.61399906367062,2.,10.));
#1724=DIRECTION('',(0.,0.,-1.));
#1725=DIRECTION('',(-1.,0.,0.));
#1726=AXIS2_PLACEMENT_3D('',#1723,#1724,#1725);
#1727=CYLINDRICAL_SURFACE('',#1726,2.);
#1728=ORIENTED_EDGE('',*,*,#724,.F.);
#1729=CARTESIAN_POINT('',(-4.29081133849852,0.117999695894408,10.0617679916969));
#1730=CARTESIAN_POINT('',(-4.33378543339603,0.133451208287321,10.0697107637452));
#1731=CARTESIAN_POINT('',(-4.37637946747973,0.150435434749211,10.0766385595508));
#1732=CARTESIAN_POINT('',(-4.46053830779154,0.187409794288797,10.0884311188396));
#1733=CARTESIAN_POINT('',(-4.50210305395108,0.207400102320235,10.0932957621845));
#1734=CARTESIAN_POINT('',(-4.62268857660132,0.270658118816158,10.1045432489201));
#1735=CARTESIAN_POINT('',(-4.69988966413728,0.318036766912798,10.1079983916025));
#1736=CARTESIAN_POINT('',(-4.84620679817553,0.422144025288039,10.106964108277));
#1737=CARTESIAN_POINT('',(-4.91541041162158,0.478750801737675,10.1025716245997));
#1738=CARTESIAN_POINT('',(-5.01355390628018,0.570548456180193,10.0903323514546));
#1739=CARTESIAN_POINT('',(-5.0456988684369,0.602755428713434,10.0852068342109));
#1740=CARTESIAN_POINT('',(-5.10755906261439,0.669084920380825,10.0730880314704));
#1741=CARTESIAN_POINT('',(-5.13727469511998,0.703207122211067,10.0660950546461));
#1742=CARTESIAN_POINT('',(-5.16571302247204,0.738182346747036,10.0582073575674));
#1743=B_SPLINE_CURVE_WITH_KNOTS('',3,(#1729,#1730,#1731,#1732,#1733,#1734,#1735,#1736,#1737,
#1738,#1739,#1740,#1741,#1742),.UNSPECIFIED.,.F.,.F.,(4,2,2,2,2,2,4),(0.,0.138988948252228,
0.277985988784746,0.548663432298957,0.816020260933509,0.953268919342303,1.09049490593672),.UNSPECIFIED.);
#1744=EDGE_CURVE('E1086',#702,#1045,#1743,.T.);
#1745=ORIENTED_EDGE('',*,*,#1744,.T.);
#1746=ORIENTED_EDGE('',*,*,#1046,.F.);
#1747=ORIENTED_EDGE('',*,*,#1233,.F.);
#1748=ORIENTED_EDGE('',*,*,#1544,.F.);
#1749=ORIENTED_EDGE('',*,*,#998,.F.);
#1750=EDGE_LOOP('',(#1728,#1745,#1746,#1747,#1748,#1749));
#1751=FACE_BOUND('',#1750,.T.);
#1752=ADVANCED_FACE('F1353',(#1751),#1727,.T.);
#1753=CARTESIAN_POINT('',(3.61399906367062,2.,10.));
#1754=DIRECTION('',(0.,0.,-1.));
#1755=DIRECTION('',(-1.,0.,0.));
#1756=AXIS2_PLACEMENT_3D('',#1753,#1754,#1755);
#1757=CYLINDRICAL_SURFACE('',#1756,2.);
#1758=ORIENTED_EDGE('',*,*,#1716,.F.);
#1759=CARTESIAN_POINT('',(5.16589148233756,0.738401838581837,10.0581730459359));
#1760=CARTESIAN_POINT('',(5.13754911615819,0.703534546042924,10.0660352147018));
#1761=CARTESIAN_POINT('',(5.10793752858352,0.669514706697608,10.073009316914));
#1762=CARTESIAN_POINT('',(5.04630032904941,0.603376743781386,10.0851043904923));
#1763=CARTESIAN_POINT('',(5.0142743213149,0.57125893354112,10.0902250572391));
#1764=CARTESIAN_POINT('',(4.91649621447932,0.479696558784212,10.102472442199));
#1765=CARTESIAN_POINT('',(4.84755727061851,0.423215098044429,10.106897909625));
#1766=CARTESIAN_POINT('',(4.70130829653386,0.318936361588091,10.1080471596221));
#1767=CARTESIAN_POINT('',(4.6238628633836,0.271326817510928,10.1046213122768));
#1768=CARTESIAN_POINT('',(4.50287085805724,0.207776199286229,10.0933765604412));
#1769=CARTESIAN_POINT('',(4.46115958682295,0.187695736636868,10.0885051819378));
#1770=CARTESIAN_POINT('',(4.37669900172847,0.150562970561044,10.0766857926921));
#1771=CARTESIAN_POINT('',(4.33394975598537,0.133510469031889,10.0697379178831));
#1772=CARTESIAN_POINT('',(4.29081722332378,0.118001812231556,10.0617690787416));
#1773=B_SPLINE_CURVE_WITH_KNOTS('',3,(#1759,#1760,#1761,#1762,#1763,#1764,#1765,#1766,#1767,
#1768,#1769,#1770,#1771,#1772),.UNSPECIFIED.,.F.,.F.,(4,2,2,2,2,2,4),(0.,0.136787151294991,
0.273596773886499,0.540120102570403,0.811764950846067,0.951273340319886,1.0907725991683),.UNSPECIFIED.);
#1774=EDGE_CURVE('E1496',#1696,#752,#1773,.T.);
#1775=ORIENTED_EDGE('',*,*,#1774,.T.);
#1776=ORIENTED_EDGE('',*,*,#753,.F.);
#1777=ORIENTED_EDGE('',*,*,#1012,.F.);
#1778=ORIENTED_EDGE('',*,*,#1557,.F.);
#1779=ORIENTED_EDGE('',*,*,#1261,.F.);
#1780=EDGE_LOOP('',(#1758,#1775,#1776,#1777,#1778,#1779));
#1781=FACE_BOUND('',#1780,.T.);
#1782=ADVANCED_FACE('F1290',(#1781),#1757,.T.);
#1783=ORIENTED_EDGE('',*,*,#1485,.F.);
#1784=CARTESIAN_POINT('',(-9.25967085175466E-05,7.99975307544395,10.0812997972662));
#1785=CARTESIAN_POINT('',(-0.000116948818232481,7.93060646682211,10.1044828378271));
#1786=CARTESIAN_POINT('',(-0.000143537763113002,7.86163190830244,10.1281717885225));
#1787=CARTESIAN_POINT('',(-0.000197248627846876,7.72402983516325,10.1765446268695));
#1788=CARTESIAN_POINT('',(-0.000224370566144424,7.65540233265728,10.2012285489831));
#1789=CARTESIAN_POINT('',(-0.000300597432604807,7.45011667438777,10.2767211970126));
#1790=CARTESIAN_POINT('',(-0.000344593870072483,7.31399002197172,10.3289927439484));
#1791=CARTESIAN_POINT('',(-0.000369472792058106,7.17594555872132,10.3843828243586));
#1792=CARTESIAN_POINT('',(-0.000369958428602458,7.17320666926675,10.3854827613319));
#1793=CARTESIAN_POINT('',(-0.000370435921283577,7.17046811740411,10.3865835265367));
#1794=B_SPLINE_CURVE_WITH_KNOTS('',3,(#1784,#1785,#1786,#1787,#1788,#1789,#1790,#1791,#1792,
#1793),.UNSPECIFIED.,.F.,.F.,(4,2,2,2,4),(0.,0.218781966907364,0.437571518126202,
0.874943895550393,0.883798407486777),.UNSPECIFIED.);
#1795=EDGE_CURVE('E1101',#1465,#258,#1794,.T.);
#1796=ORIENTED_EDGE('',*,*,#1795,.T.);
#1797=ORIENTED_EDGE('',*,*,#259,.F.);
#1798=ORIENTED_EDGE('',*,*,#1636,.F.);
#1799=EDGE_LOOP('',(#1783,#1796,#1797,#1798));
#1800=FACE_BOUND('',#1799,.T.);
#1801=ADVANCED_FACE('F1267',(#1800),#199,.F.);
#1802=ORIENTED_EDGE('',*,*,#1697,.F.);
#1803=ORIENTED_EDGE('',*,*,#981,.F.);
#1804=ORIENTED_EDGE('',*,*,#1774,.F.);
#1805=EDGE_LOOP('',(#1802,#1803,#1804));
#1806=FACE_BOUND('',#1805,.T.);
#1807=ADVANCED_FACE('F1261',(#1806),#923,.T.);
#1808=ORIENTED_EDGE('',*,*,#1744,.F.);
#1809=ORIENTED_EDGE('',*,*,#703,.F.);
#1810=ORIENTED_EDGE('',*,*,#1096,.F.);
#1811=EDGE_LOOP('',(#1808,#1809,#1810));
#1812=FACE_BOUND('',#1811,.T.);
#1813=ADVANCED_FACE('F1266',(#1812),#652,.T.);
#1814=ORIENTED_EDGE('',*,*,#1162,.F.);
#1815=ORIENTED_EDGE('',*,*,#509,.F.);
#1816=ORIENTED_EDGE('',*,*,#1795,.F.);
#1817=ORIENTED_EDGE('',*,*,#1466,.F.);
#1818=ORIENTED_EDGE('',*,*,#1527,.F.);
#1819=EDGE_LOOP('',(#1814,#1815,#1816,#1817,#1818));
#1820=FACE_BOUND('',#1819,.T.);
#1821=ADVANCED_FACE('F1397',(#1820),#444,.F.);
#1822=CLOSED_SHELL('',(#985,#1016,#1184,#1215,#1239,#1279,#1341,#1502,#1532,#1561,#1722,#1752,
#1782,#1801,#1807,#1813,#1821));
#1823=MANIFOLD_SOLID_BREP('B2',#1822);
#1824=ADVANCED_BREP_SHAPE_REPRESENTATION('',(#18,#1823),#14);
#1825=SHAPE_DEFINITION_REPRESENTATION(#9,#1824);
ENDSEC;
END-ISO-10303-21;
